VERSION 5.4 ;
NAMESCASESENSITIVE ON ;
BUSBITCHARS "[]" ;
DIVIDERCHAR "/" ;
UNITS
  DATABASE MICRONS 2000 ;
END UNITS
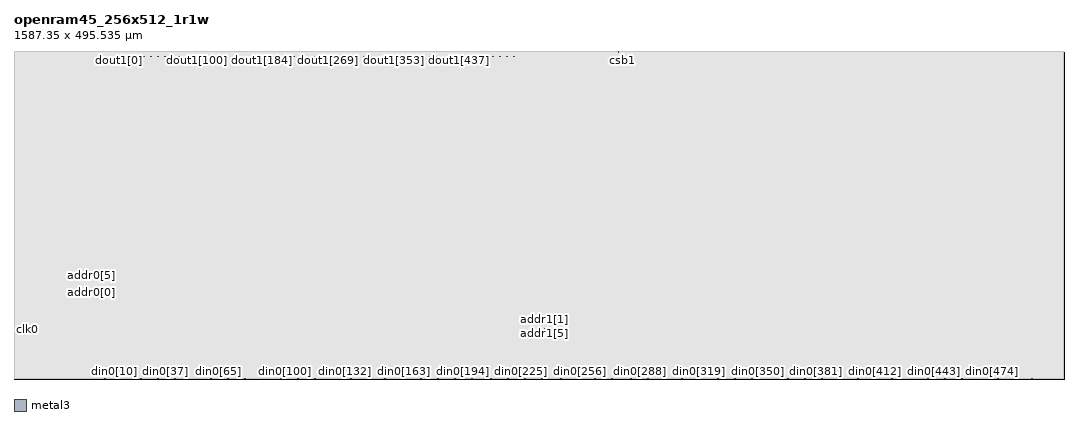
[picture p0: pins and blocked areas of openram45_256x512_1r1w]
MACRO openram45_256x512_1r1w
   CLASS BLOCK ;
   SIZE 1587.345 BY 495.535 ;
   SYMMETRY X Y R90 ;
   PIN din0[0]
      DIRECTION INPUT ;
      PORT
         LAYER metal3 ;
         RECT  123.24 1.0375 123.375 1.1725 ;
      END
   END din0[0]
   PIN din0[1]
      DIRECTION INPUT ;
      PORT
         LAYER metal3 ;
         RECT  126.1 1.0375 126.235 1.1725 ;
      END
   END din0[1]
   PIN din0[2]
      DIRECTION INPUT ;
      PORT
         LAYER metal3 ;
         RECT  128.96 1.0375 129.095 1.1725 ;
      END
   END din0[2]
   PIN din0[3]
      DIRECTION INPUT ;
      PORT
         LAYER metal3 ;
         RECT  131.82 1.0375 131.955 1.1725 ;
      END
   END din0[3]
   PIN din0[4]
      DIRECTION INPUT ;
      PORT
         LAYER metal3 ;
         RECT  134.68 1.0375 134.815 1.1725 ;
      END
   END din0[4]
   PIN din0[5]
      DIRECTION INPUT ;
      PORT
         LAYER metal3 ;
         RECT  137.54 1.0375 137.675 1.1725 ;
      END
   END din0[5]
   PIN din0[6]
      DIRECTION INPUT ;
      PORT
         LAYER metal3 ;
         RECT  140.4 1.0375 140.535 1.1725 ;
      END
   END din0[6]
   PIN din0[7]
      DIRECTION INPUT ;
      PORT
         LAYER metal3 ;
         RECT  143.26 1.0375 143.395 1.1725 ;
      END
   END din0[7]
   PIN din0[8]
      DIRECTION INPUT ;
      PORT
         LAYER metal3 ;
         RECT  146.12 1.0375 146.255 1.1725 ;
      END
   END din0[8]
   PIN din0[9]
      DIRECTION INPUT ;
      PORT
         LAYER metal3 ;
         RECT  148.98 1.0375 149.115 1.1725 ;
      END
   END din0[9]
   PIN din0[10]
      DIRECTION INPUT ;
      PORT
         LAYER metal3 ;
         RECT  151.84 1.0375 151.975 1.1725 ;
      END
   END din0[10]
   PIN din0[11]
      DIRECTION INPUT ;
      PORT
         LAYER metal3 ;
         RECT  154.7 1.0375 154.835 1.1725 ;
      END
   END din0[11]
   PIN din0[12]
      DIRECTION INPUT ;
      PORT
         LAYER metal3 ;
         RECT  157.56 1.0375 157.695 1.1725 ;
      END
   END din0[12]
   PIN din0[13]
      DIRECTION INPUT ;
      PORT
         LAYER metal3 ;
         RECT  160.42 1.0375 160.555 1.1725 ;
      END
   END din0[13]
   PIN din0[14]
      DIRECTION INPUT ;
      PORT
         LAYER metal3 ;
         RECT  163.28 1.0375 163.415 1.1725 ;
      END
   END din0[14]
   PIN din0[15]
      DIRECTION INPUT ;
      PORT
         LAYER metal3 ;
         RECT  166.14 1.0375 166.275 1.1725 ;
      END
   END din0[15]
   PIN din0[16]
      DIRECTION INPUT ;
      PORT
         LAYER metal3 ;
         RECT  169.0 1.0375 169.135 1.1725 ;
      END
   END din0[16]
   PIN din0[17]
      DIRECTION INPUT ;
      PORT
         LAYER metal3 ;
         RECT  171.86 1.0375 171.995 1.1725 ;
      END
   END din0[17]
   PIN din0[18]
      DIRECTION INPUT ;
      PORT
         LAYER metal3 ;
         RECT  174.72 1.0375 174.855 1.1725 ;
      END
   END din0[18]
   PIN din0[19]
      DIRECTION INPUT ;
      PORT
         LAYER metal3 ;
         RECT  177.58 1.0375 177.715 1.1725 ;
      END
   END din0[19]
   PIN din0[20]
      DIRECTION INPUT ;
      PORT
         LAYER metal3 ;
         RECT  180.44 1.0375 180.575 1.1725 ;
      END
   END din0[20]
   PIN din0[21]
      DIRECTION INPUT ;
      PORT
         LAYER metal3 ;
         RECT  183.3 1.0375 183.435 1.1725 ;
      END
   END din0[21]
   PIN din0[22]
      DIRECTION INPUT ;
      PORT
         LAYER metal3 ;
         RECT  186.16 1.0375 186.295 1.1725 ;
      END
   END din0[22]
   PIN din0[23]
      DIRECTION INPUT ;
      PORT
         LAYER metal3 ;
         RECT  189.02 1.0375 189.155 1.1725 ;
      END
   END din0[23]
   PIN din0[24]
      DIRECTION INPUT ;
      PORT
         LAYER metal3 ;
         RECT  191.88 1.0375 192.015 1.1725 ;
      END
   END din0[24]
   PIN din0[25]
      DIRECTION INPUT ;
      PORT
         LAYER metal3 ;
         RECT  194.74 1.0375 194.875 1.1725 ;
      END
   END din0[25]
   PIN din0[26]
      DIRECTION INPUT ;
      PORT
         LAYER metal3 ;
         RECT  197.6 1.0375 197.735 1.1725 ;
      END
   END din0[26]
   PIN din0[27]
      DIRECTION INPUT ;
      PORT
         LAYER metal3 ;
         RECT  200.46 1.0375 200.595 1.1725 ;
      END
   END din0[27]
   PIN din0[28]
      DIRECTION INPUT ;
      PORT
         LAYER metal3 ;
         RECT  203.32 1.0375 203.455 1.1725 ;
      END
   END din0[28]
   PIN din0[29]
      DIRECTION INPUT ;
      PORT
         LAYER metal3 ;
         RECT  206.18 1.0375 206.315 1.1725 ;
      END
   END din0[29]
   PIN din0[30]
      DIRECTION INPUT ;
      PORT
         LAYER metal3 ;
         RECT  209.04 1.0375 209.175 1.1725 ;
      END
   END din0[30]
   PIN din0[31]
      DIRECTION INPUT ;
      PORT
         LAYER metal3 ;
         RECT  211.9 1.0375 212.035 1.1725 ;
      END
   END din0[31]
   PIN din0[32]
      DIRECTION INPUT ;
      PORT
         LAYER metal3 ;
         RECT  214.76 1.0375 214.895 1.1725 ;
      END
   END din0[32]
   PIN din0[33]
      DIRECTION INPUT ;
      PORT
         LAYER metal3 ;
         RECT  217.62 1.0375 217.755 1.1725 ;
      END
   END din0[33]
   PIN din0[34]
      DIRECTION INPUT ;
      PORT
         LAYER metal3 ;
         RECT  220.48 1.0375 220.615 1.1725 ;
      END
   END din0[34]
   PIN din0[35]
      DIRECTION INPUT ;
      PORT
         LAYER metal3 ;
         RECT  223.34 1.0375 223.475 1.1725 ;
      END
   END din0[35]
   PIN din0[36]
      DIRECTION INPUT ;
      PORT
         LAYER metal3 ;
         RECT  226.2 1.0375 226.335 1.1725 ;
      END
   END din0[36]
   PIN din0[37]
      DIRECTION INPUT ;
      PORT
         LAYER metal3 ;
         RECT  229.06 1.0375 229.195 1.1725 ;
      END
   END din0[37]
   PIN din0[38]
      DIRECTION INPUT ;
      PORT
         LAYER metal3 ;
         RECT  231.92 1.0375 232.055 1.1725 ;
      END
   END din0[38]
   PIN din0[39]
      DIRECTION INPUT ;
      PORT
         LAYER metal3 ;
         RECT  234.78 1.0375 234.915 1.1725 ;
      END
   END din0[39]
   PIN din0[40]
      DIRECTION INPUT ;
      PORT
         LAYER metal3 ;
         RECT  237.64 1.0375 237.775 1.1725 ;
      END
   END din0[40]
   PIN din0[41]
      DIRECTION INPUT ;
      PORT
         LAYER metal3 ;
         RECT  240.5 1.0375 240.635 1.1725 ;
      END
   END din0[41]
   PIN din0[42]
      DIRECTION INPUT ;
      PORT
         LAYER metal3 ;
         RECT  243.36 1.0375 243.495 1.1725 ;
      END
   END din0[42]
   PIN din0[43]
      DIRECTION INPUT ;
      PORT
         LAYER metal3 ;
         RECT  246.22 1.0375 246.355 1.1725 ;
      END
   END din0[43]
   PIN din0[44]
      DIRECTION INPUT ;
      PORT
         LAYER metal3 ;
         RECT  249.08 1.0375 249.215 1.1725 ;
      END
   END din0[44]
   PIN din0[45]
      DIRECTION INPUT ;
      PORT
         LAYER metal3 ;
         RECT  251.94 1.0375 252.075 1.1725 ;
      END
   END din0[45]
   PIN din0[46]
      DIRECTION INPUT ;
      PORT
         LAYER metal3 ;
         RECT  254.8 1.0375 254.935 1.1725 ;
      END
   END din0[46]
   PIN din0[47]
      DIRECTION INPUT ;
      PORT
         LAYER metal3 ;
         RECT  257.66 1.0375 257.795 1.1725 ;
      END
   END din0[47]
   PIN din0[48]
      DIRECTION INPUT ;
      PORT
         LAYER metal3 ;
         RECT  260.52 1.0375 260.655 1.1725 ;
      END
   END din0[48]
   PIN din0[49]
      DIRECTION INPUT ;
      PORT
         LAYER metal3 ;
         RECT  263.38 1.0375 263.515 1.1725 ;
      END
   END din0[49]
   PIN din0[50]
      DIRECTION INPUT ;
      PORT
         LAYER metal3 ;
         RECT  266.24 1.0375 266.375 1.1725 ;
      END
   END din0[50]
   PIN din0[51]
      DIRECTION INPUT ;
      PORT
         LAYER metal3 ;
         RECT  269.1 1.0375 269.235 1.1725 ;
      END
   END din0[51]
   PIN din0[52]
      DIRECTION INPUT ;
      PORT
         LAYER metal3 ;
         RECT  271.96 1.0375 272.095 1.1725 ;
      END
   END din0[52]
   PIN din0[53]
      DIRECTION INPUT ;
      PORT
         LAYER metal3 ;
         RECT  274.82 1.0375 274.955 1.1725 ;
      END
   END din0[53]
   PIN din0[54]
      DIRECTION INPUT ;
      PORT
         LAYER metal3 ;
         RECT  277.68 1.0375 277.815 1.1725 ;
      END
   END din0[54]
   PIN din0[55]
      DIRECTION INPUT ;
      PORT
         LAYER metal3 ;
         RECT  280.54 1.0375 280.675 1.1725 ;
      END
   END din0[55]
   PIN din0[56]
      DIRECTION INPUT ;
      PORT
         LAYER metal3 ;
         RECT  283.4 1.0375 283.535 1.1725 ;
      END
   END din0[56]
   PIN din0[57]
      DIRECTION INPUT ;
      PORT
         LAYER metal3 ;
         RECT  286.26 1.0375 286.395 1.1725 ;
      END
   END din0[57]
   PIN din0[58]
      DIRECTION INPUT ;
      PORT
         LAYER metal3 ;
         RECT  289.12 1.0375 289.255 1.1725 ;
      END
   END din0[58]
   PIN din0[59]
      DIRECTION INPUT ;
      PORT
         LAYER metal3 ;
         RECT  291.98 1.0375 292.115 1.1725 ;
      END
   END din0[59]
   PIN din0[60]
      DIRECTION INPUT ;
      PORT
         LAYER metal3 ;
         RECT  294.84 1.0375 294.975 1.1725 ;
      END
   END din0[60]
   PIN din0[61]
      DIRECTION INPUT ;
      PORT
         LAYER metal3 ;
         RECT  297.7 1.0375 297.835 1.1725 ;
      END
   END din0[61]
   PIN din0[62]
      DIRECTION INPUT ;
      PORT
         LAYER metal3 ;
         RECT  300.56 1.0375 300.695 1.1725 ;
      END
   END din0[62]
   PIN din0[63]
      DIRECTION INPUT ;
      PORT
         LAYER metal3 ;
         RECT  303.42 1.0375 303.555 1.1725 ;
      END
   END din0[63]
   PIN din0[64]
      DIRECTION INPUT ;
      PORT
         LAYER metal3 ;
         RECT  306.28 1.0375 306.415 1.1725 ;
      END
   END din0[64]
   PIN din0[65]
      DIRECTION INPUT ;
      PORT
         LAYER metal3 ;
         RECT  309.14 1.0375 309.275 1.1725 ;
      END
   END din0[65]
   PIN din0[66]
      DIRECTION INPUT ;
      PORT
         LAYER metal3 ;
         RECT  312.0 1.0375 312.135 1.1725 ;
      END
   END din0[66]
   PIN din0[67]
      DIRECTION INPUT ;
      PORT
         LAYER metal3 ;
         RECT  314.86 1.0375 314.995 1.1725 ;
      END
   END din0[67]
   PIN din0[68]
      DIRECTION INPUT ;
      PORT
         LAYER metal3 ;
         RECT  317.72 1.0375 317.855 1.1725 ;
      END
   END din0[68]
   PIN din0[69]
      DIRECTION INPUT ;
      PORT
         LAYER metal3 ;
         RECT  320.58 1.0375 320.715 1.1725 ;
      END
   END din0[69]
   PIN din0[70]
      DIRECTION INPUT ;
      PORT
         LAYER metal3 ;
         RECT  323.44 1.0375 323.575 1.1725 ;
      END
   END din0[70]
   PIN din0[71]
      DIRECTION INPUT ;
      PORT
         LAYER metal3 ;
         RECT  326.3 1.0375 326.435 1.1725 ;
      END
   END din0[71]
   PIN din0[72]
      DIRECTION INPUT ;
      PORT
         LAYER metal3 ;
         RECT  329.16 1.0375 329.295 1.1725 ;
      END
   END din0[72]
   PIN din0[73]
      DIRECTION INPUT ;
      PORT
         LAYER metal3 ;
         RECT  332.02 1.0375 332.155 1.1725 ;
      END
   END din0[73]
   PIN din0[74]
      DIRECTION INPUT ;
      PORT
         LAYER metal3 ;
         RECT  334.88 1.0375 335.015 1.1725 ;
      END
   END din0[74]
   PIN din0[75]
      DIRECTION INPUT ;
      PORT
         LAYER metal3 ;
         RECT  337.74 1.0375 337.875 1.1725 ;
      END
   END din0[75]
   PIN din0[76]
      DIRECTION INPUT ;
      PORT
         LAYER metal3 ;
         RECT  340.6 1.0375 340.735 1.1725 ;
      END
   END din0[76]
   PIN din0[77]
      DIRECTION INPUT ;
      PORT
         LAYER metal3 ;
         RECT  343.46 1.0375 343.595 1.1725 ;
      END
   END din0[77]
   PIN din0[78]
      DIRECTION INPUT ;
      PORT
         LAYER metal3 ;
         RECT  346.32 1.0375 346.455 1.1725 ;
      END
   END din0[78]
   PIN din0[79]
      DIRECTION INPUT ;
      PORT
         LAYER metal3 ;
         RECT  349.18 1.0375 349.315 1.1725 ;
      END
   END din0[79]
   PIN din0[80]
      DIRECTION INPUT ;
      PORT
         LAYER metal3 ;
         RECT  352.04 1.0375 352.175 1.1725 ;
      END
   END din0[80]
   PIN din0[81]
      DIRECTION INPUT ;
      PORT
         LAYER metal3 ;
         RECT  354.9 1.0375 355.035 1.1725 ;
      END
   END din0[81]
   PIN din0[82]
      DIRECTION INPUT ;
      PORT
         LAYER metal3 ;
         RECT  357.76 1.0375 357.895 1.1725 ;
      END
   END din0[82]
   PIN din0[83]
      DIRECTION INPUT ;
      PORT
         LAYER metal3 ;
         RECT  360.62 1.0375 360.755 1.1725 ;
      END
   END din0[83]
   PIN din0[84]
      DIRECTION INPUT ;
      PORT
         LAYER metal3 ;
         RECT  363.48 1.0375 363.615 1.1725 ;
      END
   END din0[84]
   PIN din0[85]
      DIRECTION INPUT ;
      PORT
         LAYER metal3 ;
         RECT  366.34 1.0375 366.475 1.1725 ;
      END
   END din0[85]
   PIN din0[86]
      DIRECTION INPUT ;
      PORT
         LAYER metal3 ;
         RECT  369.2 1.0375 369.335 1.1725 ;
      END
   END din0[86]
   PIN din0[87]
      DIRECTION INPUT ;
      PORT
         LAYER metal3 ;
         RECT  372.06 1.0375 372.195 1.1725 ;
      END
   END din0[87]
   PIN din0[88]
      DIRECTION INPUT ;
      PORT
         LAYER metal3 ;
         RECT  374.92 1.0375 375.055 1.1725 ;
      END
   END din0[88]
   PIN din0[89]
      DIRECTION INPUT ;
      PORT
         LAYER metal3 ;
         RECT  377.78 1.0375 377.915 1.1725 ;
      END
   END din0[89]
   PIN din0[90]
      DIRECTION INPUT ;
      PORT
         LAYER metal3 ;
         RECT  380.64 1.0375 380.775 1.1725 ;
      END
   END din0[90]
   PIN din0[91]
      DIRECTION INPUT ;
      PORT
         LAYER metal3 ;
         RECT  383.5 1.0375 383.635 1.1725 ;
      END
   END din0[91]
   PIN din0[92]
      DIRECTION INPUT ;
      PORT
         LAYER metal3 ;
         RECT  386.36 1.0375 386.495 1.1725 ;
      END
   END din0[92]
   PIN din0[93]
      DIRECTION INPUT ;
      PORT
         LAYER metal3 ;
         RECT  389.22 1.0375 389.355 1.1725 ;
      END
   END din0[93]
   PIN din0[94]
      DIRECTION INPUT ;
      PORT
         LAYER metal3 ;
         RECT  392.08 1.0375 392.215 1.1725 ;
      END
   END din0[94]
   PIN din0[95]
      DIRECTION INPUT ;
      PORT
         LAYER metal3 ;
         RECT  394.94 1.0375 395.075 1.1725 ;
      END
   END din0[95]
   PIN din0[96]
      DIRECTION INPUT ;
      PORT
         LAYER metal3 ;
         RECT  397.8 1.0375 397.935 1.1725 ;
      END
   END din0[96]
   PIN din0[97]
      DIRECTION INPUT ;
      PORT
         LAYER metal3 ;
         RECT  400.66 1.0375 400.795 1.1725 ;
      END
   END din0[97]
   PIN din0[98]
      DIRECTION INPUT ;
      PORT
         LAYER metal3 ;
         RECT  403.52 1.0375 403.655 1.1725 ;
      END
   END din0[98]
   PIN din0[99]
      DIRECTION INPUT ;
      PORT
         LAYER metal3 ;
         RECT  406.38 1.0375 406.515 1.1725 ;
      END
   END din0[99]
   PIN din0[100]
      DIRECTION INPUT ;
      PORT
         LAYER metal3 ;
         RECT  409.24 1.0375 409.375 1.1725 ;
      END
   END din0[100]
   PIN din0[101]
      DIRECTION INPUT ;
      PORT
         LAYER metal3 ;
         RECT  412.1 1.0375 412.235 1.1725 ;
      END
   END din0[101]
   PIN din0[102]
      DIRECTION INPUT ;
      PORT
         LAYER metal3 ;
         RECT  414.96 1.0375 415.095 1.1725 ;
      END
   END din0[102]
   PIN din0[103]
      DIRECTION INPUT ;
      PORT
         LAYER metal3 ;
         RECT  417.82 1.0375 417.955 1.1725 ;
      END
   END din0[103]
   PIN din0[104]
      DIRECTION INPUT ;
      PORT
         LAYER metal3 ;
         RECT  420.68 1.0375 420.815 1.1725 ;
      END
   END din0[104]
   PIN din0[105]
      DIRECTION INPUT ;
      PORT
         LAYER metal3 ;
         RECT  423.54 1.0375 423.675 1.1725 ;
      END
   END din0[105]
   PIN din0[106]
      DIRECTION INPUT ;
      PORT
         LAYER metal3 ;
         RECT  426.4 1.0375 426.535 1.1725 ;
      END
   END din0[106]
   PIN din0[107]
      DIRECTION INPUT ;
      PORT
         LAYER metal3 ;
         RECT  429.26 1.0375 429.395 1.1725 ;
      END
   END din0[107]
   PIN din0[108]
      DIRECTION INPUT ;
      PORT
         LAYER metal3 ;
         RECT  432.12 1.0375 432.255 1.1725 ;
      END
   END din0[108]
   PIN din0[109]
      DIRECTION INPUT ;
      PORT
         LAYER metal3 ;
         RECT  434.98 1.0375 435.115 1.1725 ;
      END
   END din0[109]
   PIN din0[110]
      DIRECTION INPUT ;
      PORT
         LAYER metal3 ;
         RECT  437.84 1.0375 437.975 1.1725 ;
      END
   END din0[110]
   PIN din0[111]
      DIRECTION INPUT ;
      PORT
         LAYER metal3 ;
         RECT  440.7 1.0375 440.835 1.1725 ;
      END
   END din0[111]
   PIN din0[112]
      DIRECTION INPUT ;
      PORT
         LAYER metal3 ;
         RECT  443.56 1.0375 443.695 1.1725 ;
      END
   END din0[112]
   PIN din0[113]
      DIRECTION INPUT ;
      PORT
         LAYER metal3 ;
         RECT  446.42 1.0375 446.555 1.1725 ;
      END
   END din0[113]
   PIN din0[114]
      DIRECTION INPUT ;
      PORT
         LAYER metal3 ;
         RECT  449.28 1.0375 449.415 1.1725 ;
      END
   END din0[114]
   PIN din0[115]
      DIRECTION INPUT ;
      PORT
         LAYER metal3 ;
         RECT  452.14 1.0375 452.275 1.1725 ;
      END
   END din0[115]
   PIN din0[116]
      DIRECTION INPUT ;
      PORT
         LAYER metal3 ;
         RECT  455.0 1.0375 455.135 1.1725 ;
      END
   END din0[116]
   PIN din0[117]
      DIRECTION INPUT ;
      PORT
         LAYER metal3 ;
         RECT  457.86 1.0375 457.995 1.1725 ;
      END
   END din0[117]
   PIN din0[118]
      DIRECTION INPUT ;
      PORT
         LAYER metal3 ;
         RECT  460.72 1.0375 460.855 1.1725 ;
      END
   END din0[118]
   PIN din0[119]
      DIRECTION INPUT ;
      PORT
         LAYER metal3 ;
         RECT  463.58 1.0375 463.715 1.1725 ;
      END
   END din0[119]
   PIN din0[120]
      DIRECTION INPUT ;
      PORT
         LAYER metal3 ;
         RECT  466.44 1.0375 466.575 1.1725 ;
      END
   END din0[120]
   PIN din0[121]
      DIRECTION INPUT ;
      PORT
         LAYER metal3 ;
         RECT  469.3 1.0375 469.435 1.1725 ;
      END
   END din0[121]
   PIN din0[122]
      DIRECTION INPUT ;
      PORT
         LAYER metal3 ;
         RECT  472.16 1.0375 472.295 1.1725 ;
      END
   END din0[122]
   PIN din0[123]
      DIRECTION INPUT ;
      PORT
         LAYER metal3 ;
         RECT  475.02 1.0375 475.155 1.1725 ;
      END
   END din0[123]
   PIN din0[124]
      DIRECTION INPUT ;
      PORT
         LAYER metal3 ;
         RECT  477.88 1.0375 478.015 1.1725 ;
      END
   END din0[124]
   PIN din0[125]
      DIRECTION INPUT ;
      PORT
         LAYER metal3 ;
         RECT  480.74 1.0375 480.875 1.1725 ;
      END
   END din0[125]
   PIN din0[126]
      DIRECTION INPUT ;
      PORT
         LAYER metal3 ;
         RECT  483.6 1.0375 483.735 1.1725 ;
      END
   END din0[126]
   PIN din0[127]
      DIRECTION INPUT ;
      PORT
         LAYER metal3 ;
         RECT  486.46 1.0375 486.595 1.1725 ;
      END
   END din0[127]
   PIN din0[128]
      DIRECTION INPUT ;
      PORT
         LAYER metal3 ;
         RECT  489.32 1.0375 489.455 1.1725 ;
      END
   END din0[128]
   PIN din0[129]
      DIRECTION INPUT ;
      PORT
         LAYER metal3 ;
         RECT  492.18 1.0375 492.315 1.1725 ;
      END
   END din0[129]
   PIN din0[130]
      DIRECTION INPUT ;
      PORT
         LAYER metal3 ;
         RECT  495.04 1.0375 495.175 1.1725 ;
      END
   END din0[130]
   PIN din0[131]
      DIRECTION INPUT ;
      PORT
         LAYER metal3 ;
         RECT  497.9 1.0375 498.035 1.1725 ;
      END
   END din0[131]
   PIN din0[132]
      DIRECTION INPUT ;
      PORT
         LAYER metal3 ;
         RECT  500.76 1.0375 500.895 1.1725 ;
      END
   END din0[132]
   PIN din0[133]
      DIRECTION INPUT ;
      PORT
         LAYER metal3 ;
         RECT  503.62 1.0375 503.755 1.1725 ;
      END
   END din0[133]
   PIN din0[134]
      DIRECTION INPUT ;
      PORT
         LAYER metal3 ;
         RECT  506.48 1.0375 506.615 1.1725 ;
      END
   END din0[134]
   PIN din0[135]
      DIRECTION INPUT ;
      PORT
         LAYER metal3 ;
         RECT  509.34 1.0375 509.475 1.1725 ;
      END
   END din0[135]
   PIN din0[136]
      DIRECTION INPUT ;
      PORT
         LAYER metal3 ;
         RECT  512.2 1.0375 512.335 1.1725 ;
      END
   END din0[136]
   PIN din0[137]
      DIRECTION INPUT ;
      PORT
         LAYER metal3 ;
         RECT  515.06 1.0375 515.195 1.1725 ;
      END
   END din0[137]
   PIN din0[138]
      DIRECTION INPUT ;
      PORT
         LAYER metal3 ;
         RECT  517.92 1.0375 518.055 1.1725 ;
      END
   END din0[138]
   PIN din0[139]
      DIRECTION INPUT ;
      PORT
         LAYER metal3 ;
         RECT  520.78 1.0375 520.915 1.1725 ;
      END
   END din0[139]
   PIN din0[140]
      DIRECTION INPUT ;
      PORT
         LAYER metal3 ;
         RECT  523.64 1.0375 523.775 1.1725 ;
      END
   END din0[140]
   PIN din0[141]
      DIRECTION INPUT ;
      PORT
         LAYER metal3 ;
         RECT  526.5 1.0375 526.635 1.1725 ;
      END
   END din0[141]
   PIN din0[142]
      DIRECTION INPUT ;
      PORT
         LAYER metal3 ;
         RECT  529.36 1.0375 529.495 1.1725 ;
      END
   END din0[142]
   PIN din0[143]
      DIRECTION INPUT ;
      PORT
         LAYER metal3 ;
         RECT  532.22 1.0375 532.355 1.1725 ;
      END
   END din0[143]
   PIN din0[144]
      DIRECTION INPUT ;
      PORT
         LAYER metal3 ;
         RECT  535.08 1.0375 535.215 1.1725 ;
      END
   END din0[144]
   PIN din0[145]
      DIRECTION INPUT ;
      PORT
         LAYER metal3 ;
         RECT  537.94 1.0375 538.075 1.1725 ;
      END
   END din0[145]
   PIN din0[146]
      DIRECTION INPUT ;
      PORT
         LAYER metal3 ;
         RECT  540.8 1.0375 540.935 1.1725 ;
      END
   END din0[146]
   PIN din0[147]
      DIRECTION INPUT ;
      PORT
         LAYER metal3 ;
         RECT  543.66 1.0375 543.795 1.1725 ;
      END
   END din0[147]
   PIN din0[148]
      DIRECTION INPUT ;
      PORT
         LAYER metal3 ;
         RECT  546.52 1.0375 546.655 1.1725 ;
      END
   END din0[148]
   PIN din0[149]
      DIRECTION INPUT ;
      PORT
         LAYER metal3 ;
         RECT  549.38 1.0375 549.515 1.1725 ;
      END
   END din0[149]
   PIN din0[150]
      DIRECTION INPUT ;
      PORT
         LAYER metal3 ;
         RECT  552.24 1.0375 552.375 1.1725 ;
      END
   END din0[150]
   PIN din0[151]
      DIRECTION INPUT ;
      PORT
         LAYER metal3 ;
         RECT  555.1 1.0375 555.235 1.1725 ;
      END
   END din0[151]
   PIN din0[152]
      DIRECTION INPUT ;
      PORT
         LAYER metal3 ;
         RECT  557.96 1.0375 558.095 1.1725 ;
      END
   END din0[152]
   PIN din0[153]
      DIRECTION INPUT ;
      PORT
         LAYER metal3 ;
         RECT  560.82 1.0375 560.955 1.1725 ;
      END
   END din0[153]
   PIN din0[154]
      DIRECTION INPUT ;
      PORT
         LAYER metal3 ;
         RECT  563.68 1.0375 563.815 1.1725 ;
      END
   END din0[154]
   PIN din0[155]
      DIRECTION INPUT ;
      PORT
         LAYER metal3 ;
         RECT  566.54 1.0375 566.675 1.1725 ;
      END
   END din0[155]
   PIN din0[156]
      DIRECTION INPUT ;
      PORT
         LAYER metal3 ;
         RECT  569.4 1.0375 569.535 1.1725 ;
      END
   END din0[156]
   PIN din0[157]
      DIRECTION INPUT ;
      PORT
         LAYER metal3 ;
         RECT  572.26 1.0375 572.395 1.1725 ;
      END
   END din0[157]
   PIN din0[158]
      DIRECTION INPUT ;
      PORT
         LAYER metal3 ;
         RECT  575.12 1.0375 575.255 1.1725 ;
      END
   END din0[158]
   PIN din0[159]
      DIRECTION INPUT ;
      PORT
         LAYER metal3 ;
         RECT  577.98 1.0375 578.115 1.1725 ;
      END
   END din0[159]
   PIN din0[160]
      DIRECTION INPUT ;
      PORT
         LAYER metal3 ;
         RECT  580.84 1.0375 580.975 1.1725 ;
      END
   END din0[160]
   PIN din0[161]
      DIRECTION INPUT ;
      PORT
         LAYER metal3 ;
         RECT  583.7 1.0375 583.835 1.1725 ;
      END
   END din0[161]
   PIN din0[162]
      DIRECTION INPUT ;
      PORT
         LAYER metal3 ;
         RECT  586.56 1.0375 586.695 1.1725 ;
      END
   END din0[162]
   PIN din0[163]
      DIRECTION INPUT ;
      PORT
         LAYER metal3 ;
         RECT  589.42 1.0375 589.555 1.1725 ;
      END
   END din0[163]
   PIN din0[164]
      DIRECTION INPUT ;
      PORT
         LAYER metal3 ;
         RECT  592.28 1.0375 592.415 1.1725 ;
      END
   END din0[164]
   PIN din0[165]
      DIRECTION INPUT ;
      PORT
         LAYER metal3 ;
         RECT  595.14 1.0375 595.275 1.1725 ;
      END
   END din0[165]
   PIN din0[166]
      DIRECTION INPUT ;
      PORT
         LAYER metal3 ;
         RECT  598.0 1.0375 598.135 1.1725 ;
      END
   END din0[166]
   PIN din0[167]
      DIRECTION INPUT ;
      PORT
         LAYER metal3 ;
         RECT  600.86 1.0375 600.995 1.1725 ;
      END
   END din0[167]
   PIN din0[168]
      DIRECTION INPUT ;
      PORT
         LAYER metal3 ;
         RECT  603.72 1.0375 603.855 1.1725 ;
      END
   END din0[168]
   PIN din0[169]
      DIRECTION INPUT ;
      PORT
         LAYER metal3 ;
         RECT  606.58 1.0375 606.715 1.1725 ;
      END
   END din0[169]
   PIN din0[170]
      DIRECTION INPUT ;
      PORT
         LAYER metal3 ;
         RECT  609.44 1.0375 609.575 1.1725 ;
      END
   END din0[170]
   PIN din0[171]
      DIRECTION INPUT ;
      PORT
         LAYER metal3 ;
         RECT  612.3 1.0375 612.435 1.1725 ;
      END
   END din0[171]
   PIN din0[172]
      DIRECTION INPUT ;
      PORT
         LAYER metal3 ;
         RECT  615.16 1.0375 615.295 1.1725 ;
      END
   END din0[172]
   PIN din0[173]
      DIRECTION INPUT ;
      PORT
         LAYER metal3 ;
         RECT  618.02 1.0375 618.155 1.1725 ;
      END
   END din0[173]
   PIN din0[174]
      DIRECTION INPUT ;
      PORT
         LAYER metal3 ;
         RECT  620.88 1.0375 621.015 1.1725 ;
      END
   END din0[174]
   PIN din0[175]
      DIRECTION INPUT ;
      PORT
         LAYER metal3 ;
         RECT  623.74 1.0375 623.875 1.1725 ;
      END
   END din0[175]
   PIN din0[176]
      DIRECTION INPUT ;
      PORT
         LAYER metal3 ;
         RECT  626.6 1.0375 626.735 1.1725 ;
      END
   END din0[176]
   PIN din0[177]
      DIRECTION INPUT ;
      PORT
         LAYER metal3 ;
         RECT  629.46 1.0375 629.595 1.1725 ;
      END
   END din0[177]
   PIN din0[178]
      DIRECTION INPUT ;
      PORT
         LAYER metal3 ;
         RECT  632.32 1.0375 632.455 1.1725 ;
      END
   END din0[178]
   PIN din0[179]
      DIRECTION INPUT ;
      PORT
         LAYER metal3 ;
         RECT  635.18 1.0375 635.315 1.1725 ;
      END
   END din0[179]
   PIN din0[180]
      DIRECTION INPUT ;
      PORT
         LAYER metal3 ;
         RECT  638.04 1.0375 638.175 1.1725 ;
      END
   END din0[180]
   PIN din0[181]
      DIRECTION INPUT ;
      PORT
         LAYER metal3 ;
         RECT  640.9 1.0375 641.035 1.1725 ;
      END
   END din0[181]
   PIN din0[182]
      DIRECTION INPUT ;
      PORT
         LAYER metal3 ;
         RECT  643.76 1.0375 643.895 1.1725 ;
      END
   END din0[182]
   PIN din0[183]
      DIRECTION INPUT ;
      PORT
         LAYER metal3 ;
         RECT  646.62 1.0375 646.755 1.1725 ;
      END
   END din0[183]
   PIN din0[184]
      DIRECTION INPUT ;
      PORT
         LAYER metal3 ;
         RECT  649.48 1.0375 649.615 1.1725 ;
      END
   END din0[184]
   PIN din0[185]
      DIRECTION INPUT ;
      PORT
         LAYER metal3 ;
         RECT  652.34 1.0375 652.475 1.1725 ;
      END
   END din0[185]
   PIN din0[186]
      DIRECTION INPUT ;
      PORT
         LAYER metal3 ;
         RECT  655.2 1.0375 655.335 1.1725 ;
      END
   END din0[186]
   PIN din0[187]
      DIRECTION INPUT ;
      PORT
         LAYER metal3 ;
         RECT  658.06 1.0375 658.195 1.1725 ;
      END
   END din0[187]
   PIN din0[188]
      DIRECTION INPUT ;
      PORT
         LAYER metal3 ;
         RECT  660.92 1.0375 661.055 1.1725 ;
      END
   END din0[188]
   PIN din0[189]
      DIRECTION INPUT ;
      PORT
         LAYER metal3 ;
         RECT  663.78 1.0375 663.915 1.1725 ;
      END
   END din0[189]
   PIN din0[190]
      DIRECTION INPUT ;
      PORT
         LAYER metal3 ;
         RECT  666.64 1.0375 666.775 1.1725 ;
      END
   END din0[190]
   PIN din0[191]
      DIRECTION INPUT ;
      PORT
         LAYER metal3 ;
         RECT  669.5 1.0375 669.635 1.1725 ;
      END
   END din0[191]
   PIN din0[192]
      DIRECTION INPUT ;
      PORT
         LAYER metal3 ;
         RECT  672.36 1.0375 672.495 1.1725 ;
      END
   END din0[192]
   PIN din0[193]
      DIRECTION INPUT ;
      PORT
         LAYER metal3 ;
         RECT  675.22 1.0375 675.355 1.1725 ;
      END
   END din0[193]
   PIN din0[194]
      DIRECTION INPUT ;
      PORT
         LAYER metal3 ;
         RECT  678.08 1.0375 678.215 1.1725 ;
      END
   END din0[194]
   PIN din0[195]
      DIRECTION INPUT ;
      PORT
         LAYER metal3 ;
         RECT  680.94 1.0375 681.075 1.1725 ;
      END
   END din0[195]
   PIN din0[196]
      DIRECTION INPUT ;
      PORT
         LAYER metal3 ;
         RECT  683.8 1.0375 683.935 1.1725 ;
      END
   END din0[196]
   PIN din0[197]
      DIRECTION INPUT ;
      PORT
         LAYER metal3 ;
         RECT  686.66 1.0375 686.795 1.1725 ;
      END
   END din0[197]
   PIN din0[198]
      DIRECTION INPUT ;
      PORT
         LAYER metal3 ;
         RECT  689.52 1.0375 689.655 1.1725 ;
      END
   END din0[198]
   PIN din0[199]
      DIRECTION INPUT ;
      PORT
         LAYER metal3 ;
         RECT  692.38 1.0375 692.515 1.1725 ;
      END
   END din0[199]
   PIN din0[200]
      DIRECTION INPUT ;
      PORT
         LAYER metal3 ;
         RECT  695.24 1.0375 695.375 1.1725 ;
      END
   END din0[200]
   PIN din0[201]
      DIRECTION INPUT ;
      PORT
         LAYER metal3 ;
         RECT  698.1 1.0375 698.235 1.1725 ;
      END
   END din0[201]
   PIN din0[202]
      DIRECTION INPUT ;
      PORT
         LAYER metal3 ;
         RECT  700.96 1.0375 701.095 1.1725 ;
      END
   END din0[202]
   PIN din0[203]
      DIRECTION INPUT ;
      PORT
         LAYER metal3 ;
         RECT  703.82 1.0375 703.955 1.1725 ;
      END
   END din0[203]
   PIN din0[204]
      DIRECTION INPUT ;
      PORT
         LAYER metal3 ;
         RECT  706.68 1.0375 706.815 1.1725 ;
      END
   END din0[204]
   PIN din0[205]
      DIRECTION INPUT ;
      PORT
         LAYER metal3 ;
         RECT  709.54 1.0375 709.675 1.1725 ;
      END
   END din0[205]
   PIN din0[206]
      DIRECTION INPUT ;
      PORT
         LAYER metal3 ;
         RECT  712.4 1.0375 712.535 1.1725 ;
      END
   END din0[206]
   PIN din0[207]
      DIRECTION INPUT ;
      PORT
         LAYER metal3 ;
         RECT  715.26 1.0375 715.395 1.1725 ;
      END
   END din0[207]
   PIN din0[208]
      DIRECTION INPUT ;
      PORT
         LAYER metal3 ;
         RECT  718.12 1.0375 718.255 1.1725 ;
      END
   END din0[208]
   PIN din0[209]
      DIRECTION INPUT ;
      PORT
         LAYER metal3 ;
         RECT  720.98 1.0375 721.115 1.1725 ;
      END
   END din0[209]
   PIN din0[210]
      DIRECTION INPUT ;
      PORT
         LAYER metal3 ;
         RECT  723.84 1.0375 723.975 1.1725 ;
      END
   END din0[210]
   PIN din0[211]
      DIRECTION INPUT ;
      PORT
         LAYER metal3 ;
         RECT  726.7 1.0375 726.835 1.1725 ;
      END
   END din0[211]
   PIN din0[212]
      DIRECTION INPUT ;
      PORT
         LAYER metal3 ;
         RECT  729.56 1.0375 729.695 1.1725 ;
      END
   END din0[212]
   PIN din0[213]
      DIRECTION INPUT ;
      PORT
         LAYER metal3 ;
         RECT  732.42 1.0375 732.555 1.1725 ;
      END
   END din0[213]
   PIN din0[214]
      DIRECTION INPUT ;
      PORT
         LAYER metal3 ;
         RECT  735.28 1.0375 735.415 1.1725 ;
      END
   END din0[214]
   PIN din0[215]
      DIRECTION INPUT ;
      PORT
         LAYER metal3 ;
         RECT  738.14 1.0375 738.275 1.1725 ;
      END
   END din0[215]
   PIN din0[216]
      DIRECTION INPUT ;
      PORT
         LAYER metal3 ;
         RECT  741.0 1.0375 741.135 1.1725 ;
      END
   END din0[216]
   PIN din0[217]
      DIRECTION INPUT ;
      PORT
         LAYER metal3 ;
         RECT  743.86 1.0375 743.995 1.1725 ;
      END
   END din0[217]
   PIN din0[218]
      DIRECTION INPUT ;
      PORT
         LAYER metal3 ;
         RECT  746.72 1.0375 746.855 1.1725 ;
      END
   END din0[218]
   PIN din0[219]
      DIRECTION INPUT ;
      PORT
         LAYER metal3 ;
         RECT  749.58 1.0375 749.715 1.1725 ;
      END
   END din0[219]
   PIN din0[220]
      DIRECTION INPUT ;
      PORT
         LAYER metal3 ;
         RECT  752.44 1.0375 752.575 1.1725 ;
      END
   END din0[220]
   PIN din0[221]
      DIRECTION INPUT ;
      PORT
         LAYER metal3 ;
         RECT  755.3 1.0375 755.435 1.1725 ;
      END
   END din0[221]
   PIN din0[222]
      DIRECTION INPUT ;
      PORT
         LAYER metal3 ;
         RECT  758.16 1.0375 758.295 1.1725 ;
      END
   END din0[222]
   PIN din0[223]
      DIRECTION INPUT ;
      PORT
         LAYER metal3 ;
         RECT  761.02 1.0375 761.155 1.1725 ;
      END
   END din0[223]
   PIN din0[224]
      DIRECTION INPUT ;
      PORT
         LAYER metal3 ;
         RECT  763.88 1.0375 764.015 1.1725 ;
      END
   END din0[224]
   PIN din0[225]
      DIRECTION INPUT ;
      PORT
         LAYER metal3 ;
         RECT  766.74 1.0375 766.875 1.1725 ;
      END
   END din0[225]
   PIN din0[226]
      DIRECTION INPUT ;
      PORT
         LAYER metal3 ;
         RECT  769.6 1.0375 769.735 1.1725 ;
      END
   END din0[226]
   PIN din0[227]
      DIRECTION INPUT ;
      PORT
         LAYER metal3 ;
         RECT  772.46 1.0375 772.595 1.1725 ;
      END
   END din0[227]
   PIN din0[228]
      DIRECTION INPUT ;
      PORT
         LAYER metal3 ;
         RECT  775.32 1.0375 775.455 1.1725 ;
      END
   END din0[228]
   PIN din0[229]
      DIRECTION INPUT ;
      PORT
         LAYER metal3 ;
         RECT  778.18 1.0375 778.315 1.1725 ;
      END
   END din0[229]
   PIN din0[230]
      DIRECTION INPUT ;
      PORT
         LAYER metal3 ;
         RECT  781.04 1.0375 781.175 1.1725 ;
      END
   END din0[230]
   PIN din0[231]
      DIRECTION INPUT ;
      PORT
         LAYER metal3 ;
         RECT  783.9 1.0375 784.035 1.1725 ;
      END
   END din0[231]
   PIN din0[232]
      DIRECTION INPUT ;
      PORT
         LAYER metal3 ;
         RECT  786.76 1.0375 786.895 1.1725 ;
      END
   END din0[232]
   PIN din0[233]
      DIRECTION INPUT ;
      PORT
         LAYER metal3 ;
         RECT  789.62 1.0375 789.755 1.1725 ;
      END
   END din0[233]
   PIN din0[234]
      DIRECTION INPUT ;
      PORT
         LAYER metal3 ;
         RECT  792.48 1.0375 792.615 1.1725 ;
      END
   END din0[234]
   PIN din0[235]
      DIRECTION INPUT ;
      PORT
         LAYER metal3 ;
         RECT  795.34 1.0375 795.475 1.1725 ;
      END
   END din0[235]
   PIN din0[236]
      DIRECTION INPUT ;
      PORT
         LAYER metal3 ;
         RECT  798.2 1.0375 798.335 1.1725 ;
      END
   END din0[236]
   PIN din0[237]
      DIRECTION INPUT ;
      PORT
         LAYER metal3 ;
         RECT  801.06 1.0375 801.195 1.1725 ;
      END
   END din0[237]
   PIN din0[238]
      DIRECTION INPUT ;
      PORT
         LAYER metal3 ;
         RECT  803.92 1.0375 804.055 1.1725 ;
      END
   END din0[238]
   PIN din0[239]
      DIRECTION INPUT ;
      PORT
         LAYER metal3 ;
         RECT  806.78 1.0375 806.915 1.1725 ;
      END
   END din0[239]
   PIN din0[240]
      DIRECTION INPUT ;
      PORT
         LAYER metal3 ;
         RECT  809.64 1.0375 809.775 1.1725 ;
      END
   END din0[240]
   PIN din0[241]
      DIRECTION INPUT ;
      PORT
         LAYER metal3 ;
         RECT  812.5 1.0375 812.635 1.1725 ;
      END
   END din0[241]
   PIN din0[242]
      DIRECTION INPUT ;
      PORT
         LAYER metal3 ;
         RECT  815.36 1.0375 815.495 1.1725 ;
      END
   END din0[242]
   PIN din0[243]
      DIRECTION INPUT ;
      PORT
         LAYER metal3 ;
         RECT  818.22 1.0375 818.355 1.1725 ;
      END
   END din0[243]
   PIN din0[244]
      DIRECTION INPUT ;
      PORT
         LAYER metal3 ;
         RECT  821.08 1.0375 821.215 1.1725 ;
      END
   END din0[244]
   PIN din0[245]
      DIRECTION INPUT ;
      PORT
         LAYER metal3 ;
         RECT  823.94 1.0375 824.075 1.1725 ;
      END
   END din0[245]
   PIN din0[246]
      DIRECTION INPUT ;
      PORT
         LAYER metal3 ;
         RECT  826.8 1.0375 826.935 1.1725 ;
      END
   END din0[246]
   PIN din0[247]
      DIRECTION INPUT ;
      PORT
         LAYER metal3 ;
         RECT  829.66 1.0375 829.795 1.1725 ;
      END
   END din0[247]
   PIN din0[248]
      DIRECTION INPUT ;
      PORT
         LAYER metal3 ;
         RECT  832.52 1.0375 832.655 1.1725 ;
      END
   END din0[248]
   PIN din0[249]
      DIRECTION INPUT ;
      PORT
         LAYER metal3 ;
         RECT  835.38 1.0375 835.515 1.1725 ;
      END
   END din0[249]
   PIN din0[250]
      DIRECTION INPUT ;
      PORT
         LAYER metal3 ;
         RECT  838.24 1.0375 838.375 1.1725 ;
      END
   END din0[250]
   PIN din0[251]
      DIRECTION INPUT ;
      PORT
         LAYER metal3 ;
         RECT  841.1 1.0375 841.235 1.1725 ;
      END
   END din0[251]
   PIN din0[252]
      DIRECTION INPUT ;
      PORT
         LAYER metal3 ;
         RECT  843.96 1.0375 844.095 1.1725 ;
      END
   END din0[252]
   PIN din0[253]
      DIRECTION INPUT ;
      PORT
         LAYER metal3 ;
         RECT  846.82 1.0375 846.955 1.1725 ;
      END
   END din0[253]
   PIN din0[254]
      DIRECTION INPUT ;
      PORT
         LAYER metal3 ;
         RECT  849.68 1.0375 849.815 1.1725 ;
      END
   END din0[254]
   PIN din0[255]
      DIRECTION INPUT ;
      PORT
         LAYER metal3 ;
         RECT  852.54 1.0375 852.675 1.1725 ;
      END
   END din0[255]
   PIN din0[256]
      DIRECTION INPUT ;
      PORT
         LAYER metal3 ;
         RECT  855.4 1.0375 855.535 1.1725 ;
      END
   END din0[256]
   PIN din0[257]
      DIRECTION INPUT ;
      PORT
         LAYER metal3 ;
         RECT  858.26 1.0375 858.395 1.1725 ;
      END
   END din0[257]
   PIN din0[258]
      DIRECTION INPUT ;
      PORT
         LAYER metal3 ;
         RECT  861.12 1.0375 861.255 1.1725 ;
      END
   END din0[258]
   PIN din0[259]
      DIRECTION INPUT ;
      PORT
         LAYER metal3 ;
         RECT  863.98 1.0375 864.115 1.1725 ;
      END
   END din0[259]
   PIN din0[260]
      DIRECTION INPUT ;
      PORT
         LAYER metal3 ;
         RECT  866.84 1.0375 866.975 1.1725 ;
      END
   END din0[260]
   PIN din0[261]
      DIRECTION INPUT ;
      PORT
         LAYER metal3 ;
         RECT  869.7 1.0375 869.835 1.1725 ;
      END
   END din0[261]
   PIN din0[262]
      DIRECTION INPUT ;
      PORT
         LAYER metal3 ;
         RECT  872.56 1.0375 872.695 1.1725 ;
      END
   END din0[262]
   PIN din0[263]
      DIRECTION INPUT ;
      PORT
         LAYER metal3 ;
         RECT  875.42 1.0375 875.555 1.1725 ;
      END
   END din0[263]
   PIN din0[264]
      DIRECTION INPUT ;
      PORT
         LAYER metal3 ;
         RECT  878.28 1.0375 878.415 1.1725 ;
      END
   END din0[264]
   PIN din0[265]
      DIRECTION INPUT ;
      PORT
         LAYER metal3 ;
         RECT  881.14 1.0375 881.275 1.1725 ;
      END
   END din0[265]
   PIN din0[266]
      DIRECTION INPUT ;
      PORT
         LAYER metal3 ;
         RECT  884.0 1.0375 884.135 1.1725 ;
      END
   END din0[266]
   PIN din0[267]
      DIRECTION INPUT ;
      PORT
         LAYER metal3 ;
         RECT  886.86 1.0375 886.995 1.1725 ;
      END
   END din0[267]
   PIN din0[268]
      DIRECTION INPUT ;
      PORT
         LAYER metal3 ;
         RECT  889.72 1.0375 889.855 1.1725 ;
      END
   END din0[268]
   PIN din0[269]
      DIRECTION INPUT ;
      PORT
         LAYER metal3 ;
         RECT  892.58 1.0375 892.715 1.1725 ;
      END
   END din0[269]
   PIN din0[270]
      DIRECTION INPUT ;
      PORT
         LAYER metal3 ;
         RECT  895.44 1.0375 895.575 1.1725 ;
      END
   END din0[270]
   PIN din0[271]
      DIRECTION INPUT ;
      PORT
         LAYER metal3 ;
         RECT  898.3 1.0375 898.435 1.1725 ;
      END
   END din0[271]
   PIN din0[272]
      DIRECTION INPUT ;
      PORT
         LAYER metal3 ;
         RECT  901.16 1.0375 901.295 1.1725 ;
      END
   END din0[272]
   PIN din0[273]
      DIRECTION INPUT ;
      PORT
         LAYER metal3 ;
         RECT  904.02 1.0375 904.155 1.1725 ;
      END
   END din0[273]
   PIN din0[274]
      DIRECTION INPUT ;
      PORT
         LAYER metal3 ;
         RECT  906.88 1.0375 907.015 1.1725 ;
      END
   END din0[274]
   PIN din0[275]
      DIRECTION INPUT ;
      PORT
         LAYER metal3 ;
         RECT  909.74 1.0375 909.875 1.1725 ;
      END
   END din0[275]
   PIN din0[276]
      DIRECTION INPUT ;
      PORT
         LAYER metal3 ;
         RECT  912.6 1.0375 912.735 1.1725 ;
      END
   END din0[276]
   PIN din0[277]
      DIRECTION INPUT ;
      PORT
         LAYER metal3 ;
         RECT  915.46 1.0375 915.595 1.1725 ;
      END
   END din0[277]
   PIN din0[278]
      DIRECTION INPUT ;
      PORT
         LAYER metal3 ;
         RECT  918.32 1.0375 918.455 1.1725 ;
      END
   END din0[278]
   PIN din0[279]
      DIRECTION INPUT ;
      PORT
         LAYER metal3 ;
         RECT  921.18 1.0375 921.315 1.1725 ;
      END
   END din0[279]
   PIN din0[280]
      DIRECTION INPUT ;
      PORT
         LAYER metal3 ;
         RECT  924.04 1.0375 924.175 1.1725 ;
      END
   END din0[280]
   PIN din0[281]
      DIRECTION INPUT ;
      PORT
         LAYER metal3 ;
         RECT  926.9 1.0375 927.035 1.1725 ;
      END
   END din0[281]
   PIN din0[282]
      DIRECTION INPUT ;
      PORT
         LAYER metal3 ;
         RECT  929.76 1.0375 929.895 1.1725 ;
      END
   END din0[282]
   PIN din0[283]
      DIRECTION INPUT ;
      PORT
         LAYER metal3 ;
         RECT  932.62 1.0375 932.755 1.1725 ;
      END
   END din0[283]
   PIN din0[284]
      DIRECTION INPUT ;
      PORT
         LAYER metal3 ;
         RECT  935.48 1.0375 935.615 1.1725 ;
      END
   END din0[284]
   PIN din0[285]
      DIRECTION INPUT ;
      PORT
         LAYER metal3 ;
         RECT  938.34 1.0375 938.475 1.1725 ;
      END
   END din0[285]
   PIN din0[286]
      DIRECTION INPUT ;
      PORT
         LAYER metal3 ;
         RECT  941.2 1.0375 941.335 1.1725 ;
      END
   END din0[286]
   PIN din0[287]
      DIRECTION INPUT ;
      PORT
         LAYER metal3 ;
         RECT  944.06 1.0375 944.195 1.1725 ;
      END
   END din0[287]
   PIN din0[288]
      DIRECTION INPUT ;
      PORT
         LAYER metal3 ;
         RECT  946.92 1.0375 947.055 1.1725 ;
      END
   END din0[288]
   PIN din0[289]
      DIRECTION INPUT ;
      PORT
         LAYER metal3 ;
         RECT  949.78 1.0375 949.915 1.1725 ;
      END
   END din0[289]
   PIN din0[290]
      DIRECTION INPUT ;
      PORT
         LAYER metal3 ;
         RECT  952.64 1.0375 952.775 1.1725 ;
      END
   END din0[290]
   PIN din0[291]
      DIRECTION INPUT ;
      PORT
         LAYER metal3 ;
         RECT  955.5 1.0375 955.635 1.1725 ;
      END
   END din0[291]
   PIN din0[292]
      DIRECTION INPUT ;
      PORT
         LAYER metal3 ;
         RECT  958.36 1.0375 958.495 1.1725 ;
      END
   END din0[292]
   PIN din0[293]
      DIRECTION INPUT ;
      PORT
         LAYER metal3 ;
         RECT  961.22 1.0375 961.355 1.1725 ;
      END
   END din0[293]
   PIN din0[294]
      DIRECTION INPUT ;
      PORT
         LAYER metal3 ;
         RECT  964.08 1.0375 964.215 1.1725 ;
      END
   END din0[294]
   PIN din0[295]
      DIRECTION INPUT ;
      PORT
         LAYER metal3 ;
         RECT  966.94 1.0375 967.075 1.1725 ;
      END
   END din0[295]
   PIN din0[296]
      DIRECTION INPUT ;
      PORT
         LAYER metal3 ;
         RECT  969.8 1.0375 969.935 1.1725 ;
      END
   END din0[296]
   PIN din0[297]
      DIRECTION INPUT ;
      PORT
         LAYER metal3 ;
         RECT  972.66 1.0375 972.795 1.1725 ;
      END
   END din0[297]
   PIN din0[298]
      DIRECTION INPUT ;
      PORT
         LAYER metal3 ;
         RECT  975.52 1.0375 975.655 1.1725 ;
      END
   END din0[298]
   PIN din0[299]
      DIRECTION INPUT ;
      PORT
         LAYER metal3 ;
         RECT  978.38 1.0375 978.515 1.1725 ;
      END
   END din0[299]
   PIN din0[300]
      DIRECTION INPUT ;
      PORT
         LAYER metal3 ;
         RECT  981.24 1.0375 981.375 1.1725 ;
      END
   END din0[300]
   PIN din0[301]
      DIRECTION INPUT ;
      PORT
         LAYER metal3 ;
         RECT  984.1 1.0375 984.235 1.1725 ;
      END
   END din0[301]
   PIN din0[302]
      DIRECTION INPUT ;
      PORT
         LAYER metal3 ;
         RECT  986.96 1.0375 987.095 1.1725 ;
      END
   END din0[302]
   PIN din0[303]
      DIRECTION INPUT ;
      PORT
         LAYER metal3 ;
         RECT  989.82 1.0375 989.955 1.1725 ;
      END
   END din0[303]
   PIN din0[304]
      DIRECTION INPUT ;
      PORT
         LAYER metal3 ;
         RECT  992.68 1.0375 992.815 1.1725 ;
      END
   END din0[304]
   PIN din0[305]
      DIRECTION INPUT ;
      PORT
         LAYER metal3 ;
         RECT  995.54 1.0375 995.675 1.1725 ;
      END
   END din0[305]
   PIN din0[306]
      DIRECTION INPUT ;
      PORT
         LAYER metal3 ;
         RECT  998.4 1.0375 998.535 1.1725 ;
      END
   END din0[306]
   PIN din0[307]
      DIRECTION INPUT ;
      PORT
         LAYER metal3 ;
         RECT  1001.26 1.0375 1001.395 1.1725 ;
      END
   END din0[307]
   PIN din0[308]
      DIRECTION INPUT ;
      PORT
         LAYER metal3 ;
         RECT  1004.12 1.0375 1004.255 1.1725 ;
      END
   END din0[308]
   PIN din0[309]
      DIRECTION INPUT ;
      PORT
         LAYER metal3 ;
         RECT  1006.98 1.0375 1007.115 1.1725 ;
      END
   END din0[309]
   PIN din0[310]
      DIRECTION INPUT ;
      PORT
         LAYER metal3 ;
         RECT  1009.84 1.0375 1009.975 1.1725 ;
      END
   END din0[310]
   PIN din0[311]
      DIRECTION INPUT ;
      PORT
         LAYER metal3 ;
         RECT  1012.7 1.0375 1012.835 1.1725 ;
      END
   END din0[311]
   PIN din0[312]
      DIRECTION INPUT ;
      PORT
         LAYER metal3 ;
         RECT  1015.56 1.0375 1015.695 1.1725 ;
      END
   END din0[312]
   PIN din0[313]
      DIRECTION INPUT ;
      PORT
         LAYER metal3 ;
         RECT  1018.42 1.0375 1018.555 1.1725 ;
      END
   END din0[313]
   PIN din0[314]
      DIRECTION INPUT ;
      PORT
         LAYER metal3 ;
         RECT  1021.28 1.0375 1021.415 1.1725 ;
      END
   END din0[314]
   PIN din0[315]
      DIRECTION INPUT ;
      PORT
         LAYER metal3 ;
         RECT  1024.14 1.0375 1024.275 1.1725 ;
      END
   END din0[315]
   PIN din0[316]
      DIRECTION INPUT ;
      PORT
         LAYER metal3 ;
         RECT  1027.0 1.0375 1027.135 1.1725 ;
      END
   END din0[316]
   PIN din0[317]
      DIRECTION INPUT ;
      PORT
         LAYER metal3 ;
         RECT  1029.86 1.0375 1029.995 1.1725 ;
      END
   END din0[317]
   PIN din0[318]
      DIRECTION INPUT ;
      PORT
         LAYER metal3 ;
         RECT  1032.72 1.0375 1032.855 1.1725 ;
      END
   END din0[318]
   PIN din0[319]
      DIRECTION INPUT ;
      PORT
         LAYER metal3 ;
         RECT  1035.58 1.0375 1035.715 1.1725 ;
      END
   END din0[319]
   PIN din0[320]
      DIRECTION INPUT ;
      PORT
         LAYER metal3 ;
         RECT  1038.44 1.0375 1038.575 1.1725 ;
      END
   END din0[320]
   PIN din0[321]
      DIRECTION INPUT ;
      PORT
         LAYER metal3 ;
         RECT  1041.3 1.0375 1041.435 1.1725 ;
      END
   END din0[321]
   PIN din0[322]
      DIRECTION INPUT ;
      PORT
         LAYER metal3 ;
         RECT  1044.16 1.0375 1044.295 1.1725 ;
      END
   END din0[322]
   PIN din0[323]
      DIRECTION INPUT ;
      PORT
         LAYER metal3 ;
         RECT  1047.02 1.0375 1047.155 1.1725 ;
      END
   END din0[323]
   PIN din0[324]
      DIRECTION INPUT ;
      PORT
         LAYER metal3 ;
         RECT  1049.88 1.0375 1050.015 1.1725 ;
      END
   END din0[324]
   PIN din0[325]
      DIRECTION INPUT ;
      PORT
         LAYER metal3 ;
         RECT  1052.74 1.0375 1052.875 1.1725 ;
      END
   END din0[325]
   PIN din0[326]
      DIRECTION INPUT ;
      PORT
         LAYER metal3 ;
         RECT  1055.6 1.0375 1055.735 1.1725 ;
      END
   END din0[326]
   PIN din0[327]
      DIRECTION INPUT ;
      PORT
         LAYER metal3 ;
         RECT  1058.46 1.0375 1058.595 1.1725 ;
      END
   END din0[327]
   PIN din0[328]
      DIRECTION INPUT ;
      PORT
         LAYER metal3 ;
         RECT  1061.32 1.0375 1061.455 1.1725 ;
      END
   END din0[328]
   PIN din0[329]
      DIRECTION INPUT ;
      PORT
         LAYER metal3 ;
         RECT  1064.18 1.0375 1064.315 1.1725 ;
      END
   END din0[329]
   PIN din0[330]
      DIRECTION INPUT ;
      PORT
         LAYER metal3 ;
         RECT  1067.04 1.0375 1067.175 1.1725 ;
      END
   END din0[330]
   PIN din0[331]
      DIRECTION INPUT ;
      PORT
         LAYER metal3 ;
         RECT  1069.9 1.0375 1070.035 1.1725 ;
      END
   END din0[331]
   PIN din0[332]
      DIRECTION INPUT ;
      PORT
         LAYER metal3 ;
         RECT  1072.76 1.0375 1072.895 1.1725 ;
      END
   END din0[332]
   PIN din0[333]
      DIRECTION INPUT ;
      PORT
         LAYER metal3 ;
         RECT  1075.62 1.0375 1075.755 1.1725 ;
      END
   END din0[333]
   PIN din0[334]
      DIRECTION INPUT ;
      PORT
         LAYER metal3 ;
         RECT  1078.48 1.0375 1078.615 1.1725 ;
      END
   END din0[334]
   PIN din0[335]
      DIRECTION INPUT ;
      PORT
         LAYER metal3 ;
         RECT  1081.34 1.0375 1081.475 1.1725 ;
      END
   END din0[335]
   PIN din0[336]
      DIRECTION INPUT ;
      PORT
         LAYER metal3 ;
         RECT  1084.2 1.0375 1084.335 1.1725 ;
      END
   END din0[336]
   PIN din0[337]
      DIRECTION INPUT ;
      PORT
         LAYER metal3 ;
         RECT  1087.06 1.0375 1087.195 1.1725 ;
      END
   END din0[337]
   PIN din0[338]
      DIRECTION INPUT ;
      PORT
         LAYER metal3 ;
         RECT  1089.92 1.0375 1090.055 1.1725 ;
      END
   END din0[338]
   PIN din0[339]
      DIRECTION INPUT ;
      PORT
         LAYER metal3 ;
         RECT  1092.78 1.0375 1092.915 1.1725 ;
      END
   END din0[339]
   PIN din0[340]
      DIRECTION INPUT ;
      PORT
         LAYER metal3 ;
         RECT  1095.64 1.0375 1095.775 1.1725 ;
      END
   END din0[340]
   PIN din0[341]
      DIRECTION INPUT ;
      PORT
         LAYER metal3 ;
         RECT  1098.5 1.0375 1098.635 1.1725 ;
      END
   END din0[341]
   PIN din0[342]
      DIRECTION INPUT ;
      PORT
         LAYER metal3 ;
         RECT  1101.36 1.0375 1101.495 1.1725 ;
      END
   END din0[342]
   PIN din0[343]
      DIRECTION INPUT ;
      PORT
         LAYER metal3 ;
         RECT  1104.22 1.0375 1104.355 1.1725 ;
      END
   END din0[343]
   PIN din0[344]
      DIRECTION INPUT ;
      PORT
         LAYER metal3 ;
         RECT  1107.08 1.0375 1107.215 1.1725 ;
      END
   END din0[344]
   PIN din0[345]
      DIRECTION INPUT ;
      PORT
         LAYER metal3 ;
         RECT  1109.94 1.0375 1110.075 1.1725 ;
      END
   END din0[345]
   PIN din0[346]
      DIRECTION INPUT ;
      PORT
         LAYER metal3 ;
         RECT  1112.8 1.0375 1112.935 1.1725 ;
      END
   END din0[346]
   PIN din0[347]
      DIRECTION INPUT ;
      PORT
         LAYER metal3 ;
         RECT  1115.66 1.0375 1115.795 1.1725 ;
      END
   END din0[347]
   PIN din0[348]
      DIRECTION INPUT ;
      PORT
         LAYER metal3 ;
         RECT  1118.52 1.0375 1118.655 1.1725 ;
      END
   END din0[348]
   PIN din0[349]
      DIRECTION INPUT ;
      PORT
         LAYER metal3 ;
         RECT  1121.38 1.0375 1121.515 1.1725 ;
      END
   END din0[349]
   PIN din0[350]
      DIRECTION INPUT ;
      PORT
         LAYER metal3 ;
         RECT  1124.24 1.0375 1124.375 1.1725 ;
      END
   END din0[350]
   PIN din0[351]
      DIRECTION INPUT ;
      PORT
         LAYER metal3 ;
         RECT  1127.1 1.0375 1127.235 1.1725 ;
      END
   END din0[351]
   PIN din0[352]
      DIRECTION INPUT ;
      PORT
         LAYER metal3 ;
         RECT  1129.96 1.0375 1130.095 1.1725 ;
      END
   END din0[352]
   PIN din0[353]
      DIRECTION INPUT ;
      PORT
         LAYER metal3 ;
         RECT  1132.82 1.0375 1132.955 1.1725 ;
      END
   END din0[353]
   PIN din0[354]
      DIRECTION INPUT ;
      PORT
         LAYER metal3 ;
         RECT  1135.68 1.0375 1135.815 1.1725 ;
      END
   END din0[354]
   PIN din0[355]
      DIRECTION INPUT ;
      PORT
         LAYER metal3 ;
         RECT  1138.54 1.0375 1138.675 1.1725 ;
      END
   END din0[355]
   PIN din0[356]
      DIRECTION INPUT ;
      PORT
         LAYER metal3 ;
         RECT  1141.4 1.0375 1141.535 1.1725 ;
      END
   END din0[356]
   PIN din0[357]
      DIRECTION INPUT ;
      PORT
         LAYER metal3 ;
         RECT  1144.26 1.0375 1144.395 1.1725 ;
      END
   END din0[357]
   PIN din0[358]
      DIRECTION INPUT ;
      PORT
         LAYER metal3 ;
         RECT  1147.12 1.0375 1147.255 1.1725 ;
      END
   END din0[358]
   PIN din0[359]
      DIRECTION INPUT ;
      PORT
         LAYER metal3 ;
         RECT  1149.98 1.0375 1150.115 1.1725 ;
      END
   END din0[359]
   PIN din0[360]
      DIRECTION INPUT ;
      PORT
         LAYER metal3 ;
         RECT  1152.84 1.0375 1152.975 1.1725 ;
      END
   END din0[360]
   PIN din0[361]
      DIRECTION INPUT ;
      PORT
         LAYER metal3 ;
         RECT  1155.7 1.0375 1155.835 1.1725 ;
      END
   END din0[361]
   PIN din0[362]
      DIRECTION INPUT ;
      PORT
         LAYER metal3 ;
         RECT  1158.56 1.0375 1158.695 1.1725 ;
      END
   END din0[362]
   PIN din0[363]
      DIRECTION INPUT ;
      PORT
         LAYER metal3 ;
         RECT  1161.42 1.0375 1161.555 1.1725 ;
      END
   END din0[363]
   PIN din0[364]
      DIRECTION INPUT ;
      PORT
         LAYER metal3 ;
         RECT  1164.28 1.0375 1164.415 1.1725 ;
      END
   END din0[364]
   PIN din0[365]
      DIRECTION INPUT ;
      PORT
         LAYER metal3 ;
         RECT  1167.14 1.0375 1167.275 1.1725 ;
      END
   END din0[365]
   PIN din0[366]
      DIRECTION INPUT ;
      PORT
         LAYER metal3 ;
         RECT  1170.0 1.0375 1170.135 1.1725 ;
      END
   END din0[366]
   PIN din0[367]
      DIRECTION INPUT ;
      PORT
         LAYER metal3 ;
         RECT  1172.86 1.0375 1172.995 1.1725 ;
      END
   END din0[367]
   PIN din0[368]
      DIRECTION INPUT ;
      PORT
         LAYER metal3 ;
         RECT  1175.72 1.0375 1175.855 1.1725 ;
      END
   END din0[368]
   PIN din0[369]
      DIRECTION INPUT ;
      PORT
         LAYER metal3 ;
         RECT  1178.58 1.0375 1178.715 1.1725 ;
      END
   END din0[369]
   PIN din0[370]
      DIRECTION INPUT ;
      PORT
         LAYER metal3 ;
         RECT  1181.44 1.0375 1181.575 1.1725 ;
      END
   END din0[370]
   PIN din0[371]
      DIRECTION INPUT ;
      PORT
         LAYER metal3 ;
         RECT  1184.3 1.0375 1184.435 1.1725 ;
      END
   END din0[371]
   PIN din0[372]
      DIRECTION INPUT ;
      PORT
         LAYER metal3 ;
         RECT  1187.16 1.0375 1187.295 1.1725 ;
      END
   END din0[372]
   PIN din0[373]
      DIRECTION INPUT ;
      PORT
         LAYER metal3 ;
         RECT  1190.02 1.0375 1190.155 1.1725 ;
      END
   END din0[373]
   PIN din0[374]
      DIRECTION INPUT ;
      PORT
         LAYER metal3 ;
         RECT  1192.88 1.0375 1193.015 1.1725 ;
      END
   END din0[374]
   PIN din0[375]
      DIRECTION INPUT ;
      PORT
         LAYER metal3 ;
         RECT  1195.74 1.0375 1195.875 1.1725 ;
      END
   END din0[375]
   PIN din0[376]
      DIRECTION INPUT ;
      PORT
         LAYER metal3 ;
         RECT  1198.6 1.0375 1198.735 1.1725 ;
      END
   END din0[376]
   PIN din0[377]
      DIRECTION INPUT ;
      PORT
         LAYER metal3 ;
         RECT  1201.46 1.0375 1201.595 1.1725 ;
      END
   END din0[377]
   PIN din0[378]
      DIRECTION INPUT ;
      PORT
         LAYER metal3 ;
         RECT  1204.32 1.0375 1204.455 1.1725 ;
      END
   END din0[378]
   PIN din0[379]
      DIRECTION INPUT ;
      PORT
         LAYER metal3 ;
         RECT  1207.18 1.0375 1207.315 1.1725 ;
      END
   END din0[379]
   PIN din0[380]
      DIRECTION INPUT ;
      PORT
         LAYER metal3 ;
         RECT  1210.04 1.0375 1210.175 1.1725 ;
      END
   END din0[380]
   PIN din0[381]
      DIRECTION INPUT ;
      PORT
         LAYER metal3 ;
         RECT  1212.9 1.0375 1213.035 1.1725 ;
      END
   END din0[381]
   PIN din0[382]
      DIRECTION INPUT ;
      PORT
         LAYER metal3 ;
         RECT  1215.76 1.0375 1215.895 1.1725 ;
      END
   END din0[382]
   PIN din0[383]
      DIRECTION INPUT ;
      PORT
         LAYER metal3 ;
         RECT  1218.62 1.0375 1218.755 1.1725 ;
      END
   END din0[383]
   PIN din0[384]
      DIRECTION INPUT ;
      PORT
         LAYER metal3 ;
         RECT  1221.48 1.0375 1221.615 1.1725 ;
      END
   END din0[384]
   PIN din0[385]
      DIRECTION INPUT ;
      PORT
         LAYER metal3 ;
         RECT  1224.34 1.0375 1224.475 1.1725 ;
      END
   END din0[385]
   PIN din0[386]
      DIRECTION INPUT ;
      PORT
         LAYER metal3 ;
         RECT  1227.2 1.0375 1227.335 1.1725 ;
      END
   END din0[386]
   PIN din0[387]
      DIRECTION INPUT ;
      PORT
         LAYER metal3 ;
         RECT  1230.06 1.0375 1230.195 1.1725 ;
      END
   END din0[387]
   PIN din0[388]
      DIRECTION INPUT ;
      PORT
         LAYER metal3 ;
         RECT  1232.92 1.0375 1233.055 1.1725 ;
      END
   END din0[388]
   PIN din0[389]
      DIRECTION INPUT ;
      PORT
         LAYER metal3 ;
         RECT  1235.78 1.0375 1235.915 1.1725 ;
      END
   END din0[389]
   PIN din0[390]
      DIRECTION INPUT ;
      PORT
         LAYER metal3 ;
         RECT  1238.64 1.0375 1238.775 1.1725 ;
      END
   END din0[390]
   PIN din0[391]
      DIRECTION INPUT ;
      PORT
         LAYER metal3 ;
         RECT  1241.5 1.0375 1241.635 1.1725 ;
      END
   END din0[391]
   PIN din0[392]
      DIRECTION INPUT ;
      PORT
         LAYER metal3 ;
         RECT  1244.36 1.0375 1244.495 1.1725 ;
      END
   END din0[392]
   PIN din0[393]
      DIRECTION INPUT ;
      PORT
         LAYER metal3 ;
         RECT  1247.22 1.0375 1247.355 1.1725 ;
      END
   END din0[393]
   PIN din0[394]
      DIRECTION INPUT ;
      PORT
         LAYER metal3 ;
         RECT  1250.08 1.0375 1250.215 1.1725 ;
      END
   END din0[394]
   PIN din0[395]
      DIRECTION INPUT ;
      PORT
         LAYER metal3 ;
         RECT  1252.94 1.0375 1253.075 1.1725 ;
      END
   END din0[395]
   PIN din0[396]
      DIRECTION INPUT ;
      PORT
         LAYER metal3 ;
         RECT  1255.8 1.0375 1255.935 1.1725 ;
      END
   END din0[396]
   PIN din0[397]
      DIRECTION INPUT ;
      PORT
         LAYER metal3 ;
         RECT  1258.66 1.0375 1258.795 1.1725 ;
      END
   END din0[397]
   PIN din0[398]
      DIRECTION INPUT ;
      PORT
         LAYER metal3 ;
         RECT  1261.52 1.0375 1261.655 1.1725 ;
      END
   END din0[398]
   PIN din0[399]
      DIRECTION INPUT ;
      PORT
         LAYER metal3 ;
         RECT  1264.38 1.0375 1264.515 1.1725 ;
      END
   END din0[399]
   PIN din0[400]
      DIRECTION INPUT ;
      PORT
         LAYER metal3 ;
         RECT  1267.24 1.0375 1267.375 1.1725 ;
      END
   END din0[400]
   PIN din0[401]
      DIRECTION INPUT ;
      PORT
         LAYER metal3 ;
         RECT  1270.1 1.0375 1270.235 1.1725 ;
      END
   END din0[401]
   PIN din0[402]
      DIRECTION INPUT ;
      PORT
         LAYER metal3 ;
         RECT  1272.96 1.0375 1273.095 1.1725 ;
      END
   END din0[402]
   PIN din0[403]
      DIRECTION INPUT ;
      PORT
         LAYER metal3 ;
         RECT  1275.82 1.0375 1275.955 1.1725 ;
      END
   END din0[403]
   PIN din0[404]
      DIRECTION INPUT ;
      PORT
         LAYER metal3 ;
         RECT  1278.68 1.0375 1278.815 1.1725 ;
      END
   END din0[404]
   PIN din0[405]
      DIRECTION INPUT ;
      PORT
         LAYER metal3 ;
         RECT  1281.54 1.0375 1281.675 1.1725 ;
      END
   END din0[405]
   PIN din0[406]
      DIRECTION INPUT ;
      PORT
         LAYER metal3 ;
         RECT  1284.4 1.0375 1284.535 1.1725 ;
      END
   END din0[406]
   PIN din0[407]
      DIRECTION INPUT ;
      PORT
         LAYER metal3 ;
         RECT  1287.26 1.0375 1287.395 1.1725 ;
      END
   END din0[407]
   PIN din0[408]
      DIRECTION INPUT ;
      PORT
         LAYER metal3 ;
         RECT  1290.12 1.0375 1290.255 1.1725 ;
      END
   END din0[408]
   PIN din0[409]
      DIRECTION INPUT ;
      PORT
         LAYER metal3 ;
         RECT  1292.98 1.0375 1293.115 1.1725 ;
      END
   END din0[409]
   PIN din0[410]
      DIRECTION INPUT ;
      PORT
         LAYER metal3 ;
         RECT  1295.84 1.0375 1295.975 1.1725 ;
      END
   END din0[410]
   PIN din0[411]
      DIRECTION INPUT ;
      PORT
         LAYER metal3 ;
         RECT  1298.7 1.0375 1298.835 1.1725 ;
      END
   END din0[411]
   PIN din0[412]
      DIRECTION INPUT ;
      PORT
         LAYER metal3 ;
         RECT  1301.56 1.0375 1301.695 1.1725 ;
      END
   END din0[412]
   PIN din0[413]
      DIRECTION INPUT ;
      PORT
         LAYER metal3 ;
         RECT  1304.42 1.0375 1304.555 1.1725 ;
      END
   END din0[413]
   PIN din0[414]
      DIRECTION INPUT ;
      PORT
         LAYER metal3 ;
         RECT  1307.28 1.0375 1307.415 1.1725 ;
      END
   END din0[414]
   PIN din0[415]
      DIRECTION INPUT ;
      PORT
         LAYER metal3 ;
         RECT  1310.14 1.0375 1310.275 1.1725 ;
      END
   END din0[415]
   PIN din0[416]
      DIRECTION INPUT ;
      PORT
         LAYER metal3 ;
         RECT  1313.0 1.0375 1313.135 1.1725 ;
      END
   END din0[416]
   PIN din0[417]
      DIRECTION INPUT ;
      PORT
         LAYER metal3 ;
         RECT  1315.86 1.0375 1315.995 1.1725 ;
      END
   END din0[417]
   PIN din0[418]
      DIRECTION INPUT ;
      PORT
         LAYER metal3 ;
         RECT  1318.72 1.0375 1318.855 1.1725 ;
      END
   END din0[418]
   PIN din0[419]
      DIRECTION INPUT ;
      PORT
         LAYER metal3 ;
         RECT  1321.58 1.0375 1321.715 1.1725 ;
      END
   END din0[419]
   PIN din0[420]
      DIRECTION INPUT ;
      PORT
         LAYER metal3 ;
         RECT  1324.44 1.0375 1324.575 1.1725 ;
      END
   END din0[420]
   PIN din0[421]
      DIRECTION INPUT ;
      PORT
         LAYER metal3 ;
         RECT  1327.3 1.0375 1327.435 1.1725 ;
      END
   END din0[421]
   PIN din0[422]
      DIRECTION INPUT ;
      PORT
         LAYER metal3 ;
         RECT  1330.16 1.0375 1330.295 1.1725 ;
      END
   END din0[422]
   PIN din0[423]
      DIRECTION INPUT ;
      PORT
         LAYER metal3 ;
         RECT  1333.02 1.0375 1333.155 1.1725 ;
      END
   END din0[423]
   PIN din0[424]
      DIRECTION INPUT ;
      PORT
         LAYER metal3 ;
         RECT  1335.88 1.0375 1336.015 1.1725 ;
      END
   END din0[424]
   PIN din0[425]
      DIRECTION INPUT ;
      PORT
         LAYER metal3 ;
         RECT  1338.74 1.0375 1338.875 1.1725 ;
      END
   END din0[425]
   PIN din0[426]
      DIRECTION INPUT ;
      PORT
         LAYER metal3 ;
         RECT  1341.6 1.0375 1341.735 1.1725 ;
      END
   END din0[426]
   PIN din0[427]
      DIRECTION INPUT ;
      PORT
         LAYER metal3 ;
         RECT  1344.46 1.0375 1344.595 1.1725 ;
      END
   END din0[427]
   PIN din0[428]
      DIRECTION INPUT ;
      PORT
         LAYER metal3 ;
         RECT  1347.32 1.0375 1347.455 1.1725 ;
      END
   END din0[428]
   PIN din0[429]
      DIRECTION INPUT ;
      PORT
         LAYER metal3 ;
         RECT  1350.18 1.0375 1350.315 1.1725 ;
      END
   END din0[429]
   PIN din0[430]
      DIRECTION INPUT ;
      PORT
         LAYER metal3 ;
         RECT  1353.04 1.0375 1353.175 1.1725 ;
      END
   END din0[430]
   PIN din0[431]
      DIRECTION INPUT ;
      PORT
         LAYER metal3 ;
         RECT  1355.9 1.0375 1356.035 1.1725 ;
      END
   END din0[431]
   PIN din0[432]
      DIRECTION INPUT ;
      PORT
         LAYER metal3 ;
         RECT  1358.76 1.0375 1358.895 1.1725 ;
      END
   END din0[432]
   PIN din0[433]
      DIRECTION INPUT ;
      PORT
         LAYER metal3 ;
         RECT  1361.62 1.0375 1361.755 1.1725 ;
      END
   END din0[433]
   PIN din0[434]
      DIRECTION INPUT ;
      PORT
         LAYER metal3 ;
         RECT  1364.48 1.0375 1364.615 1.1725 ;
      END
   END din0[434]
   PIN din0[435]
      DIRECTION INPUT ;
      PORT
         LAYER metal3 ;
         RECT  1367.34 1.0375 1367.475 1.1725 ;
      END
   END din0[435]
   PIN din0[436]
      DIRECTION INPUT ;
      PORT
         LAYER metal3 ;
         RECT  1370.2 1.0375 1370.335 1.1725 ;
      END
   END din0[436]
   PIN din0[437]
      DIRECTION INPUT ;
      PORT
         LAYER metal3 ;
         RECT  1373.06 1.0375 1373.195 1.1725 ;
      END
   END din0[437]
   PIN din0[438]
      DIRECTION INPUT ;
      PORT
         LAYER metal3 ;
         RECT  1375.92 1.0375 1376.055 1.1725 ;
      END
   END din0[438]
   PIN din0[439]
      DIRECTION INPUT ;
      PORT
         LAYER metal3 ;
         RECT  1378.78 1.0375 1378.915 1.1725 ;
      END
   END din0[439]
   PIN din0[440]
      DIRECTION INPUT ;
      PORT
         LAYER metal3 ;
         RECT  1381.64 1.0375 1381.775 1.1725 ;
      END
   END din0[440]
   PIN din0[441]
      DIRECTION INPUT ;
      PORT
         LAYER metal3 ;
         RECT  1384.5 1.0375 1384.635 1.1725 ;
      END
   END din0[441]
   PIN din0[442]
      DIRECTION INPUT ;
      PORT
         LAYER metal3 ;
         RECT  1387.36 1.0375 1387.495 1.1725 ;
      END
   END din0[442]
   PIN din0[443]
      DIRECTION INPUT ;
      PORT
         LAYER metal3 ;
         RECT  1390.22 1.0375 1390.355 1.1725 ;
      END
   END din0[443]
   PIN din0[444]
      DIRECTION INPUT ;
      PORT
         LAYER metal3 ;
         RECT  1393.08 1.0375 1393.215 1.1725 ;
      END
   END din0[444]
   PIN din0[445]
      DIRECTION INPUT ;
      PORT
         LAYER metal3 ;
         RECT  1395.94 1.0375 1396.075 1.1725 ;
      END
   END din0[445]
   PIN din0[446]
      DIRECTION INPUT ;
      PORT
         LAYER metal3 ;
         RECT  1398.8 1.0375 1398.935 1.1725 ;
      END
   END din0[446]
   PIN din0[447]
      DIRECTION INPUT ;
      PORT
         LAYER metal3 ;
         RECT  1401.66 1.0375 1401.795 1.1725 ;
      END
   END din0[447]
   PIN din0[448]
      DIRECTION INPUT ;
      PORT
         LAYER metal3 ;
         RECT  1404.52 1.0375 1404.655 1.1725 ;
      END
   END din0[448]
   PIN din0[449]
      DIRECTION INPUT ;
      PORT
         LAYER metal3 ;
         RECT  1407.38 1.0375 1407.515 1.1725 ;
      END
   END din0[449]
   PIN din0[450]
      DIRECTION INPUT ;
      PORT
         LAYER metal3 ;
         RECT  1410.24 1.0375 1410.375 1.1725 ;
      END
   END din0[450]
   PIN din0[451]
      DIRECTION INPUT ;
      PORT
         LAYER metal3 ;
         RECT  1413.1 1.0375 1413.235 1.1725 ;
      END
   END din0[451]
   PIN din0[452]
      DIRECTION INPUT ;
      PORT
         LAYER metal3 ;
         RECT  1415.96 1.0375 1416.095 1.1725 ;
      END
   END din0[452]
   PIN din0[453]
      DIRECTION INPUT ;
      PORT
         LAYER metal3 ;
         RECT  1418.82 1.0375 1418.955 1.1725 ;
      END
   END din0[453]
   PIN din0[454]
      DIRECTION INPUT ;
      PORT
         LAYER metal3 ;
         RECT  1421.68 1.0375 1421.815 1.1725 ;
      END
   END din0[454]
   PIN din0[455]
      DIRECTION INPUT ;
      PORT
         LAYER metal3 ;
         RECT  1424.54 1.0375 1424.675 1.1725 ;
      END
   END din0[455]
   PIN din0[456]
      DIRECTION INPUT ;
      PORT
         LAYER metal3 ;
         RECT  1427.4 1.0375 1427.535 1.1725 ;
      END
   END din0[456]
   PIN din0[457]
      DIRECTION INPUT ;
      PORT
         LAYER metal3 ;
         RECT  1430.26 1.0375 1430.395 1.1725 ;
      END
   END din0[457]
   PIN din0[458]
      DIRECTION INPUT ;
      PORT
         LAYER metal3 ;
         RECT  1433.12 1.0375 1433.255 1.1725 ;
      END
   END din0[458]
   PIN din0[459]
      DIRECTION INPUT ;
      PORT
         LAYER metal3 ;
         RECT  1435.98 1.0375 1436.115 1.1725 ;
      END
   END din0[459]
   PIN din0[460]
      DIRECTION INPUT ;
      PORT
         LAYER metal3 ;
         RECT  1438.84 1.0375 1438.975 1.1725 ;
      END
   END din0[460]
   PIN din0[461]
      DIRECTION INPUT ;
      PORT
         LAYER metal3 ;
         RECT  1441.7 1.0375 1441.835 1.1725 ;
      END
   END din0[461]
   PIN din0[462]
      DIRECTION INPUT ;
      PORT
         LAYER metal3 ;
         RECT  1444.56 1.0375 1444.695 1.1725 ;
      END
   END din0[462]
   PIN din0[463]
      DIRECTION INPUT ;
      PORT
         LAYER metal3 ;
         RECT  1447.42 1.0375 1447.555 1.1725 ;
      END
   END din0[463]
   PIN din0[464]
      DIRECTION INPUT ;
      PORT
         LAYER metal3 ;
         RECT  1450.28 1.0375 1450.415 1.1725 ;
      END
   END din0[464]
   PIN din0[465]
      DIRECTION INPUT ;
      PORT
         LAYER metal3 ;
         RECT  1453.14 1.0375 1453.275 1.1725 ;
      END
   END din0[465]
   PIN din0[466]
      DIRECTION INPUT ;
      PORT
         LAYER metal3 ;
         RECT  1456.0 1.0375 1456.135 1.1725 ;
      END
   END din0[466]
   PIN din0[467]
      DIRECTION INPUT ;
      PORT
         LAYER metal3 ;
         RECT  1458.86 1.0375 1458.995 1.1725 ;
      END
   END din0[467]
   PIN din0[468]
      DIRECTION INPUT ;
      PORT
         LAYER metal3 ;
         RECT  1461.72 1.0375 1461.855 1.1725 ;
      END
   END din0[468]
   PIN din0[469]
      DIRECTION INPUT ;
      PORT
         LAYER metal3 ;
         RECT  1464.58 1.0375 1464.715 1.1725 ;
      END
   END din0[469]
   PIN din0[470]
      DIRECTION INPUT ;
      PORT
         LAYER metal3 ;
         RECT  1467.44 1.0375 1467.575 1.1725 ;
      END
   END din0[470]
   PIN din0[471]
      DIRECTION INPUT ;
      PORT
         LAYER metal3 ;
         RECT  1470.3 1.0375 1470.435 1.1725 ;
      END
   END din0[471]
   PIN din0[472]
      DIRECTION INPUT ;
      PORT
         LAYER metal3 ;
         RECT  1473.16 1.0375 1473.295 1.1725 ;
      END
   END din0[472]
   PIN din0[473]
      DIRECTION INPUT ;
      PORT
         LAYER metal3 ;
         RECT  1476.02 1.0375 1476.155 1.1725 ;
      END
   END din0[473]
   PIN din0[474]
      DIRECTION INPUT ;
      PORT
         LAYER metal3 ;
         RECT  1478.88 1.0375 1479.015 1.1725 ;
      END
   END din0[474]
   PIN din0[475]
      DIRECTION INPUT ;
      PORT
         LAYER metal3 ;
         RECT  1481.74 1.0375 1481.875 1.1725 ;
      END
   END din0[475]
   PIN din0[476]
      DIRECTION INPUT ;
      PORT
         LAYER metal3 ;
         RECT  1484.6 1.0375 1484.735 1.1725 ;
      END
   END din0[476]
   PIN din0[477]
      DIRECTION INPUT ;
      PORT
         LAYER metal3 ;
         RECT  1487.46 1.0375 1487.595 1.1725 ;
      END
   END din0[477]
   PIN din0[478]
      DIRECTION INPUT ;
      PORT
         LAYER metal3 ;
         RECT  1490.32 1.0375 1490.455 1.1725 ;
      END
   END din0[478]
   PIN din0[479]
      DIRECTION INPUT ;
      PORT
         LAYER metal3 ;
         RECT  1493.18 1.0375 1493.315 1.1725 ;
      END
   END din0[479]
   PIN din0[480]
      DIRECTION INPUT ;
      PORT
         LAYER metal3 ;
         RECT  1496.04 1.0375 1496.175 1.1725 ;
      END
   END din0[480]
   PIN din0[481]
      DIRECTION INPUT ;
      PORT
         LAYER metal3 ;
         RECT  1498.9 1.0375 1499.035 1.1725 ;
      END
   END din0[481]
   PIN din0[482]
      DIRECTION INPUT ;
      PORT
         LAYER metal3 ;
         RECT  1501.76 1.0375 1501.895 1.1725 ;
      END
   END din0[482]
   PIN din0[483]
      DIRECTION INPUT ;
      PORT
         LAYER metal3 ;
         RECT  1504.62 1.0375 1504.755 1.1725 ;
      END
   END din0[483]
   PIN din0[484]
      DIRECTION INPUT ;
      PORT
         LAYER metal3 ;
         RECT  1507.48 1.0375 1507.615 1.1725 ;
      END
   END din0[484]
   PIN din0[485]
      DIRECTION INPUT ;
      PORT
         LAYER metal3 ;
         RECT  1510.34 1.0375 1510.475 1.1725 ;
      END
   END din0[485]
   PIN din0[486]
      DIRECTION INPUT ;
      PORT
         LAYER metal3 ;
         RECT  1513.2 1.0375 1513.335 1.1725 ;
      END
   END din0[486]
   PIN din0[487]
      DIRECTION INPUT ;
      PORT
         LAYER metal3 ;
         RECT  1516.06 1.0375 1516.195 1.1725 ;
      END
   END din0[487]
   PIN din0[488]
      DIRECTION INPUT ;
      PORT
         LAYER metal3 ;
         RECT  1518.92 1.0375 1519.055 1.1725 ;
      END
   END din0[488]
   PIN din0[489]
      DIRECTION INPUT ;
      PORT
         LAYER metal3 ;
         RECT  1521.78 1.0375 1521.915 1.1725 ;
      END
   END din0[489]
   PIN din0[490]
      DIRECTION INPUT ;
      PORT
         LAYER metal3 ;
         RECT  1524.64 1.0375 1524.775 1.1725 ;
      END
   END din0[490]
   PIN din0[491]
      DIRECTION INPUT ;
      PORT
         LAYER metal3 ;
         RECT  1527.5 1.0375 1527.635 1.1725 ;
      END
   END din0[491]
   PIN din0[492]
      DIRECTION INPUT ;
      PORT
         LAYER metal3 ;
         RECT  1530.36 1.0375 1530.495 1.1725 ;
      END
   END din0[492]
   PIN din0[493]
      DIRECTION INPUT ;
      PORT
         LAYER metal3 ;
         RECT  1533.22 1.0375 1533.355 1.1725 ;
      END
   END din0[493]
   PIN din0[494]
      DIRECTION INPUT ;
      PORT
         LAYER metal3 ;
         RECT  1536.08 1.0375 1536.215 1.1725 ;
      END
   END din0[494]
   PIN din0[495]
      DIRECTION INPUT ;
      PORT
         LAYER metal3 ;
         RECT  1538.94 1.0375 1539.075 1.1725 ;
      END
   END din0[495]
   PIN din0[496]
      DIRECTION INPUT ;
      PORT
         LAYER metal3 ;
         RECT  1541.8 1.0375 1541.935 1.1725 ;
      END
   END din0[496]
   PIN din0[497]
      DIRECTION INPUT ;
      PORT
         LAYER metal3 ;
         RECT  1544.66 1.0375 1544.795 1.1725 ;
      END
   END din0[497]
   PIN din0[498]
      DIRECTION INPUT ;
      PORT
         LAYER metal3 ;
         RECT  1547.52 1.0375 1547.655 1.1725 ;
      END
   END din0[498]
   PIN din0[499]
      DIRECTION INPUT ;
      PORT
         LAYER metal3 ;
         RECT  1550.38 1.0375 1550.515 1.1725 ;
      END
   END din0[499]
   PIN din0[500]
      DIRECTION INPUT ;
      PORT
         LAYER metal3 ;
         RECT  1553.24 1.0375 1553.375 1.1725 ;
      END
   END din0[500]
   PIN din0[501]
      DIRECTION INPUT ;
      PORT
         LAYER metal3 ;
         RECT  1556.1 1.0375 1556.235 1.1725 ;
      END
   END din0[501]
   PIN din0[502]
      DIRECTION INPUT ;
      PORT
         LAYER metal3 ;
         RECT  1558.96 1.0375 1559.095 1.1725 ;
      END
   END din0[502]
   PIN din0[503]
      DIRECTION INPUT ;
      PORT
         LAYER metal3 ;
         RECT  1561.82 1.0375 1561.955 1.1725 ;
      END
   END din0[503]
   PIN din0[504]
      DIRECTION INPUT ;
      PORT
         LAYER metal3 ;
         RECT  1564.68 1.0375 1564.815 1.1725 ;
      END
   END din0[504]
   PIN din0[505]
      DIRECTION INPUT ;
      PORT
         LAYER metal3 ;
         RECT  1567.54 1.0375 1567.675 1.1725 ;
      END
   END din0[505]
   PIN din0[506]
      DIRECTION INPUT ;
      PORT
         LAYER metal3 ;
         RECT  1570.4 1.0375 1570.535 1.1725 ;
      END
   END din0[506]
   PIN din0[507]
      DIRECTION INPUT ;
      PORT
         LAYER metal3 ;
         RECT  1573.26 1.0375 1573.395 1.1725 ;
      END
   END din0[507]
   PIN din0[508]
      DIRECTION INPUT ;
      PORT
         LAYER metal3 ;
         RECT  1576.12 1.0375 1576.255 1.1725 ;
      END
   END din0[508]
   PIN din0[509]
      DIRECTION INPUT ;
      PORT
         LAYER metal3 ;
         RECT  1578.98 1.0375 1579.115 1.1725 ;
      END
   END din0[509]
   PIN din0[510]
      DIRECTION INPUT ;
      PORT
         LAYER metal3 ;
         RECT  1581.84 1.0375 1581.975 1.1725 ;
      END
   END din0[510]
   PIN din0[511]
      DIRECTION INPUT ;
      PORT
         LAYER metal3 ;
         RECT  1584.7 1.0375 1584.835 1.1725 ;
      END
   END din0[511]
   PIN addr0[0]
      DIRECTION INPUT ;
      PORT
         LAYER metal3 ;
         RECT  117.52 131.2225 117.655 131.3575 ;
      END
   END addr0[0]
   PIN addr0[1]
      DIRECTION INPUT ;
      PORT
         LAYER metal3 ;
         RECT  117.52 133.9525 117.655 134.0875 ;
      END
   END addr0[1]
   PIN addr0[2]
      DIRECTION INPUT ;
      PORT
         LAYER metal3 ;
         RECT  117.52 136.1625 117.655 136.2975 ;
      END
   END addr0[2]
   PIN addr0[3]
      DIRECTION INPUT ;
      PORT
         LAYER metal3 ;
         RECT  117.52 138.8925 117.655 139.0275 ;
      END
   END addr0[3]
   PIN addr0[4]
      DIRECTION INPUT ;
      PORT
         LAYER metal3 ;
         RECT  117.52 141.1025 117.655 141.2375 ;
      END
   END addr0[4]
   PIN addr0[5]
      DIRECTION INPUT ;
      PORT
         LAYER metal3 ;
         RECT  117.52 143.8325 117.655 143.9675 ;
      END
   END addr0[5]
   PIN addr0[6]
      DIRECTION INPUT ;
      PORT
         LAYER metal3 ;
         RECT  117.52 146.0425 117.655 146.1775 ;
      END
   END addr0[6]
   PIN addr0[7]
      DIRECTION INPUT ;
      PORT
         LAYER metal3 ;
         RECT  117.52 148.7725 117.655 148.9075 ;
      END
   END addr0[7]
   PIN addr1[0]
      DIRECTION INPUT ;
      PORT
         LAYER metal3 ;
         RECT  801.98 93.1325 802.115 93.2675 ;
      END
   END addr1[0]
   PIN addr1[1]
      DIRECTION INPUT ;
      PORT
         LAYER metal3 ;
         RECT  801.98 90.4025 802.115 90.5375 ;
      END
   END addr1[1]
   PIN addr1[2]
      DIRECTION INPUT ;
      PORT
         LAYER metal3 ;
         RECT  801.98 88.1925 802.115 88.3275 ;
      END
   END addr1[2]
   PIN addr1[3]
      DIRECTION INPUT ;
      PORT
         LAYER metal3 ;
         RECT  801.98 85.4625 802.115 85.5975 ;
      END
   END addr1[3]
   PIN addr1[4]
      DIRECTION INPUT ;
      PORT
         LAYER metal3 ;
         RECT  801.98 83.2525 802.115 83.3875 ;
      END
   END addr1[4]
   PIN addr1[5]
      DIRECTION INPUT ;
      PORT
         LAYER metal3 ;
         RECT  801.98 80.5225 802.115 80.6575 ;
      END
   END addr1[5]
   PIN addr1[6]
      DIRECTION INPUT ;
      PORT
         LAYER metal3 ;
         RECT  801.98 78.3125 802.115 78.4475 ;
      END
   END addr1[6]
   PIN addr1[7]
      DIRECTION INPUT ;
      PORT
         LAYER metal3 ;
         RECT  801.98 75.5825 802.115 75.7175 ;
      END
   END addr1[7]
   PIN csb0
      DIRECTION INPUT ;
      PORT
         LAYER metal3 ;
         RECT  0.285 74.3625 0.42 74.4975 ;
      END
   END csb0
   PIN csb1
      DIRECTION INPUT ;
      PORT
         LAYER metal3 ;
         RECT  919.215 494.3625 919.35 494.4975 ;
      END
   END csb1
   PIN clk0
      DIRECTION INPUT ;
      PORT
         LAYER metal3 ;
         RECT  6.2475 74.4475 6.3825 74.5825 ;
      END
   END clk0
   PIN clk1
      DIRECTION INPUT ;
      PORT
         LAYER metal3 ;
         RECT  913.2525 494.2775 913.3875 494.4125 ;
      END
   END clk1
   PIN dout1[0]
      DIRECTION OUTPUT ;
      PORT
         LAYER metal3 ;
         RECT  158.88 488.16 159.015 488.295 ;
      END
   END dout1[0]
   PIN dout1[1]
      DIRECTION OUTPUT ;
      PORT
         LAYER metal3 ;
         RECT  160.055 488.16 160.19 488.295 ;
      END
   END dout1[1]
   PIN dout1[2]
      DIRECTION OUTPUT ;
      PORT
         LAYER metal3 ;
         RECT  161.23 488.16 161.365 488.295 ;
      END
   END dout1[2]
   PIN dout1[3]
      DIRECTION OUTPUT ;
      PORT
         LAYER metal3 ;
         RECT  162.405 488.16 162.54 488.295 ;
      END
   END dout1[3]
   PIN dout1[4]
      DIRECTION OUTPUT ;
      PORT
         LAYER metal3 ;
         RECT  163.58 488.16 163.715 488.295 ;
      END
   END dout1[4]
   PIN dout1[5]
      DIRECTION OUTPUT ;
      PORT
         LAYER metal3 ;
         RECT  164.755 488.16 164.89 488.295 ;
      END
   END dout1[5]
   PIN dout1[6]
      DIRECTION OUTPUT ;
      PORT
         LAYER metal3 ;
         RECT  165.93 488.16 166.065 488.295 ;
      END
   END dout1[6]
   PIN dout1[7]
      DIRECTION OUTPUT ;
      PORT
         LAYER metal3 ;
         RECT  167.105 488.16 167.24 488.295 ;
      END
   END dout1[7]
   PIN dout1[8]
      DIRECTION OUTPUT ;
      PORT
         LAYER metal3 ;
         RECT  168.28 488.16 168.415 488.295 ;
      END
   END dout1[8]
   PIN dout1[9]
      DIRECTION OUTPUT ;
      PORT
         LAYER metal3 ;
         RECT  169.455 488.16 169.59 488.295 ;
      END
   END dout1[9]
   PIN dout1[10]
      DIRECTION OUTPUT ;
      PORT
         LAYER metal3 ;
         RECT  170.63 488.16 170.765 488.295 ;
      END
   END dout1[10]
   PIN dout1[11]
      DIRECTION OUTPUT ;
      PORT
         LAYER metal3 ;
         RECT  171.805 488.16 171.94 488.295 ;
      END
   END dout1[11]
   PIN dout1[12]
      DIRECTION OUTPUT ;
      PORT
         LAYER metal3 ;
         RECT  172.98 488.16 173.115 488.295 ;
      END
   END dout1[12]
   PIN dout1[13]
      DIRECTION OUTPUT ;
      PORT
         LAYER metal3 ;
         RECT  174.155 488.16 174.29 488.295 ;
      END
   END dout1[13]
   PIN dout1[14]
      DIRECTION OUTPUT ;
      PORT
         LAYER metal3 ;
         RECT  175.33 488.16 175.465 488.295 ;
      END
   END dout1[14]
   PIN dout1[15]
      DIRECTION OUTPUT ;
      PORT
         LAYER metal3 ;
         RECT  176.505 488.16 176.64 488.295 ;
      END
   END dout1[15]
   PIN dout1[16]
      DIRECTION OUTPUT ;
      PORT
         LAYER metal3 ;
         RECT  177.68 488.16 177.815 488.295 ;
      END
   END dout1[16]
   PIN dout1[17]
      DIRECTION OUTPUT ;
      PORT
         LAYER metal3 ;
         RECT  178.855 488.16 178.99 488.295 ;
      END
   END dout1[17]
   PIN dout1[18]
      DIRECTION OUTPUT ;
      PORT
         LAYER metal3 ;
         RECT  180.03 488.16 180.165 488.295 ;
      END
   END dout1[18]
   PIN dout1[19]
      DIRECTION OUTPUT ;
      PORT
         LAYER metal3 ;
         RECT  181.205 488.16 181.34 488.295 ;
      END
   END dout1[19]
   PIN dout1[20]
      DIRECTION OUTPUT ;
      PORT
         LAYER metal3 ;
         RECT  182.38 488.16 182.515 488.295 ;
      END
   END dout1[20]
   PIN dout1[21]
      DIRECTION OUTPUT ;
      PORT
         LAYER metal3 ;
         RECT  183.555 488.16 183.69 488.295 ;
      END
   END dout1[21]
   PIN dout1[22]
      DIRECTION OUTPUT ;
      PORT
         LAYER metal3 ;
         RECT  184.73 488.16 184.865 488.295 ;
      END
   END dout1[22]
   PIN dout1[23]
      DIRECTION OUTPUT ;
      PORT
         LAYER metal3 ;
         RECT  185.905 488.16 186.04 488.295 ;
      END
   END dout1[23]
   PIN dout1[24]
      DIRECTION OUTPUT ;
      PORT
         LAYER metal3 ;
         RECT  187.08 488.16 187.215 488.295 ;
      END
   END dout1[24]
   PIN dout1[25]
      DIRECTION OUTPUT ;
      PORT
         LAYER metal3 ;
         RECT  188.255 488.16 188.39 488.295 ;
      END
   END dout1[25]
   PIN dout1[26]
      DIRECTION OUTPUT ;
      PORT
         LAYER metal3 ;
         RECT  189.43 488.16 189.565 488.295 ;
      END
   END dout1[26]
   PIN dout1[27]
      DIRECTION OUTPUT ;
      PORT
         LAYER metal3 ;
         RECT  190.605 488.16 190.74 488.295 ;
      END
   END dout1[27]
   PIN dout1[28]
      DIRECTION OUTPUT ;
      PORT
         LAYER metal3 ;
         RECT  191.78 488.16 191.915 488.295 ;
      END
   END dout1[28]
   PIN dout1[29]
      DIRECTION OUTPUT ;
      PORT
         LAYER metal3 ;
         RECT  192.955 488.16 193.09 488.295 ;
      END
   END dout1[29]
   PIN dout1[30]
      DIRECTION OUTPUT ;
      PORT
         LAYER metal3 ;
         RECT  194.13 488.16 194.265 488.295 ;
      END
   END dout1[30]
   PIN dout1[31]
      DIRECTION OUTPUT ;
      PORT
         LAYER metal3 ;
         RECT  195.305 488.16 195.44 488.295 ;
      END
   END dout1[31]
   PIN dout1[32]
      DIRECTION OUTPUT ;
      PORT
         LAYER metal3 ;
         RECT  196.48 488.16 196.615 488.295 ;
      END
   END dout1[32]
   PIN dout1[33]
      DIRECTION OUTPUT ;
      PORT
         LAYER metal3 ;
         RECT  197.655 488.16 197.79 488.295 ;
      END
   END dout1[33]
   PIN dout1[34]
      DIRECTION OUTPUT ;
      PORT
         LAYER metal3 ;
         RECT  198.83 488.16 198.965 488.295 ;
      END
   END dout1[34]
   PIN dout1[35]
      DIRECTION OUTPUT ;
      PORT
         LAYER metal3 ;
         RECT  200.005 488.16 200.14 488.295 ;
      END
   END dout1[35]
   PIN dout1[36]
      DIRECTION OUTPUT ;
      PORT
         LAYER metal3 ;
         RECT  201.18 488.16 201.315 488.295 ;
      END
   END dout1[36]
   PIN dout1[37]
      DIRECTION OUTPUT ;
      PORT
         LAYER metal3 ;
         RECT  202.355 488.16 202.49 488.295 ;
      END
   END dout1[37]
   PIN dout1[38]
      DIRECTION OUTPUT ;
      PORT
         LAYER metal3 ;
         RECT  203.53 488.16 203.665 488.295 ;
      END
   END dout1[38]
   PIN dout1[39]
      DIRECTION OUTPUT ;
      PORT
         LAYER metal3 ;
         RECT  204.705 488.16 204.84 488.295 ;
      END
   END dout1[39]
   PIN dout1[40]
      DIRECTION OUTPUT ;
      PORT
         LAYER metal3 ;
         RECT  205.88 488.16 206.015 488.295 ;
      END
   END dout1[40]
   PIN dout1[41]
      DIRECTION OUTPUT ;
      PORT
         LAYER metal3 ;
         RECT  207.055 488.16 207.19 488.295 ;
      END
   END dout1[41]
   PIN dout1[42]
      DIRECTION OUTPUT ;
      PORT
         LAYER metal3 ;
         RECT  208.23 488.16 208.365 488.295 ;
      END
   END dout1[42]
   PIN dout1[43]
      DIRECTION OUTPUT ;
      PORT
         LAYER metal3 ;
         RECT  209.405 488.16 209.54 488.295 ;
      END
   END dout1[43]
   PIN dout1[44]
      DIRECTION OUTPUT ;
      PORT
         LAYER metal3 ;
         RECT  210.58 488.16 210.715 488.295 ;
      END
   END dout1[44]
   PIN dout1[45]
      DIRECTION OUTPUT ;
      PORT
         LAYER metal3 ;
         RECT  211.755 488.16 211.89 488.295 ;
      END
   END dout1[45]
   PIN dout1[46]
      DIRECTION OUTPUT ;
      PORT
         LAYER metal3 ;
         RECT  212.93 488.16 213.065 488.295 ;
      END
   END dout1[46]
   PIN dout1[47]
      DIRECTION OUTPUT ;
      PORT
         LAYER metal3 ;
         RECT  214.105 488.16 214.24 488.295 ;
      END
   END dout1[47]
   PIN dout1[48]
      DIRECTION OUTPUT ;
      PORT
         LAYER metal3 ;
         RECT  215.28 488.16 215.415 488.295 ;
      END
   END dout1[48]
   PIN dout1[49]
      DIRECTION OUTPUT ;
      PORT
         LAYER metal3 ;
         RECT  216.455 488.16 216.59 488.295 ;
      END
   END dout1[49]
   PIN dout1[50]
      DIRECTION OUTPUT ;
      PORT
         LAYER metal3 ;
         RECT  217.63 488.16 217.765 488.295 ;
      END
   END dout1[50]
   PIN dout1[51]
      DIRECTION OUTPUT ;
      PORT
         LAYER metal3 ;
         RECT  218.805 488.16 218.94 488.295 ;
      END
   END dout1[51]
   PIN dout1[52]
      DIRECTION OUTPUT ;
      PORT
         LAYER metal3 ;
         RECT  219.98 488.16 220.115 488.295 ;
      END
   END dout1[52]
   PIN dout1[53]
      DIRECTION OUTPUT ;
      PORT
         LAYER metal3 ;
         RECT  221.155 488.16 221.29 488.295 ;
      END
   END dout1[53]
   PIN dout1[54]
      DIRECTION OUTPUT ;
      PORT
         LAYER metal3 ;
         RECT  222.33 488.16 222.465 488.295 ;
      END
   END dout1[54]
   PIN dout1[55]
      DIRECTION OUTPUT ;
      PORT
         LAYER metal3 ;
         RECT  223.505 488.16 223.64 488.295 ;
      END
   END dout1[55]
   PIN dout1[56]
      DIRECTION OUTPUT ;
      PORT
         LAYER metal3 ;
         RECT  224.68 488.16 224.815 488.295 ;
      END
   END dout1[56]
   PIN dout1[57]
      DIRECTION OUTPUT ;
      PORT
         LAYER metal3 ;
         RECT  225.855 488.16 225.99 488.295 ;
      END
   END dout1[57]
   PIN dout1[58]
      DIRECTION OUTPUT ;
      PORT
         LAYER metal3 ;
         RECT  227.03 488.16 227.165 488.295 ;
      END
   END dout1[58]
   PIN dout1[59]
      DIRECTION OUTPUT ;
      PORT
         LAYER metal3 ;
         RECT  228.205 488.16 228.34 488.295 ;
      END
   END dout1[59]
   PIN dout1[60]
      DIRECTION OUTPUT ;
      PORT
         LAYER metal3 ;
         RECT  229.38 488.16 229.515 488.295 ;
      END
   END dout1[60]
   PIN dout1[61]
      DIRECTION OUTPUT ;
      PORT
         LAYER metal3 ;
         RECT  230.555 488.16 230.69 488.295 ;
      END
   END dout1[61]
   PIN dout1[62]
      DIRECTION OUTPUT ;
      PORT
         LAYER metal3 ;
         RECT  231.73 488.16 231.865 488.295 ;
      END
   END dout1[62]
   PIN dout1[63]
      DIRECTION OUTPUT ;
      PORT
         LAYER metal3 ;
         RECT  232.905 488.16 233.04 488.295 ;
      END
   END dout1[63]
   PIN dout1[64]
      DIRECTION OUTPUT ;
      PORT
         LAYER metal3 ;
         RECT  234.08 488.16 234.215 488.295 ;
      END
   END dout1[64]
   PIN dout1[65]
      DIRECTION OUTPUT ;
      PORT
         LAYER metal3 ;
         RECT  235.255 488.16 235.39 488.295 ;
      END
   END dout1[65]
   PIN dout1[66]
      DIRECTION OUTPUT ;
      PORT
         LAYER metal3 ;
         RECT  236.43 488.16 236.565 488.295 ;
      END
   END dout1[66]
   PIN dout1[67]
      DIRECTION OUTPUT ;
      PORT
         LAYER metal3 ;
         RECT  237.605 488.16 237.74 488.295 ;
      END
   END dout1[67]
   PIN dout1[68]
      DIRECTION OUTPUT ;
      PORT
         LAYER metal3 ;
         RECT  238.78 488.16 238.915 488.295 ;
      END
   END dout1[68]
   PIN dout1[69]
      DIRECTION OUTPUT ;
      PORT
         LAYER metal3 ;
         RECT  239.955 488.16 240.09 488.295 ;
      END
   END dout1[69]
   PIN dout1[70]
      DIRECTION OUTPUT ;
      PORT
         LAYER metal3 ;
         RECT  241.13 488.16 241.265 488.295 ;
      END
   END dout1[70]
   PIN dout1[71]
      DIRECTION OUTPUT ;
      PORT
         LAYER metal3 ;
         RECT  242.305 488.16 242.44 488.295 ;
      END
   END dout1[71]
   PIN dout1[72]
      DIRECTION OUTPUT ;
      PORT
         LAYER metal3 ;
         RECT  243.48 488.16 243.615 488.295 ;
      END
   END dout1[72]
   PIN dout1[73]
      DIRECTION OUTPUT ;
      PORT
         LAYER metal3 ;
         RECT  244.655 488.16 244.79 488.295 ;
      END
   END dout1[73]
   PIN dout1[74]
      DIRECTION OUTPUT ;
      PORT
         LAYER metal3 ;
         RECT  245.83 488.16 245.965 488.295 ;
      END
   END dout1[74]
   PIN dout1[75]
      DIRECTION OUTPUT ;
      PORT
         LAYER metal3 ;
         RECT  247.005 488.16 247.14 488.295 ;
      END
   END dout1[75]
   PIN dout1[76]
      DIRECTION OUTPUT ;
      PORT
         LAYER metal3 ;
         RECT  248.18 488.16 248.315 488.295 ;
      END
   END dout1[76]
   PIN dout1[77]
      DIRECTION OUTPUT ;
      PORT
         LAYER metal3 ;
         RECT  249.355 488.16 249.49 488.295 ;
      END
   END dout1[77]
   PIN dout1[78]
      DIRECTION OUTPUT ;
      PORT
         LAYER metal3 ;
         RECT  250.53 488.16 250.665 488.295 ;
      END
   END dout1[78]
   PIN dout1[79]
      DIRECTION OUTPUT ;
      PORT
         LAYER metal3 ;
         RECT  251.705 488.16 251.84 488.295 ;
      END
   END dout1[79]
   PIN dout1[80]
      DIRECTION OUTPUT ;
      PORT
         LAYER metal3 ;
         RECT  252.88 488.16 253.015 488.295 ;
      END
   END dout1[80]
   PIN dout1[81]
      DIRECTION OUTPUT ;
      PORT
         LAYER metal3 ;
         RECT  254.055 488.16 254.19 488.295 ;
      END
   END dout1[81]
   PIN dout1[82]
      DIRECTION OUTPUT ;
      PORT
         LAYER metal3 ;
         RECT  255.23 488.16 255.365 488.295 ;
      END
   END dout1[82]
   PIN dout1[83]
      DIRECTION OUTPUT ;
      PORT
         LAYER metal3 ;
         RECT  256.405 488.16 256.54 488.295 ;
      END
   END dout1[83]
   PIN dout1[84]
      DIRECTION OUTPUT ;
      PORT
         LAYER metal3 ;
         RECT  257.58 488.16 257.715 488.295 ;
      END
   END dout1[84]
   PIN dout1[85]
      DIRECTION OUTPUT ;
      PORT
         LAYER metal3 ;
         RECT  258.755 488.16 258.89 488.295 ;
      END
   END dout1[85]
   PIN dout1[86]
      DIRECTION OUTPUT ;
      PORT
         LAYER metal3 ;
         RECT  259.93 488.16 260.065 488.295 ;
      END
   END dout1[86]
   PIN dout1[87]
      DIRECTION OUTPUT ;
      PORT
         LAYER metal3 ;
         RECT  261.105 488.16 261.24 488.295 ;
      END
   END dout1[87]
   PIN dout1[88]
      DIRECTION OUTPUT ;
      PORT
         LAYER metal3 ;
         RECT  262.28 488.16 262.415 488.295 ;
      END
   END dout1[88]
   PIN dout1[89]
      DIRECTION OUTPUT ;
      PORT
         LAYER metal3 ;
         RECT  263.455 488.16 263.59 488.295 ;
      END
   END dout1[89]
   PIN dout1[90]
      DIRECTION OUTPUT ;
      PORT
         LAYER metal3 ;
         RECT  264.63 488.16 264.765 488.295 ;
      END
   END dout1[90]
   PIN dout1[91]
      DIRECTION OUTPUT ;
      PORT
         LAYER metal3 ;
         RECT  265.805 488.16 265.94 488.295 ;
      END
   END dout1[91]
   PIN dout1[92]
      DIRECTION OUTPUT ;
      PORT
         LAYER metal3 ;
         RECT  266.98 488.16 267.115 488.295 ;
      END
   END dout1[92]
   PIN dout1[93]
      DIRECTION OUTPUT ;
      PORT
         LAYER metal3 ;
         RECT  268.155 488.16 268.29 488.295 ;
      END
   END dout1[93]
   PIN dout1[94]
      DIRECTION OUTPUT ;
      PORT
         LAYER metal3 ;
         RECT  269.33 488.16 269.465 488.295 ;
      END
   END dout1[94]
   PIN dout1[95]
      DIRECTION OUTPUT ;
      PORT
         LAYER metal3 ;
         RECT  270.505 488.16 270.64 488.295 ;
      END
   END dout1[95]
   PIN dout1[96]
      DIRECTION OUTPUT ;
      PORT
         LAYER metal3 ;
         RECT  271.68 488.16 271.815 488.295 ;
      END
   END dout1[96]
   PIN dout1[97]
      DIRECTION OUTPUT ;
      PORT
         LAYER metal3 ;
         RECT  272.855 488.16 272.99 488.295 ;
      END
   END dout1[97]
   PIN dout1[98]
      DIRECTION OUTPUT ;
      PORT
         LAYER metal3 ;
         RECT  274.03 488.16 274.165 488.295 ;
      END
   END dout1[98]
   PIN dout1[99]
      DIRECTION OUTPUT ;
      PORT
         LAYER metal3 ;
         RECT  275.205 488.16 275.34 488.295 ;
      END
   END dout1[99]
   PIN dout1[100]
      DIRECTION OUTPUT ;
      PORT
         LAYER metal3 ;
         RECT  276.38 488.16 276.515 488.295 ;
      END
   END dout1[100]
   PIN dout1[101]
      DIRECTION OUTPUT ;
      PORT
         LAYER metal3 ;
         RECT  277.555 488.16 277.69 488.295 ;
      END
   END dout1[101]
   PIN dout1[102]
      DIRECTION OUTPUT ;
      PORT
         LAYER metal3 ;
         RECT  278.73 488.16 278.865 488.295 ;
      END
   END dout1[102]
   PIN dout1[103]
      DIRECTION OUTPUT ;
      PORT
         LAYER metal3 ;
         RECT  279.905 488.16 280.04 488.295 ;
      END
   END dout1[103]
   PIN dout1[104]
      DIRECTION OUTPUT ;
      PORT
         LAYER metal3 ;
         RECT  281.08 488.16 281.215 488.295 ;
      END
   END dout1[104]
   PIN dout1[105]
      DIRECTION OUTPUT ;
      PORT
         LAYER metal3 ;
         RECT  282.255 488.16 282.39 488.295 ;
      END
   END dout1[105]
   PIN dout1[106]
      DIRECTION OUTPUT ;
      PORT
         LAYER metal3 ;
         RECT  283.43 488.16 283.565 488.295 ;
      END
   END dout1[106]
   PIN dout1[107]
      DIRECTION OUTPUT ;
      PORT
         LAYER metal3 ;
         RECT  284.605 488.16 284.74 488.295 ;
      END
   END dout1[107]
   PIN dout1[108]
      DIRECTION OUTPUT ;
      PORT
         LAYER metal3 ;
         RECT  285.78 488.16 285.915 488.295 ;
      END
   END dout1[108]
   PIN dout1[109]
      DIRECTION OUTPUT ;
      PORT
         LAYER metal3 ;
         RECT  286.955 488.16 287.09 488.295 ;
      END
   END dout1[109]
   PIN dout1[110]
      DIRECTION OUTPUT ;
      PORT
         LAYER metal3 ;
         RECT  288.13 488.16 288.265 488.295 ;
      END
   END dout1[110]
   PIN dout1[111]
      DIRECTION OUTPUT ;
      PORT
         LAYER metal3 ;
         RECT  289.305 488.16 289.44 488.295 ;
      END
   END dout1[111]
   PIN dout1[112]
      DIRECTION OUTPUT ;
      PORT
         LAYER metal3 ;
         RECT  290.48 488.16 290.615 488.295 ;
      END
   END dout1[112]
   PIN dout1[113]
      DIRECTION OUTPUT ;
      PORT
         LAYER metal3 ;
         RECT  291.655 488.16 291.79 488.295 ;
      END
   END dout1[113]
   PIN dout1[114]
      DIRECTION OUTPUT ;
      PORT
         LAYER metal3 ;
         RECT  292.83 488.16 292.965 488.295 ;
      END
   END dout1[114]
   PIN dout1[115]
      DIRECTION OUTPUT ;
      PORT
         LAYER metal3 ;
         RECT  294.005 488.16 294.14 488.295 ;
      END
   END dout1[115]
   PIN dout1[116]
      DIRECTION OUTPUT ;
      PORT
         LAYER metal3 ;
         RECT  295.18 488.16 295.315 488.295 ;
      END
   END dout1[116]
   PIN dout1[117]
      DIRECTION OUTPUT ;
      PORT
         LAYER metal3 ;
         RECT  296.355 488.16 296.49 488.295 ;
      END
   END dout1[117]
   PIN dout1[118]
      DIRECTION OUTPUT ;
      PORT
         LAYER metal3 ;
         RECT  297.53 488.16 297.665 488.295 ;
      END
   END dout1[118]
   PIN dout1[119]
      DIRECTION OUTPUT ;
      PORT
         LAYER metal3 ;
         RECT  298.705 488.16 298.84 488.295 ;
      END
   END dout1[119]
   PIN dout1[120]
      DIRECTION OUTPUT ;
      PORT
         LAYER metal3 ;
         RECT  299.88 488.16 300.015 488.295 ;
      END
   END dout1[120]
   PIN dout1[121]
      DIRECTION OUTPUT ;
      PORT
         LAYER metal3 ;
         RECT  301.055 488.16 301.19 488.295 ;
      END
   END dout1[121]
   PIN dout1[122]
      DIRECTION OUTPUT ;
      PORT
         LAYER metal3 ;
         RECT  302.23 488.16 302.365 488.295 ;
      END
   END dout1[122]
   PIN dout1[123]
      DIRECTION OUTPUT ;
      PORT
         LAYER metal3 ;
         RECT  303.405 488.16 303.54 488.295 ;
      END
   END dout1[123]
   PIN dout1[124]
      DIRECTION OUTPUT ;
      PORT
         LAYER metal3 ;
         RECT  304.58 488.16 304.715 488.295 ;
      END
   END dout1[124]
   PIN dout1[125]
      DIRECTION OUTPUT ;
      PORT
         LAYER metal3 ;
         RECT  305.755 488.16 305.89 488.295 ;
      END
   END dout1[125]
   PIN dout1[126]
      DIRECTION OUTPUT ;
      PORT
         LAYER metal3 ;
         RECT  306.93 488.16 307.065 488.295 ;
      END
   END dout1[126]
   PIN dout1[127]
      DIRECTION OUTPUT ;
      PORT
         LAYER metal3 ;
         RECT  308.105 488.16 308.24 488.295 ;
      END
   END dout1[127]
   PIN dout1[128]
      DIRECTION OUTPUT ;
      PORT
         LAYER metal3 ;
         RECT  309.28 488.16 309.415 488.295 ;
      END
   END dout1[128]
   PIN dout1[129]
      DIRECTION OUTPUT ;
      PORT
         LAYER metal3 ;
         RECT  310.455 488.16 310.59 488.295 ;
      END
   END dout1[129]
   PIN dout1[130]
      DIRECTION OUTPUT ;
      PORT
         LAYER metal3 ;
         RECT  311.63 488.16 311.765 488.295 ;
      END
   END dout1[130]
   PIN dout1[131]
      DIRECTION OUTPUT ;
      PORT
         LAYER metal3 ;
         RECT  312.805 488.16 312.94 488.295 ;
      END
   END dout1[131]
   PIN dout1[132]
      DIRECTION OUTPUT ;
      PORT
         LAYER metal3 ;
         RECT  313.98 488.16 314.115 488.295 ;
      END
   END dout1[132]
   PIN dout1[133]
      DIRECTION OUTPUT ;
      PORT
         LAYER metal3 ;
         RECT  315.155 488.16 315.29 488.295 ;
      END
   END dout1[133]
   PIN dout1[134]
      DIRECTION OUTPUT ;
      PORT
         LAYER metal3 ;
         RECT  316.33 488.16 316.465 488.295 ;
      END
   END dout1[134]
   PIN dout1[135]
      DIRECTION OUTPUT ;
      PORT
         LAYER metal3 ;
         RECT  317.505 488.16 317.64 488.295 ;
      END
   END dout1[135]
   PIN dout1[136]
      DIRECTION OUTPUT ;
      PORT
         LAYER metal3 ;
         RECT  318.68 488.16 318.815 488.295 ;
      END
   END dout1[136]
   PIN dout1[137]
      DIRECTION OUTPUT ;
      PORT
         LAYER metal3 ;
         RECT  319.855 488.16 319.99 488.295 ;
      END
   END dout1[137]
   PIN dout1[138]
      DIRECTION OUTPUT ;
      PORT
         LAYER metal3 ;
         RECT  321.03 488.16 321.165 488.295 ;
      END
   END dout1[138]
   PIN dout1[139]
      DIRECTION OUTPUT ;
      PORT
         LAYER metal3 ;
         RECT  322.205 488.16 322.34 488.295 ;
      END
   END dout1[139]
   PIN dout1[140]
      DIRECTION OUTPUT ;
      PORT
         LAYER metal3 ;
         RECT  323.38 488.16 323.515 488.295 ;
      END
   END dout1[140]
   PIN dout1[141]
      DIRECTION OUTPUT ;
      PORT
         LAYER metal3 ;
         RECT  324.555 488.16 324.69 488.295 ;
      END
   END dout1[141]
   PIN dout1[142]
      DIRECTION OUTPUT ;
      PORT
         LAYER metal3 ;
         RECT  325.73 488.16 325.865 488.295 ;
      END
   END dout1[142]
   PIN dout1[143]
      DIRECTION OUTPUT ;
      PORT
         LAYER metal3 ;
         RECT  326.905 488.16 327.04 488.295 ;
      END
   END dout1[143]
   PIN dout1[144]
      DIRECTION OUTPUT ;
      PORT
         LAYER metal3 ;
         RECT  328.08 488.16 328.215 488.295 ;
      END
   END dout1[144]
   PIN dout1[145]
      DIRECTION OUTPUT ;
      PORT
         LAYER metal3 ;
         RECT  329.255 488.16 329.39 488.295 ;
      END
   END dout1[145]
   PIN dout1[146]
      DIRECTION OUTPUT ;
      PORT
         LAYER metal3 ;
         RECT  330.43 488.16 330.565 488.295 ;
      END
   END dout1[146]
   PIN dout1[147]
      DIRECTION OUTPUT ;
      PORT
         LAYER metal3 ;
         RECT  331.605 488.16 331.74 488.295 ;
      END
   END dout1[147]
   PIN dout1[148]
      DIRECTION OUTPUT ;
      PORT
         LAYER metal3 ;
         RECT  332.78 488.16 332.915 488.295 ;
      END
   END dout1[148]
   PIN dout1[149]
      DIRECTION OUTPUT ;
      PORT
         LAYER metal3 ;
         RECT  333.955 488.16 334.09 488.295 ;
      END
   END dout1[149]
   PIN dout1[150]
      DIRECTION OUTPUT ;
      PORT
         LAYER metal3 ;
         RECT  335.13 488.16 335.265 488.295 ;
      END
   END dout1[150]
   PIN dout1[151]
      DIRECTION OUTPUT ;
      PORT
         LAYER metal3 ;
         RECT  336.305 488.16 336.44 488.295 ;
      END
   END dout1[151]
   PIN dout1[152]
      DIRECTION OUTPUT ;
      PORT
         LAYER metal3 ;
         RECT  337.48 488.16 337.615 488.295 ;
      END
   END dout1[152]
   PIN dout1[153]
      DIRECTION OUTPUT ;
      PORT
         LAYER metal3 ;
         RECT  338.655 488.16 338.79 488.295 ;
      END
   END dout1[153]
   PIN dout1[154]
      DIRECTION OUTPUT ;
      PORT
         LAYER metal3 ;
         RECT  339.83 488.16 339.965 488.295 ;
      END
   END dout1[154]
   PIN dout1[155]
      DIRECTION OUTPUT ;
      PORT
         LAYER metal3 ;
         RECT  341.005 488.16 341.14 488.295 ;
      END
   END dout1[155]
   PIN dout1[156]
      DIRECTION OUTPUT ;
      PORT
         LAYER metal3 ;
         RECT  342.18 488.16 342.315 488.295 ;
      END
   END dout1[156]
   PIN dout1[157]
      DIRECTION OUTPUT ;
      PORT
         LAYER metal3 ;
         RECT  343.355 488.16 343.49 488.295 ;
      END
   END dout1[157]
   PIN dout1[158]
      DIRECTION OUTPUT ;
      PORT
         LAYER metal3 ;
         RECT  344.53 488.16 344.665 488.295 ;
      END
   END dout1[158]
   PIN dout1[159]
      DIRECTION OUTPUT ;
      PORT
         LAYER metal3 ;
         RECT  345.705 488.16 345.84 488.295 ;
      END
   END dout1[159]
   PIN dout1[160]
      DIRECTION OUTPUT ;
      PORT
         LAYER metal3 ;
         RECT  346.88 488.16 347.015 488.295 ;
      END
   END dout1[160]
   PIN dout1[161]
      DIRECTION OUTPUT ;
      PORT
         LAYER metal3 ;
         RECT  348.055 488.16 348.19 488.295 ;
      END
   END dout1[161]
   PIN dout1[162]
      DIRECTION OUTPUT ;
      PORT
         LAYER metal3 ;
         RECT  349.23 488.16 349.365 488.295 ;
      END
   END dout1[162]
   PIN dout1[163]
      DIRECTION OUTPUT ;
      PORT
         LAYER metal3 ;
         RECT  350.405 488.16 350.54 488.295 ;
      END
   END dout1[163]
   PIN dout1[164]
      DIRECTION OUTPUT ;
      PORT
         LAYER metal3 ;
         RECT  351.58 488.16 351.715 488.295 ;
      END
   END dout1[164]
   PIN dout1[165]
      DIRECTION OUTPUT ;
      PORT
         LAYER metal3 ;
         RECT  352.755 488.16 352.89 488.295 ;
      END
   END dout1[165]
   PIN dout1[166]
      DIRECTION OUTPUT ;
      PORT
         LAYER metal3 ;
         RECT  353.93 488.16 354.065 488.295 ;
      END
   END dout1[166]
   PIN dout1[167]
      DIRECTION OUTPUT ;
      PORT
         LAYER metal3 ;
         RECT  355.105 488.16 355.24 488.295 ;
      END
   END dout1[167]
   PIN dout1[168]
      DIRECTION OUTPUT ;
      PORT
         LAYER metal3 ;
         RECT  356.28 488.16 356.415 488.295 ;
      END
   END dout1[168]
   PIN dout1[169]
      DIRECTION OUTPUT ;
      PORT
         LAYER metal3 ;
         RECT  357.455 488.16 357.59 488.295 ;
      END
   END dout1[169]
   PIN dout1[170]
      DIRECTION OUTPUT ;
      PORT
         LAYER metal3 ;
         RECT  358.63 488.16 358.765 488.295 ;
      END
   END dout1[170]
   PIN dout1[171]
      DIRECTION OUTPUT ;
      PORT
         LAYER metal3 ;
         RECT  359.805 488.16 359.94 488.295 ;
      END
   END dout1[171]
   PIN dout1[172]
      DIRECTION OUTPUT ;
      PORT
         LAYER metal3 ;
         RECT  360.98 488.16 361.115 488.295 ;
      END
   END dout1[172]
   PIN dout1[173]
      DIRECTION OUTPUT ;
      PORT
         LAYER metal3 ;
         RECT  362.155 488.16 362.29 488.295 ;
      END
   END dout1[173]
   PIN dout1[174]
      DIRECTION OUTPUT ;
      PORT
         LAYER metal3 ;
         RECT  363.33 488.16 363.465 488.295 ;
      END
   END dout1[174]
   PIN dout1[175]
      DIRECTION OUTPUT ;
      PORT
         LAYER metal3 ;
         RECT  364.505 488.16 364.64 488.295 ;
      END
   END dout1[175]
   PIN dout1[176]
      DIRECTION OUTPUT ;
      PORT
         LAYER metal3 ;
         RECT  365.68 488.16 365.815 488.295 ;
      END
   END dout1[176]
   PIN dout1[177]
      DIRECTION OUTPUT ;
      PORT
         LAYER metal3 ;
         RECT  366.855 488.16 366.99 488.295 ;
      END
   END dout1[177]
   PIN dout1[178]
      DIRECTION OUTPUT ;
      PORT
         LAYER metal3 ;
         RECT  368.03 488.16 368.165 488.295 ;
      END
   END dout1[178]
   PIN dout1[179]
      DIRECTION OUTPUT ;
      PORT
         LAYER metal3 ;
         RECT  369.205 488.16 369.34 488.295 ;
      END
   END dout1[179]
   PIN dout1[180]
      DIRECTION OUTPUT ;
      PORT
         LAYER metal3 ;
         RECT  370.38 488.16 370.515 488.295 ;
      END
   END dout1[180]
   PIN dout1[181]
      DIRECTION OUTPUT ;
      PORT
         LAYER metal3 ;
         RECT  371.555 488.16 371.69 488.295 ;
      END
   END dout1[181]
   PIN dout1[182]
      DIRECTION OUTPUT ;
      PORT
         LAYER metal3 ;
         RECT  372.73 488.16 372.865 488.295 ;
      END
   END dout1[182]
   PIN dout1[183]
      DIRECTION OUTPUT ;
      PORT
         LAYER metal3 ;
         RECT  373.905 488.16 374.04 488.295 ;
      END
   END dout1[183]
   PIN dout1[184]
      DIRECTION OUTPUT ;
      PORT
         LAYER metal3 ;
         RECT  375.08 488.16 375.215 488.295 ;
      END
   END dout1[184]
   PIN dout1[185]
      DIRECTION OUTPUT ;
      PORT
         LAYER metal3 ;
         RECT  376.255 488.16 376.39 488.295 ;
      END
   END dout1[185]
   PIN dout1[186]
      DIRECTION OUTPUT ;
      PORT
         LAYER metal3 ;
         RECT  377.43 488.16 377.565 488.295 ;
      END
   END dout1[186]
   PIN dout1[187]
      DIRECTION OUTPUT ;
      PORT
         LAYER metal3 ;
         RECT  378.605 488.16 378.74 488.295 ;
      END
   END dout1[187]
   PIN dout1[188]
      DIRECTION OUTPUT ;
      PORT
         LAYER metal3 ;
         RECT  379.78 488.16 379.915 488.295 ;
      END
   END dout1[188]
   PIN dout1[189]
      DIRECTION OUTPUT ;
      PORT
         LAYER metal3 ;
         RECT  380.955 488.16 381.09 488.295 ;
      END
   END dout1[189]
   PIN dout1[190]
      DIRECTION OUTPUT ;
      PORT
         LAYER metal3 ;
         RECT  382.13 488.16 382.265 488.295 ;
      END
   END dout1[190]
   PIN dout1[191]
      DIRECTION OUTPUT ;
      PORT
         LAYER metal3 ;
         RECT  383.305 488.16 383.44 488.295 ;
      END
   END dout1[191]
   PIN dout1[192]
      DIRECTION OUTPUT ;
      PORT
         LAYER metal3 ;
         RECT  384.48 488.16 384.615 488.295 ;
      END
   END dout1[192]
   PIN dout1[193]
      DIRECTION OUTPUT ;
      PORT
         LAYER metal3 ;
         RECT  385.655 488.16 385.79 488.295 ;
      END
   END dout1[193]
   PIN dout1[194]
      DIRECTION OUTPUT ;
      PORT
         LAYER metal3 ;
         RECT  386.83 488.16 386.965 488.295 ;
      END
   END dout1[194]
   PIN dout1[195]
      DIRECTION OUTPUT ;
      PORT
         LAYER metal3 ;
         RECT  388.005 488.16 388.14 488.295 ;
      END
   END dout1[195]
   PIN dout1[196]
      DIRECTION OUTPUT ;
      PORT
         LAYER metal3 ;
         RECT  389.18 488.16 389.315 488.295 ;
      END
   END dout1[196]
   PIN dout1[197]
      DIRECTION OUTPUT ;
      PORT
         LAYER metal3 ;
         RECT  390.355 488.16 390.49 488.295 ;
      END
   END dout1[197]
   PIN dout1[198]
      DIRECTION OUTPUT ;
      PORT
         LAYER metal3 ;
         RECT  391.53 488.16 391.665 488.295 ;
      END
   END dout1[198]
   PIN dout1[199]
      DIRECTION OUTPUT ;
      PORT
         LAYER metal3 ;
         RECT  392.705 488.16 392.84 488.295 ;
      END
   END dout1[199]
   PIN dout1[200]
      DIRECTION OUTPUT ;
      PORT
         LAYER metal3 ;
         RECT  393.88 488.16 394.015 488.295 ;
      END
   END dout1[200]
   PIN dout1[201]
      DIRECTION OUTPUT ;
      PORT
         LAYER metal3 ;
         RECT  395.055 488.16 395.19 488.295 ;
      END
   END dout1[201]
   PIN dout1[202]
      DIRECTION OUTPUT ;
      PORT
         LAYER metal3 ;
         RECT  396.23 488.16 396.365 488.295 ;
      END
   END dout1[202]
   PIN dout1[203]
      DIRECTION OUTPUT ;
      PORT
         LAYER metal3 ;
         RECT  397.405 488.16 397.54 488.295 ;
      END
   END dout1[203]
   PIN dout1[204]
      DIRECTION OUTPUT ;
      PORT
         LAYER metal3 ;
         RECT  398.58 488.16 398.715 488.295 ;
      END
   END dout1[204]
   PIN dout1[205]
      DIRECTION OUTPUT ;
      PORT
         LAYER metal3 ;
         RECT  399.755 488.16 399.89 488.295 ;
      END
   END dout1[205]
   PIN dout1[206]
      DIRECTION OUTPUT ;
      PORT
         LAYER metal3 ;
         RECT  400.93 488.16 401.065 488.295 ;
      END
   END dout1[206]
   PIN dout1[207]
      DIRECTION OUTPUT ;
      PORT
         LAYER metal3 ;
         RECT  402.105 488.16 402.24 488.295 ;
      END
   END dout1[207]
   PIN dout1[208]
      DIRECTION OUTPUT ;
      PORT
         LAYER metal3 ;
         RECT  403.28 488.16 403.415 488.295 ;
      END
   END dout1[208]
   PIN dout1[209]
      DIRECTION OUTPUT ;
      PORT
         LAYER metal3 ;
         RECT  404.455 488.16 404.59 488.295 ;
      END
   END dout1[209]
   PIN dout1[210]
      DIRECTION OUTPUT ;
      PORT
         LAYER metal3 ;
         RECT  405.63 488.16 405.765 488.295 ;
      END
   END dout1[210]
   PIN dout1[211]
      DIRECTION OUTPUT ;
      PORT
         LAYER metal3 ;
         RECT  406.805 488.16 406.94 488.295 ;
      END
   END dout1[211]
   PIN dout1[212]
      DIRECTION OUTPUT ;
      PORT
         LAYER metal3 ;
         RECT  407.98 488.16 408.115 488.295 ;
      END
   END dout1[212]
   PIN dout1[213]
      DIRECTION OUTPUT ;
      PORT
         LAYER metal3 ;
         RECT  409.155 488.16 409.29 488.295 ;
      END
   END dout1[213]
   PIN dout1[214]
      DIRECTION OUTPUT ;
      PORT
         LAYER metal3 ;
         RECT  410.33 488.16 410.465 488.295 ;
      END
   END dout1[214]
   PIN dout1[215]
      DIRECTION OUTPUT ;
      PORT
         LAYER metal3 ;
         RECT  411.505 488.16 411.64 488.295 ;
      END
   END dout1[215]
   PIN dout1[216]
      DIRECTION OUTPUT ;
      PORT
         LAYER metal3 ;
         RECT  412.68 488.16 412.815 488.295 ;
      END
   END dout1[216]
   PIN dout1[217]
      DIRECTION OUTPUT ;
      PORT
         LAYER metal3 ;
         RECT  413.855 488.16 413.99 488.295 ;
      END
   END dout1[217]
   PIN dout1[218]
      DIRECTION OUTPUT ;
      PORT
         LAYER metal3 ;
         RECT  415.03 488.16 415.165 488.295 ;
      END
   END dout1[218]
   PIN dout1[219]
      DIRECTION OUTPUT ;
      PORT
         LAYER metal3 ;
         RECT  416.205 488.16 416.34 488.295 ;
      END
   END dout1[219]
   PIN dout1[220]
      DIRECTION OUTPUT ;
      PORT
         LAYER metal3 ;
         RECT  417.38 488.16 417.515 488.295 ;
      END
   END dout1[220]
   PIN dout1[221]
      DIRECTION OUTPUT ;
      PORT
         LAYER metal3 ;
         RECT  418.555 488.16 418.69 488.295 ;
      END
   END dout1[221]
   PIN dout1[222]
      DIRECTION OUTPUT ;
      PORT
         LAYER metal3 ;
         RECT  419.73 488.16 419.865 488.295 ;
      END
   END dout1[222]
   PIN dout1[223]
      DIRECTION OUTPUT ;
      PORT
         LAYER metal3 ;
         RECT  420.905 488.16 421.04 488.295 ;
      END
   END dout1[223]
   PIN dout1[224]
      DIRECTION OUTPUT ;
      PORT
         LAYER metal3 ;
         RECT  422.08 488.16 422.215 488.295 ;
      END
   END dout1[224]
   PIN dout1[225]
      DIRECTION OUTPUT ;
      PORT
         LAYER metal3 ;
         RECT  423.255 488.16 423.39 488.295 ;
      END
   END dout1[225]
   PIN dout1[226]
      DIRECTION OUTPUT ;
      PORT
         LAYER metal3 ;
         RECT  424.43 488.16 424.565 488.295 ;
      END
   END dout1[226]
   PIN dout1[227]
      DIRECTION OUTPUT ;
      PORT
         LAYER metal3 ;
         RECT  425.605 488.16 425.74 488.295 ;
      END
   END dout1[227]
   PIN dout1[228]
      DIRECTION OUTPUT ;
      PORT
         LAYER metal3 ;
         RECT  426.78 488.16 426.915 488.295 ;
      END
   END dout1[228]
   PIN dout1[229]
      DIRECTION OUTPUT ;
      PORT
         LAYER metal3 ;
         RECT  427.955 488.16 428.09 488.295 ;
      END
   END dout1[229]
   PIN dout1[230]
      DIRECTION OUTPUT ;
      PORT
         LAYER metal3 ;
         RECT  429.13 488.16 429.265 488.295 ;
      END
   END dout1[230]
   PIN dout1[231]
      DIRECTION OUTPUT ;
      PORT
         LAYER metal3 ;
         RECT  430.305 488.16 430.44 488.295 ;
      END
   END dout1[231]
   PIN dout1[232]
      DIRECTION OUTPUT ;
      PORT
         LAYER metal3 ;
         RECT  431.48 488.16 431.615 488.295 ;
      END
   END dout1[232]
   PIN dout1[233]
      DIRECTION OUTPUT ;
      PORT
         LAYER metal3 ;
         RECT  432.655 488.16 432.79 488.295 ;
      END
   END dout1[233]
   PIN dout1[234]
      DIRECTION OUTPUT ;
      PORT
         LAYER metal3 ;
         RECT  433.83 488.16 433.965 488.295 ;
      END
   END dout1[234]
   PIN dout1[235]
      DIRECTION OUTPUT ;
      PORT
         LAYER metal3 ;
         RECT  435.005 488.16 435.14 488.295 ;
      END
   END dout1[235]
   PIN dout1[236]
      DIRECTION OUTPUT ;
      PORT
         LAYER metal3 ;
         RECT  436.18 488.16 436.315 488.295 ;
      END
   END dout1[236]
   PIN dout1[237]
      DIRECTION OUTPUT ;
      PORT
         LAYER metal3 ;
         RECT  437.355 488.16 437.49 488.295 ;
      END
   END dout1[237]
   PIN dout1[238]
      DIRECTION OUTPUT ;
      PORT
         LAYER metal3 ;
         RECT  438.53 488.16 438.665 488.295 ;
      END
   END dout1[238]
   PIN dout1[239]
      DIRECTION OUTPUT ;
      PORT
         LAYER metal3 ;
         RECT  439.705 488.16 439.84 488.295 ;
      END
   END dout1[239]
   PIN dout1[240]
      DIRECTION OUTPUT ;
      PORT
         LAYER metal3 ;
         RECT  440.88 488.16 441.015 488.295 ;
      END
   END dout1[240]
   PIN dout1[241]
      DIRECTION OUTPUT ;
      PORT
         LAYER metal3 ;
         RECT  442.055 488.16 442.19 488.295 ;
      END
   END dout1[241]
   PIN dout1[242]
      DIRECTION OUTPUT ;
      PORT
         LAYER metal3 ;
         RECT  443.23 488.16 443.365 488.295 ;
      END
   END dout1[242]
   PIN dout1[243]
      DIRECTION OUTPUT ;
      PORT
         LAYER metal3 ;
         RECT  444.405 488.16 444.54 488.295 ;
      END
   END dout1[243]
   PIN dout1[244]
      DIRECTION OUTPUT ;
      PORT
         LAYER metal3 ;
         RECT  445.58 488.16 445.715 488.295 ;
      END
   END dout1[244]
   PIN dout1[245]
      DIRECTION OUTPUT ;
      PORT
         LAYER metal3 ;
         RECT  446.755 488.16 446.89 488.295 ;
      END
   END dout1[245]
   PIN dout1[246]
      DIRECTION OUTPUT ;
      PORT
         LAYER metal3 ;
         RECT  447.93 488.16 448.065 488.295 ;
      END
   END dout1[246]
   PIN dout1[247]
      DIRECTION OUTPUT ;
      PORT
         LAYER metal3 ;
         RECT  449.105 488.16 449.24 488.295 ;
      END
   END dout1[247]
   PIN dout1[248]
      DIRECTION OUTPUT ;
      PORT
         LAYER metal3 ;
         RECT  450.28 488.16 450.415 488.295 ;
      END
   END dout1[248]
   PIN dout1[249]
      DIRECTION OUTPUT ;
      PORT
         LAYER metal3 ;
         RECT  451.455 488.16 451.59 488.295 ;
      END
   END dout1[249]
   PIN dout1[250]
      DIRECTION OUTPUT ;
      PORT
         LAYER metal3 ;
         RECT  452.63 488.16 452.765 488.295 ;
      END
   END dout1[250]
   PIN dout1[251]
      DIRECTION OUTPUT ;
      PORT
         LAYER metal3 ;
         RECT  453.805 488.16 453.94 488.295 ;
      END
   END dout1[251]
   PIN dout1[252]
      DIRECTION OUTPUT ;
      PORT
         LAYER metal3 ;
         RECT  454.98 488.16 455.115 488.295 ;
      END
   END dout1[252]
   PIN dout1[253]
      DIRECTION OUTPUT ;
      PORT
         LAYER metal3 ;
         RECT  456.155 488.16 456.29 488.295 ;
      END
   END dout1[253]
   PIN dout1[254]
      DIRECTION OUTPUT ;
      PORT
         LAYER metal3 ;
         RECT  457.33 488.16 457.465 488.295 ;
      END
   END dout1[254]
   PIN dout1[255]
      DIRECTION OUTPUT ;
      PORT
         LAYER metal3 ;
         RECT  458.505 488.16 458.64 488.295 ;
      END
   END dout1[255]
   PIN dout1[256]
      DIRECTION OUTPUT ;
      PORT
         LAYER metal3 ;
         RECT  459.68 488.16 459.815 488.295 ;
      END
   END dout1[256]
   PIN dout1[257]
      DIRECTION OUTPUT ;
      PORT
         LAYER metal3 ;
         RECT  460.855 488.16 460.99 488.295 ;
      END
   END dout1[257]
   PIN dout1[258]
      DIRECTION OUTPUT ;
      PORT
         LAYER metal3 ;
         RECT  462.03 488.16 462.165 488.295 ;
      END
   END dout1[258]
   PIN dout1[259]
      DIRECTION OUTPUT ;
      PORT
         LAYER metal3 ;
         RECT  463.205 488.16 463.34 488.295 ;
      END
   END dout1[259]
   PIN dout1[260]
      DIRECTION OUTPUT ;
      PORT
         LAYER metal3 ;
         RECT  464.38 488.16 464.515 488.295 ;
      END
   END dout1[260]
   PIN dout1[261]
      DIRECTION OUTPUT ;
      PORT
         LAYER metal3 ;
         RECT  465.555 488.16 465.69 488.295 ;
      END
   END dout1[261]
   PIN dout1[262]
      DIRECTION OUTPUT ;
      PORT
         LAYER metal3 ;
         RECT  466.73 488.16 466.865 488.295 ;
      END
   END dout1[262]
   PIN dout1[263]
      DIRECTION OUTPUT ;
      PORT
         LAYER metal3 ;
         RECT  467.905 488.16 468.04 488.295 ;
      END
   END dout1[263]
   PIN dout1[264]
      DIRECTION OUTPUT ;
      PORT
         LAYER metal3 ;
         RECT  469.08 488.16 469.215 488.295 ;
      END
   END dout1[264]
   PIN dout1[265]
      DIRECTION OUTPUT ;
      PORT
         LAYER metal3 ;
         RECT  470.255 488.16 470.39 488.295 ;
      END
   END dout1[265]
   PIN dout1[266]
      DIRECTION OUTPUT ;
      PORT
         LAYER metal3 ;
         RECT  471.43 488.16 471.565 488.295 ;
      END
   END dout1[266]
   PIN dout1[267]
      DIRECTION OUTPUT ;
      PORT
         LAYER metal3 ;
         RECT  472.605 488.16 472.74 488.295 ;
      END
   END dout1[267]
   PIN dout1[268]
      DIRECTION OUTPUT ;
      PORT
         LAYER metal3 ;
         RECT  473.78 488.16 473.915 488.295 ;
      END
   END dout1[268]
   PIN dout1[269]
      DIRECTION OUTPUT ;
      PORT
         LAYER metal3 ;
         RECT  474.955 488.16 475.09 488.295 ;
      END
   END dout1[269]
   PIN dout1[270]
      DIRECTION OUTPUT ;
      PORT
         LAYER metal3 ;
         RECT  476.13 488.16 476.265 488.295 ;
      END
   END dout1[270]
   PIN dout1[271]
      DIRECTION OUTPUT ;
      PORT
         LAYER metal3 ;
         RECT  477.305 488.16 477.44 488.295 ;
      END
   END dout1[271]
   PIN dout1[272]
      DIRECTION OUTPUT ;
      PORT
         LAYER metal3 ;
         RECT  478.48 488.16 478.615 488.295 ;
      END
   END dout1[272]
   PIN dout1[273]
      DIRECTION OUTPUT ;
      PORT
         LAYER metal3 ;
         RECT  479.655 488.16 479.79 488.295 ;
      END
   END dout1[273]
   PIN dout1[274]
      DIRECTION OUTPUT ;
      PORT
         LAYER metal3 ;
         RECT  480.83 488.16 480.965 488.295 ;
      END
   END dout1[274]
   PIN dout1[275]
      DIRECTION OUTPUT ;
      PORT
         LAYER metal3 ;
         RECT  482.005 488.16 482.14 488.295 ;
      END
   END dout1[275]
   PIN dout1[276]
      DIRECTION OUTPUT ;
      PORT
         LAYER metal3 ;
         RECT  483.18 488.16 483.315 488.295 ;
      END
   END dout1[276]
   PIN dout1[277]
      DIRECTION OUTPUT ;
      PORT
         LAYER metal3 ;
         RECT  484.355 488.16 484.49 488.295 ;
      END
   END dout1[277]
   PIN dout1[278]
      DIRECTION OUTPUT ;
      PORT
         LAYER metal3 ;
         RECT  485.53 488.16 485.665 488.295 ;
      END
   END dout1[278]
   PIN dout1[279]
      DIRECTION OUTPUT ;
      PORT
         LAYER metal3 ;
         RECT  486.705 488.16 486.84 488.295 ;
      END
   END dout1[279]
   PIN dout1[280]
      DIRECTION OUTPUT ;
      PORT
         LAYER metal3 ;
         RECT  487.88 488.16 488.015 488.295 ;
      END
   END dout1[280]
   PIN dout1[281]
      DIRECTION OUTPUT ;
      PORT
         LAYER metal3 ;
         RECT  489.055 488.16 489.19 488.295 ;
      END
   END dout1[281]
   PIN dout1[282]
      DIRECTION OUTPUT ;
      PORT
         LAYER metal3 ;
         RECT  490.23 488.16 490.365 488.295 ;
      END
   END dout1[282]
   PIN dout1[283]
      DIRECTION OUTPUT ;
      PORT
         LAYER metal3 ;
         RECT  491.405 488.16 491.54 488.295 ;
      END
   END dout1[283]
   PIN dout1[284]
      DIRECTION OUTPUT ;
      PORT
         LAYER metal3 ;
         RECT  492.58 488.16 492.715 488.295 ;
      END
   END dout1[284]
   PIN dout1[285]
      DIRECTION OUTPUT ;
      PORT
         LAYER metal3 ;
         RECT  493.755 488.16 493.89 488.295 ;
      END
   END dout1[285]
   PIN dout1[286]
      DIRECTION OUTPUT ;
      PORT
         LAYER metal3 ;
         RECT  494.93 488.16 495.065 488.295 ;
      END
   END dout1[286]
   PIN dout1[287]
      DIRECTION OUTPUT ;
      PORT
         LAYER metal3 ;
         RECT  496.105 488.16 496.24 488.295 ;
      END
   END dout1[287]
   PIN dout1[288]
      DIRECTION OUTPUT ;
      PORT
         LAYER metal3 ;
         RECT  497.28 488.16 497.415 488.295 ;
      END
   END dout1[288]
   PIN dout1[289]
      DIRECTION OUTPUT ;
      PORT
         LAYER metal3 ;
         RECT  498.455 488.16 498.59 488.295 ;
      END
   END dout1[289]
   PIN dout1[290]
      DIRECTION OUTPUT ;
      PORT
         LAYER metal3 ;
         RECT  499.63 488.16 499.765 488.295 ;
      END
   END dout1[290]
   PIN dout1[291]
      DIRECTION OUTPUT ;
      PORT
         LAYER metal3 ;
         RECT  500.805 488.16 500.94 488.295 ;
      END
   END dout1[291]
   PIN dout1[292]
      DIRECTION OUTPUT ;
      PORT
         LAYER metal3 ;
         RECT  501.98 488.16 502.115 488.295 ;
      END
   END dout1[292]
   PIN dout1[293]
      DIRECTION OUTPUT ;
      PORT
         LAYER metal3 ;
         RECT  503.155 488.16 503.29 488.295 ;
      END
   END dout1[293]
   PIN dout1[294]
      DIRECTION OUTPUT ;
      PORT
         LAYER metal3 ;
         RECT  504.33 488.16 504.465 488.295 ;
      END
   END dout1[294]
   PIN dout1[295]
      DIRECTION OUTPUT ;
      PORT
         LAYER metal3 ;
         RECT  505.505 488.16 505.64 488.295 ;
      END
   END dout1[295]
   PIN dout1[296]
      DIRECTION OUTPUT ;
      PORT
         LAYER metal3 ;
         RECT  506.68 488.16 506.815 488.295 ;
      END
   END dout1[296]
   PIN dout1[297]
      DIRECTION OUTPUT ;
      PORT
         LAYER metal3 ;
         RECT  507.855 488.16 507.99 488.295 ;
      END
   END dout1[297]
   PIN dout1[298]
      DIRECTION OUTPUT ;
      PORT
         LAYER metal3 ;
         RECT  509.03 488.16 509.165 488.295 ;
      END
   END dout1[298]
   PIN dout1[299]
      DIRECTION OUTPUT ;
      PORT
         LAYER metal3 ;
         RECT  510.205 488.16 510.34 488.295 ;
      END
   END dout1[299]
   PIN dout1[300]
      DIRECTION OUTPUT ;
      PORT
         LAYER metal3 ;
         RECT  511.38 488.16 511.515 488.295 ;
      END
   END dout1[300]
   PIN dout1[301]
      DIRECTION OUTPUT ;
      PORT
         LAYER metal3 ;
         RECT  512.555 488.16 512.69 488.295 ;
      END
   END dout1[301]
   PIN dout1[302]
      DIRECTION OUTPUT ;
      PORT
         LAYER metal3 ;
         RECT  513.73 488.16 513.865 488.295 ;
      END
   END dout1[302]
   PIN dout1[303]
      DIRECTION OUTPUT ;
      PORT
         LAYER metal3 ;
         RECT  514.905 488.16 515.04 488.295 ;
      END
   END dout1[303]
   PIN dout1[304]
      DIRECTION OUTPUT ;
      PORT
         LAYER metal3 ;
         RECT  516.08 488.16 516.215 488.295 ;
      END
   END dout1[304]
   PIN dout1[305]
      DIRECTION OUTPUT ;
      PORT
         LAYER metal3 ;
         RECT  517.255 488.16 517.39 488.295 ;
      END
   END dout1[305]
   PIN dout1[306]
      DIRECTION OUTPUT ;
      PORT
         LAYER metal3 ;
         RECT  518.43 488.16 518.565 488.295 ;
      END
   END dout1[306]
   PIN dout1[307]
      DIRECTION OUTPUT ;
      PORT
         LAYER metal3 ;
         RECT  519.605 488.16 519.74 488.295 ;
      END
   END dout1[307]
   PIN dout1[308]
      DIRECTION OUTPUT ;
      PORT
         LAYER metal3 ;
         RECT  520.78 488.16 520.915 488.295 ;
      END
   END dout1[308]
   PIN dout1[309]
      DIRECTION OUTPUT ;
      PORT
         LAYER metal3 ;
         RECT  521.955 488.16 522.09 488.295 ;
      END
   END dout1[309]
   PIN dout1[310]
      DIRECTION OUTPUT ;
      PORT
         LAYER metal3 ;
         RECT  523.13 488.16 523.265 488.295 ;
      END
   END dout1[310]
   PIN dout1[311]
      DIRECTION OUTPUT ;
      PORT
         LAYER metal3 ;
         RECT  524.305 488.16 524.44 488.295 ;
      END
   END dout1[311]
   PIN dout1[312]
      DIRECTION OUTPUT ;
      PORT
         LAYER metal3 ;
         RECT  525.48 488.16 525.615 488.295 ;
      END
   END dout1[312]
   PIN dout1[313]
      DIRECTION OUTPUT ;
      PORT
         LAYER metal3 ;
         RECT  526.655 488.16 526.79 488.295 ;
      END
   END dout1[313]
   PIN dout1[314]
      DIRECTION OUTPUT ;
      PORT
         LAYER metal3 ;
         RECT  527.83 488.16 527.965 488.295 ;
      END
   END dout1[314]
   PIN dout1[315]
      DIRECTION OUTPUT ;
      PORT
         LAYER metal3 ;
         RECT  529.005 488.16 529.14 488.295 ;
      END
   END dout1[315]
   PIN dout1[316]
      DIRECTION OUTPUT ;
      PORT
         LAYER metal3 ;
         RECT  530.18 488.16 530.315 488.295 ;
      END
   END dout1[316]
   PIN dout1[317]
      DIRECTION OUTPUT ;
      PORT
         LAYER metal3 ;
         RECT  531.355 488.16 531.49 488.295 ;
      END
   END dout1[317]
   PIN dout1[318]
      DIRECTION OUTPUT ;
      PORT
         LAYER metal3 ;
         RECT  532.53 488.16 532.665 488.295 ;
      END
   END dout1[318]
   PIN dout1[319]
      DIRECTION OUTPUT ;
      PORT
         LAYER metal3 ;
         RECT  533.705 488.16 533.84 488.295 ;
      END
   END dout1[319]
   PIN dout1[320]
      DIRECTION OUTPUT ;
      PORT
         LAYER metal3 ;
         RECT  534.88 488.16 535.015 488.295 ;
      END
   END dout1[320]
   PIN dout1[321]
      DIRECTION OUTPUT ;
      PORT
         LAYER metal3 ;
         RECT  536.055 488.16 536.19 488.295 ;
      END
   END dout1[321]
   PIN dout1[322]
      DIRECTION OUTPUT ;
      PORT
         LAYER metal3 ;
         RECT  537.23 488.16 537.365 488.295 ;
      END
   END dout1[322]
   PIN dout1[323]
      DIRECTION OUTPUT ;
      PORT
         LAYER metal3 ;
         RECT  538.405 488.16 538.54 488.295 ;
      END
   END dout1[323]
   PIN dout1[324]
      DIRECTION OUTPUT ;
      PORT
         LAYER metal3 ;
         RECT  539.58 488.16 539.715 488.295 ;
      END
   END dout1[324]
   PIN dout1[325]
      DIRECTION OUTPUT ;
      PORT
         LAYER metal3 ;
         RECT  540.755 488.16 540.89 488.295 ;
      END
   END dout1[325]
   PIN dout1[326]
      DIRECTION OUTPUT ;
      PORT
         LAYER metal3 ;
         RECT  541.93 488.16 542.065 488.295 ;
      END
   END dout1[326]
   PIN dout1[327]
      DIRECTION OUTPUT ;
      PORT
         LAYER metal3 ;
         RECT  543.105 488.16 543.24 488.295 ;
      END
   END dout1[327]
   PIN dout1[328]
      DIRECTION OUTPUT ;
      PORT
         LAYER metal3 ;
         RECT  544.28 488.16 544.415 488.295 ;
      END
   END dout1[328]
   PIN dout1[329]
      DIRECTION OUTPUT ;
      PORT
         LAYER metal3 ;
         RECT  545.455 488.16 545.59 488.295 ;
      END
   END dout1[329]
   PIN dout1[330]
      DIRECTION OUTPUT ;
      PORT
         LAYER metal3 ;
         RECT  546.63 488.16 546.765 488.295 ;
      END
   END dout1[330]
   PIN dout1[331]
      DIRECTION OUTPUT ;
      PORT
         LAYER metal3 ;
         RECT  547.805 488.16 547.94 488.295 ;
      END
   END dout1[331]
   PIN dout1[332]
      DIRECTION OUTPUT ;
      PORT
         LAYER metal3 ;
         RECT  548.98 488.16 549.115 488.295 ;
      END
   END dout1[332]
   PIN dout1[333]
      DIRECTION OUTPUT ;
      PORT
         LAYER metal3 ;
         RECT  550.155 488.16 550.29 488.295 ;
      END
   END dout1[333]
   PIN dout1[334]
      DIRECTION OUTPUT ;
      PORT
         LAYER metal3 ;
         RECT  551.33 488.16 551.465 488.295 ;
      END
   END dout1[334]
   PIN dout1[335]
      DIRECTION OUTPUT ;
      PORT
         LAYER metal3 ;
         RECT  552.505 488.16 552.64 488.295 ;
      END
   END dout1[335]
   PIN dout1[336]
      DIRECTION OUTPUT ;
      PORT
         LAYER metal3 ;
         RECT  553.68 488.16 553.815 488.295 ;
      END
   END dout1[336]
   PIN dout1[337]
      DIRECTION OUTPUT ;
      PORT
         LAYER metal3 ;
         RECT  554.855 488.16 554.99 488.295 ;
      END
   END dout1[337]
   PIN dout1[338]
      DIRECTION OUTPUT ;
      PORT
         LAYER metal3 ;
         RECT  556.03 488.16 556.165 488.295 ;
      END
   END dout1[338]
   PIN dout1[339]
      DIRECTION OUTPUT ;
      PORT
         LAYER metal3 ;
         RECT  557.205 488.16 557.34 488.295 ;
      END
   END dout1[339]
   PIN dout1[340]
      DIRECTION OUTPUT ;
      PORT
         LAYER metal3 ;
         RECT  558.38 488.16 558.515 488.295 ;
      END
   END dout1[340]
   PIN dout1[341]
      DIRECTION OUTPUT ;
      PORT
         LAYER metal3 ;
         RECT  559.555 488.16 559.69 488.295 ;
      END
   END dout1[341]
   PIN dout1[342]
      DIRECTION OUTPUT ;
      PORT
         LAYER metal3 ;
         RECT  560.73 488.16 560.865 488.295 ;
      END
   END dout1[342]
   PIN dout1[343]
      DIRECTION OUTPUT ;
      PORT
         LAYER metal3 ;
         RECT  561.905 488.16 562.04 488.295 ;
      END
   END dout1[343]
   PIN dout1[344]
      DIRECTION OUTPUT ;
      PORT
         LAYER metal3 ;
         RECT  563.08 488.16 563.215 488.295 ;
      END
   END dout1[344]
   PIN dout1[345]
      DIRECTION OUTPUT ;
      PORT
         LAYER metal3 ;
         RECT  564.255 488.16 564.39 488.295 ;
      END
   END dout1[345]
   PIN dout1[346]
      DIRECTION OUTPUT ;
      PORT
         LAYER metal3 ;
         RECT  565.43 488.16 565.565 488.295 ;
      END
   END dout1[346]
   PIN dout1[347]
      DIRECTION OUTPUT ;
      PORT
         LAYER metal3 ;
         RECT  566.605 488.16 566.74 488.295 ;
      END
   END dout1[347]
   PIN dout1[348]
      DIRECTION OUTPUT ;
      PORT
         LAYER metal3 ;
         RECT  567.78 488.16 567.915 488.295 ;
      END
   END dout1[348]
   PIN dout1[349]
      DIRECTION OUTPUT ;
      PORT
         LAYER metal3 ;
         RECT  568.955 488.16 569.09 488.295 ;
      END
   END dout1[349]
   PIN dout1[350]
      DIRECTION OUTPUT ;
      PORT
         LAYER metal3 ;
         RECT  570.13 488.16 570.265 488.295 ;
      END
   END dout1[350]
   PIN dout1[351]
      DIRECTION OUTPUT ;
      PORT
         LAYER metal3 ;
         RECT  571.305 488.16 571.44 488.295 ;
      END
   END dout1[351]
   PIN dout1[352]
      DIRECTION OUTPUT ;
      PORT
         LAYER metal3 ;
         RECT  572.48 488.16 572.615 488.295 ;
      END
   END dout1[352]
   PIN dout1[353]
      DIRECTION OUTPUT ;
      PORT
         LAYER metal3 ;
         RECT  573.655 488.16 573.79 488.295 ;
      END
   END dout1[353]
   PIN dout1[354]
      DIRECTION OUTPUT ;
      PORT
         LAYER metal3 ;
         RECT  574.83 488.16 574.965 488.295 ;
      END
   END dout1[354]
   PIN dout1[355]
      DIRECTION OUTPUT ;
      PORT
         LAYER metal3 ;
         RECT  576.005 488.16 576.14 488.295 ;
      END
   END dout1[355]
   PIN dout1[356]
      DIRECTION OUTPUT ;
      PORT
         LAYER metal3 ;
         RECT  577.18 488.16 577.315 488.295 ;
      END
   END dout1[356]
   PIN dout1[357]
      DIRECTION OUTPUT ;
      PORT
         LAYER metal3 ;
         RECT  578.355 488.16 578.49 488.295 ;
      END
   END dout1[357]
   PIN dout1[358]
      DIRECTION OUTPUT ;
      PORT
         LAYER metal3 ;
         RECT  579.53 488.16 579.665 488.295 ;
      END
   END dout1[358]
   PIN dout1[359]
      DIRECTION OUTPUT ;
      PORT
         LAYER metal3 ;
         RECT  580.705 488.16 580.84 488.295 ;
      END
   END dout1[359]
   PIN dout1[360]
      DIRECTION OUTPUT ;
      PORT
         LAYER metal3 ;
         RECT  581.88 488.16 582.015 488.295 ;
      END
   END dout1[360]
   PIN dout1[361]
      DIRECTION OUTPUT ;
      PORT
         LAYER metal3 ;
         RECT  583.055 488.16 583.19 488.295 ;
      END
   END dout1[361]
   PIN dout1[362]
      DIRECTION OUTPUT ;
      PORT
         LAYER metal3 ;
         RECT  584.23 488.16 584.365 488.295 ;
      END
   END dout1[362]
   PIN dout1[363]
      DIRECTION OUTPUT ;
      PORT
         LAYER metal3 ;
         RECT  585.405 488.16 585.54 488.295 ;
      END
   END dout1[363]
   PIN dout1[364]
      DIRECTION OUTPUT ;
      PORT
         LAYER metal3 ;
         RECT  586.58 488.16 586.715 488.295 ;
      END
   END dout1[364]
   PIN dout1[365]
      DIRECTION OUTPUT ;
      PORT
         LAYER metal3 ;
         RECT  587.755 488.16 587.89 488.295 ;
      END
   END dout1[365]
   PIN dout1[366]
      DIRECTION OUTPUT ;
      PORT
         LAYER metal3 ;
         RECT  588.93 488.16 589.065 488.295 ;
      END
   END dout1[366]
   PIN dout1[367]
      DIRECTION OUTPUT ;
      PORT
         LAYER metal3 ;
         RECT  590.105 488.16 590.24 488.295 ;
      END
   END dout1[367]
   PIN dout1[368]
      DIRECTION OUTPUT ;
      PORT
         LAYER metal3 ;
         RECT  591.28 488.16 591.415 488.295 ;
      END
   END dout1[368]
   PIN dout1[369]
      DIRECTION OUTPUT ;
      PORT
         LAYER metal3 ;
         RECT  592.455 488.16 592.59 488.295 ;
      END
   END dout1[369]
   PIN dout1[370]
      DIRECTION OUTPUT ;
      PORT
         LAYER metal3 ;
         RECT  593.63 488.16 593.765 488.295 ;
      END
   END dout1[370]
   PIN dout1[371]
      DIRECTION OUTPUT ;
      PORT
         LAYER metal3 ;
         RECT  594.805 488.16 594.94 488.295 ;
      END
   END dout1[371]
   PIN dout1[372]
      DIRECTION OUTPUT ;
      PORT
         LAYER metal3 ;
         RECT  595.98 488.16 596.115 488.295 ;
      END
   END dout1[372]
   PIN dout1[373]
      DIRECTION OUTPUT ;
      PORT
         LAYER metal3 ;
         RECT  597.155 488.16 597.29 488.295 ;
      END
   END dout1[373]
   PIN dout1[374]
      DIRECTION OUTPUT ;
      PORT
         LAYER metal3 ;
         RECT  598.33 488.16 598.465 488.295 ;
      END
   END dout1[374]
   PIN dout1[375]
      DIRECTION OUTPUT ;
      PORT
         LAYER metal3 ;
         RECT  599.505 488.16 599.64 488.295 ;
      END
   END dout1[375]
   PIN dout1[376]
      DIRECTION OUTPUT ;
      PORT
         LAYER metal3 ;
         RECT  600.68 488.16 600.815 488.295 ;
      END
   END dout1[376]
   PIN dout1[377]
      DIRECTION OUTPUT ;
      PORT
         LAYER metal3 ;
         RECT  601.855 488.16 601.99 488.295 ;
      END
   END dout1[377]
   PIN dout1[378]
      DIRECTION OUTPUT ;
      PORT
         LAYER metal3 ;
         RECT  603.03 488.16 603.165 488.295 ;
      END
   END dout1[378]
   PIN dout1[379]
      DIRECTION OUTPUT ;
      PORT
         LAYER metal3 ;
         RECT  604.205 488.16 604.34 488.295 ;
      END
   END dout1[379]
   PIN dout1[380]
      DIRECTION OUTPUT ;
      PORT
         LAYER metal3 ;
         RECT  605.38 488.16 605.515 488.295 ;
      END
   END dout1[380]
   PIN dout1[381]
      DIRECTION OUTPUT ;
      PORT
         LAYER metal3 ;
         RECT  606.555 488.16 606.69 488.295 ;
      END
   END dout1[381]
   PIN dout1[382]
      DIRECTION OUTPUT ;
      PORT
         LAYER metal3 ;
         RECT  607.73 488.16 607.865 488.295 ;
      END
   END dout1[382]
   PIN dout1[383]
      DIRECTION OUTPUT ;
      PORT
         LAYER metal3 ;
         RECT  608.905 488.16 609.04 488.295 ;
      END
   END dout1[383]
   PIN dout1[384]
      DIRECTION OUTPUT ;
      PORT
         LAYER metal3 ;
         RECT  610.08 488.16 610.215 488.295 ;
      END
   END dout1[384]
   PIN dout1[385]
      DIRECTION OUTPUT ;
      PORT
         LAYER metal3 ;
         RECT  611.255 488.16 611.39 488.295 ;
      END
   END dout1[385]
   PIN dout1[386]
      DIRECTION OUTPUT ;
      PORT
         LAYER metal3 ;
         RECT  612.43 488.16 612.565 488.295 ;
      END
   END dout1[386]
   PIN dout1[387]
      DIRECTION OUTPUT ;
      PORT
         LAYER metal3 ;
         RECT  613.605 488.16 613.74 488.295 ;
      END
   END dout1[387]
   PIN dout1[388]
      DIRECTION OUTPUT ;
      PORT
         LAYER metal3 ;
         RECT  614.78 488.16 614.915 488.295 ;
      END
   END dout1[388]
   PIN dout1[389]
      DIRECTION OUTPUT ;
      PORT
         LAYER metal3 ;
         RECT  615.955 488.16 616.09 488.295 ;
      END
   END dout1[389]
   PIN dout1[390]
      DIRECTION OUTPUT ;
      PORT
         LAYER metal3 ;
         RECT  617.13 488.16 617.265 488.295 ;
      END
   END dout1[390]
   PIN dout1[391]
      DIRECTION OUTPUT ;
      PORT
         LAYER metal3 ;
         RECT  618.305 488.16 618.44 488.295 ;
      END
   END dout1[391]
   PIN dout1[392]
      DIRECTION OUTPUT ;
      PORT
         LAYER metal3 ;
         RECT  619.48 488.16 619.615 488.295 ;
      END
   END dout1[392]
   PIN dout1[393]
      DIRECTION OUTPUT ;
      PORT
         LAYER metal3 ;
         RECT  620.655 488.16 620.79 488.295 ;
      END
   END dout1[393]
   PIN dout1[394]
      DIRECTION OUTPUT ;
      PORT
         LAYER metal3 ;
         RECT  621.83 488.16 621.965 488.295 ;
      END
   END dout1[394]
   PIN dout1[395]
      DIRECTION OUTPUT ;
      PORT
         LAYER metal3 ;
         RECT  623.005 488.16 623.14 488.295 ;
      END
   END dout1[395]
   PIN dout1[396]
      DIRECTION OUTPUT ;
      PORT
         LAYER metal3 ;
         RECT  624.18 488.16 624.315 488.295 ;
      END
   END dout1[396]
   PIN dout1[397]
      DIRECTION OUTPUT ;
      PORT
         LAYER metal3 ;
         RECT  625.355 488.16 625.49 488.295 ;
      END
   END dout1[397]
   PIN dout1[398]
      DIRECTION OUTPUT ;
      PORT
         LAYER metal3 ;
         RECT  626.53 488.16 626.665 488.295 ;
      END
   END dout1[398]
   PIN dout1[399]
      DIRECTION OUTPUT ;
      PORT
         LAYER metal3 ;
         RECT  627.705 488.16 627.84 488.295 ;
      END
   END dout1[399]
   PIN dout1[400]
      DIRECTION OUTPUT ;
      PORT
         LAYER metal3 ;
         RECT  628.88 488.16 629.015 488.295 ;
      END
   END dout1[400]
   PIN dout1[401]
      DIRECTION OUTPUT ;
      PORT
         LAYER metal3 ;
         RECT  630.055 488.16 630.19 488.295 ;
      END
   END dout1[401]
   PIN dout1[402]
      DIRECTION OUTPUT ;
      PORT
         LAYER metal3 ;
         RECT  631.23 488.16 631.365 488.295 ;
      END
   END dout1[402]
   PIN dout1[403]
      DIRECTION OUTPUT ;
      PORT
         LAYER metal3 ;
         RECT  632.405 488.16 632.54 488.295 ;
      END
   END dout1[403]
   PIN dout1[404]
      DIRECTION OUTPUT ;
      PORT
         LAYER metal3 ;
         RECT  633.58 488.16 633.715 488.295 ;
      END
   END dout1[404]
   PIN dout1[405]
      DIRECTION OUTPUT ;
      PORT
         LAYER metal3 ;
         RECT  634.755 488.16 634.89 488.295 ;
      END
   END dout1[405]
   PIN dout1[406]
      DIRECTION OUTPUT ;
      PORT
         LAYER metal3 ;
         RECT  635.93 488.16 636.065 488.295 ;
      END
   END dout1[406]
   PIN dout1[407]
      DIRECTION OUTPUT ;
      PORT
         LAYER metal3 ;
         RECT  637.105 488.16 637.24 488.295 ;
      END
   END dout1[407]
   PIN dout1[408]
      DIRECTION OUTPUT ;
      PORT
         LAYER metal3 ;
         RECT  638.28 488.16 638.415 488.295 ;
      END
   END dout1[408]
   PIN dout1[409]
      DIRECTION OUTPUT ;
      PORT
         LAYER metal3 ;
         RECT  639.455 488.16 639.59 488.295 ;
      END
   END dout1[409]
   PIN dout1[410]
      DIRECTION OUTPUT ;
      PORT
         LAYER metal3 ;
         RECT  640.63 488.16 640.765 488.295 ;
      END
   END dout1[410]
   PIN dout1[411]
      DIRECTION OUTPUT ;
      PORT
         LAYER metal3 ;
         RECT  641.805 488.16 641.94 488.295 ;
      END
   END dout1[411]
   PIN dout1[412]
      DIRECTION OUTPUT ;
      PORT
         LAYER metal3 ;
         RECT  642.98 488.16 643.115 488.295 ;
      END
   END dout1[412]
   PIN dout1[413]
      DIRECTION OUTPUT ;
      PORT
         LAYER metal3 ;
         RECT  644.155 488.16 644.29 488.295 ;
      END
   END dout1[413]
   PIN dout1[414]
      DIRECTION OUTPUT ;
      PORT
         LAYER metal3 ;
         RECT  645.33 488.16 645.465 488.295 ;
      END
   END dout1[414]
   PIN dout1[415]
      DIRECTION OUTPUT ;
      PORT
         LAYER metal3 ;
         RECT  646.505 488.16 646.64 488.295 ;
      END
   END dout1[415]
   PIN dout1[416]
      DIRECTION OUTPUT ;
      PORT
         LAYER metal3 ;
         RECT  647.68 488.16 647.815 488.295 ;
      END
   END dout1[416]
   PIN dout1[417]
      DIRECTION OUTPUT ;
      PORT
         LAYER metal3 ;
         RECT  648.855 488.16 648.99 488.295 ;
      END
   END dout1[417]
   PIN dout1[418]
      DIRECTION OUTPUT ;
      PORT
         LAYER metal3 ;
         RECT  650.03 488.16 650.165 488.295 ;
      END
   END dout1[418]
   PIN dout1[419]
      DIRECTION OUTPUT ;
      PORT
         LAYER metal3 ;
         RECT  651.205 488.16 651.34 488.295 ;
      END
   END dout1[419]
   PIN dout1[420]
      DIRECTION OUTPUT ;
      PORT
         LAYER metal3 ;
         RECT  652.38 488.16 652.515 488.295 ;
      END
   END dout1[420]
   PIN dout1[421]
      DIRECTION OUTPUT ;
      PORT
         LAYER metal3 ;
         RECT  653.555 488.16 653.69 488.295 ;
      END
   END dout1[421]
   PIN dout1[422]
      DIRECTION OUTPUT ;
      PORT
         LAYER metal3 ;
         RECT  654.73 488.16 654.865 488.295 ;
      END
   END dout1[422]
   PIN dout1[423]
      DIRECTION OUTPUT ;
      PORT
         LAYER metal3 ;
         RECT  655.905 488.16 656.04 488.295 ;
      END
   END dout1[423]
   PIN dout1[424]
      DIRECTION OUTPUT ;
      PORT
         LAYER metal3 ;
         RECT  657.08 488.16 657.215 488.295 ;
      END
   END dout1[424]
   PIN dout1[425]
      DIRECTION OUTPUT ;
      PORT
         LAYER metal3 ;
         RECT  658.255 488.16 658.39 488.295 ;
      END
   END dout1[425]
   PIN dout1[426]
      DIRECTION OUTPUT ;
      PORT
         LAYER metal3 ;
         RECT  659.43 488.16 659.565 488.295 ;
      END
   END dout1[426]
   PIN dout1[427]
      DIRECTION OUTPUT ;
      PORT
         LAYER metal3 ;
         RECT  660.605 488.16 660.74 488.295 ;
      END
   END dout1[427]
   PIN dout1[428]
      DIRECTION OUTPUT ;
      PORT
         LAYER metal3 ;
         RECT  661.78 488.16 661.915 488.295 ;
      END
   END dout1[428]
   PIN dout1[429]
      DIRECTION OUTPUT ;
      PORT
         LAYER metal3 ;
         RECT  662.955 488.16 663.09 488.295 ;
      END
   END dout1[429]
   PIN dout1[430]
      DIRECTION OUTPUT ;
      PORT
         LAYER metal3 ;
         RECT  664.13 488.16 664.265 488.295 ;
      END
   END dout1[430]
   PIN dout1[431]
      DIRECTION OUTPUT ;
      PORT
         LAYER metal3 ;
         RECT  665.305 488.16 665.44 488.295 ;
      END
   END dout1[431]
   PIN dout1[432]
      DIRECTION OUTPUT ;
      PORT
         LAYER metal3 ;
         RECT  666.48 488.16 666.615 488.295 ;
      END
   END dout1[432]
   PIN dout1[433]
      DIRECTION OUTPUT ;
      PORT
         LAYER metal3 ;
         RECT  667.655 488.16 667.79 488.295 ;
      END
   END dout1[433]
   PIN dout1[434]
      DIRECTION OUTPUT ;
      PORT
         LAYER metal3 ;
         RECT  668.83 488.16 668.965 488.295 ;
      END
   END dout1[434]
   PIN dout1[435]
      DIRECTION OUTPUT ;
      PORT
         LAYER metal3 ;
         RECT  670.005 488.16 670.14 488.295 ;
      END
   END dout1[435]
   PIN dout1[436]
      DIRECTION OUTPUT ;
      PORT
         LAYER metal3 ;
         RECT  671.18 488.16 671.315 488.295 ;
      END
   END dout1[436]
   PIN dout1[437]
      DIRECTION OUTPUT ;
      PORT
         LAYER metal3 ;
         RECT  672.355 488.16 672.49 488.295 ;
      END
   END dout1[437]
   PIN dout1[438]
      DIRECTION OUTPUT ;
      PORT
         LAYER metal3 ;
         RECT  673.53 488.16 673.665 488.295 ;
      END
   END dout1[438]
   PIN dout1[439]
      DIRECTION OUTPUT ;
      PORT
         LAYER metal3 ;
         RECT  674.705 488.16 674.84 488.295 ;
      END
   END dout1[439]
   PIN dout1[440]
      DIRECTION OUTPUT ;
      PORT
         LAYER metal3 ;
         RECT  675.88 488.16 676.015 488.295 ;
      END
   END dout1[440]
   PIN dout1[441]
      DIRECTION OUTPUT ;
      PORT
         LAYER metal3 ;
         RECT  677.055 488.16 677.19 488.295 ;
      END
   END dout1[441]
   PIN dout1[442]
      DIRECTION OUTPUT ;
      PORT
         LAYER metal3 ;
         RECT  678.23 488.16 678.365 488.295 ;
      END
   END dout1[442]
   PIN dout1[443]
      DIRECTION OUTPUT ;
      PORT
         LAYER metal3 ;
         RECT  679.405 488.16 679.54 488.295 ;
      END
   END dout1[443]
   PIN dout1[444]
      DIRECTION OUTPUT ;
      PORT
         LAYER metal3 ;
         RECT  680.58 488.16 680.715 488.295 ;
      END
   END dout1[444]
   PIN dout1[445]
      DIRECTION OUTPUT ;
      PORT
         LAYER metal3 ;
         RECT  681.755 488.16 681.89 488.295 ;
      END
   END dout1[445]
   PIN dout1[446]
      DIRECTION OUTPUT ;
      PORT
         LAYER metal3 ;
         RECT  682.93 488.16 683.065 488.295 ;
      END
   END dout1[446]
   PIN dout1[447]
      DIRECTION OUTPUT ;
      PORT
         LAYER metal3 ;
         RECT  684.105 488.16 684.24 488.295 ;
      END
   END dout1[447]
   PIN dout1[448]
      DIRECTION OUTPUT ;
      PORT
         LAYER metal3 ;
         RECT  685.28 488.16 685.415 488.295 ;
      END
   END dout1[448]
   PIN dout1[449]
      DIRECTION OUTPUT ;
      PORT
         LAYER metal3 ;
         RECT  686.455 488.16 686.59 488.295 ;
      END
   END dout1[449]
   PIN dout1[450]
      DIRECTION OUTPUT ;
      PORT
         LAYER metal3 ;
         RECT  687.63 488.16 687.765 488.295 ;
      END
   END dout1[450]
   PIN dout1[451]
      DIRECTION OUTPUT ;
      PORT
         LAYER metal3 ;
         RECT  688.805 488.16 688.94 488.295 ;
      END
   END dout1[451]
   PIN dout1[452]
      DIRECTION OUTPUT ;
      PORT
         LAYER metal3 ;
         RECT  689.98 488.16 690.115 488.295 ;
      END
   END dout1[452]
   PIN dout1[453]
      DIRECTION OUTPUT ;
      PORT
         LAYER metal3 ;
         RECT  691.155 488.16 691.29 488.295 ;
      END
   END dout1[453]
   PIN dout1[454]
      DIRECTION OUTPUT ;
      PORT
         LAYER metal3 ;
         RECT  692.33 488.16 692.465 488.295 ;
      END
   END dout1[454]
   PIN dout1[455]
      DIRECTION OUTPUT ;
      PORT
         LAYER metal3 ;
         RECT  693.505 488.16 693.64 488.295 ;
      END
   END dout1[455]
   PIN dout1[456]
      DIRECTION OUTPUT ;
      PORT
         LAYER metal3 ;
         RECT  694.68 488.16 694.815 488.295 ;
      END
   END dout1[456]
   PIN dout1[457]
      DIRECTION OUTPUT ;
      PORT
         LAYER metal3 ;
         RECT  695.855 488.16 695.99 488.295 ;
      END
   END dout1[457]
   PIN dout1[458]
      DIRECTION OUTPUT ;
      PORT
         LAYER metal3 ;
         RECT  697.03 488.16 697.165 488.295 ;
      END
   END dout1[458]
   PIN dout1[459]
      DIRECTION OUTPUT ;
      PORT
         LAYER metal3 ;
         RECT  698.205 488.16 698.34 488.295 ;
      END
   END dout1[459]
   PIN dout1[460]
      DIRECTION OUTPUT ;
      PORT
         LAYER metal3 ;
         RECT  699.38 488.16 699.515 488.295 ;
      END
   END dout1[460]
   PIN dout1[461]
      DIRECTION OUTPUT ;
      PORT
         LAYER metal3 ;
         RECT  700.555 488.16 700.69 488.295 ;
      END
   END dout1[461]
   PIN dout1[462]
      DIRECTION OUTPUT ;
      PORT
         LAYER metal3 ;
         RECT  701.73 488.16 701.865 488.295 ;
      END
   END dout1[462]
   PIN dout1[463]
      DIRECTION OUTPUT ;
      PORT
         LAYER metal3 ;
         RECT  702.905 488.16 703.04 488.295 ;
      END
   END dout1[463]
   PIN dout1[464]
      DIRECTION OUTPUT ;
      PORT
         LAYER metal3 ;
         RECT  704.08 488.16 704.215 488.295 ;
      END
   END dout1[464]
   PIN dout1[465]
      DIRECTION OUTPUT ;
      PORT
         LAYER metal3 ;
         RECT  705.255 488.16 705.39 488.295 ;
      END
   END dout1[465]
   PIN dout1[466]
      DIRECTION OUTPUT ;
      PORT
         LAYER metal3 ;
         RECT  706.43 488.16 706.565 488.295 ;
      END
   END dout1[466]
   PIN dout1[467]
      DIRECTION OUTPUT ;
      PORT
         LAYER metal3 ;
         RECT  707.605 488.16 707.74 488.295 ;
      END
   END dout1[467]
   PIN dout1[468]
      DIRECTION OUTPUT ;
      PORT
         LAYER metal3 ;
         RECT  708.78 488.16 708.915 488.295 ;
      END
   END dout1[468]
   PIN dout1[469]
      DIRECTION OUTPUT ;
      PORT
         LAYER metal3 ;
         RECT  709.955 488.16 710.09 488.295 ;
      END
   END dout1[469]
   PIN dout1[470]
      DIRECTION OUTPUT ;
      PORT
         LAYER metal3 ;
         RECT  711.13 488.16 711.265 488.295 ;
      END
   END dout1[470]
   PIN dout1[471]
      DIRECTION OUTPUT ;
      PORT
         LAYER metal3 ;
         RECT  712.305 488.16 712.44 488.295 ;
      END
   END dout1[471]
   PIN dout1[472]
      DIRECTION OUTPUT ;
      PORT
         LAYER metal3 ;
         RECT  713.48 488.16 713.615 488.295 ;
      END
   END dout1[472]
   PIN dout1[473]
      DIRECTION OUTPUT ;
      PORT
         LAYER metal3 ;
         RECT  714.655 488.16 714.79 488.295 ;
      END
   END dout1[473]
   PIN dout1[474]
      DIRECTION OUTPUT ;
      PORT
         LAYER metal3 ;
         RECT  715.83 488.16 715.965 488.295 ;
      END
   END dout1[474]
   PIN dout1[475]
      DIRECTION OUTPUT ;
      PORT
         LAYER metal3 ;
         RECT  717.005 488.16 717.14 488.295 ;
      END
   END dout1[475]
   PIN dout1[476]
      DIRECTION OUTPUT ;
      PORT
         LAYER metal3 ;
         RECT  718.18 488.16 718.315 488.295 ;
      END
   END dout1[476]
   PIN dout1[477]
      DIRECTION OUTPUT ;
      PORT
         LAYER metal3 ;
         RECT  719.355 488.16 719.49 488.295 ;
      END
   END dout1[477]
   PIN dout1[478]
      DIRECTION OUTPUT ;
      PORT
         LAYER metal3 ;
         RECT  720.53 488.16 720.665 488.295 ;
      END
   END dout1[478]
   PIN dout1[479]
      DIRECTION OUTPUT ;
      PORT
         LAYER metal3 ;
         RECT  721.705 488.16 721.84 488.295 ;
      END
   END dout1[479]
   PIN dout1[480]
      DIRECTION OUTPUT ;
      PORT
         LAYER metal3 ;
         RECT  722.88 488.16 723.015 488.295 ;
      END
   END dout1[480]
   PIN dout1[481]
      DIRECTION OUTPUT ;
      PORT
         LAYER metal3 ;
         RECT  724.055 488.16 724.19 488.295 ;
      END
   END dout1[481]
   PIN dout1[482]
      DIRECTION OUTPUT ;
      PORT
         LAYER metal3 ;
         RECT  725.23 488.16 725.365 488.295 ;
      END
   END dout1[482]
   PIN dout1[483]
      DIRECTION OUTPUT ;
      PORT
         LAYER metal3 ;
         RECT  726.405 488.16 726.54 488.295 ;
      END
   END dout1[483]
   PIN dout1[484]
      DIRECTION OUTPUT ;
      PORT
         LAYER metal3 ;
         RECT  727.58 488.16 727.715 488.295 ;
      END
   END dout1[484]
   PIN dout1[485]
      DIRECTION OUTPUT ;
      PORT
         LAYER metal3 ;
         RECT  728.755 488.16 728.89 488.295 ;
      END
   END dout1[485]
   PIN dout1[486]
      DIRECTION OUTPUT ;
      PORT
         LAYER metal3 ;
         RECT  729.93 488.16 730.065 488.295 ;
      END
   END dout1[486]
   PIN dout1[487]
      DIRECTION OUTPUT ;
      PORT
         LAYER metal3 ;
         RECT  731.105 488.16 731.24 488.295 ;
      END
   END dout1[487]
   PIN dout1[488]
      DIRECTION OUTPUT ;
      PORT
         LAYER metal3 ;
         RECT  732.28 488.16 732.415 488.295 ;
      END
   END dout1[488]
   PIN dout1[489]
      DIRECTION OUTPUT ;
      PORT
         LAYER metal3 ;
         RECT  733.455 488.16 733.59 488.295 ;
      END
   END dout1[489]
   PIN dout1[490]
      DIRECTION OUTPUT ;
      PORT
         LAYER metal3 ;
         RECT  734.63 488.16 734.765 488.295 ;
      END
   END dout1[490]
   PIN dout1[491]
      DIRECTION OUTPUT ;
      PORT
         LAYER metal3 ;
         RECT  735.805 488.16 735.94 488.295 ;
      END
   END dout1[491]
   PIN dout1[492]
      DIRECTION OUTPUT ;
      PORT
         LAYER metal3 ;
         RECT  736.98 488.16 737.115 488.295 ;
      END
   END dout1[492]
   PIN dout1[493]
      DIRECTION OUTPUT ;
      PORT
         LAYER metal3 ;
         RECT  738.155 488.16 738.29 488.295 ;
      END
   END dout1[493]
   PIN dout1[494]
      DIRECTION OUTPUT ;
      PORT
         LAYER metal3 ;
         RECT  739.33 488.16 739.465 488.295 ;
      END
   END dout1[494]
   PIN dout1[495]
      DIRECTION OUTPUT ;
      PORT
         LAYER metal3 ;
         RECT  740.505 488.16 740.64 488.295 ;
      END
   END dout1[495]
   PIN dout1[496]
      DIRECTION OUTPUT ;
      PORT
         LAYER metal3 ;
         RECT  741.68 488.16 741.815 488.295 ;
      END
   END dout1[496]
   PIN dout1[497]
      DIRECTION OUTPUT ;
      PORT
         LAYER metal3 ;
         RECT  742.855 488.16 742.99 488.295 ;
      END
   END dout1[497]
   PIN dout1[498]
      DIRECTION OUTPUT ;
      PORT
         LAYER metal3 ;
         RECT  744.03 488.16 744.165 488.295 ;
      END
   END dout1[498]
   PIN dout1[499]
      DIRECTION OUTPUT ;
      PORT
         LAYER metal3 ;
         RECT  745.205 488.16 745.34 488.295 ;
      END
   END dout1[499]
   PIN dout1[500]
      DIRECTION OUTPUT ;
      PORT
         LAYER metal3 ;
         RECT  746.38 488.16 746.515 488.295 ;
      END
   END dout1[500]
   PIN dout1[501]
      DIRECTION OUTPUT ;
      PORT
         LAYER metal3 ;
         RECT  747.555 488.16 747.69 488.295 ;
      END
   END dout1[501]
   PIN dout1[502]
      DIRECTION OUTPUT ;
      PORT
         LAYER metal3 ;
         RECT  748.73 488.16 748.865 488.295 ;
      END
   END dout1[502]
   PIN dout1[503]
      DIRECTION OUTPUT ;
      PORT
         LAYER metal3 ;
         RECT  749.905 488.16 750.04 488.295 ;
      END
   END dout1[503]
   PIN dout1[504]
      DIRECTION OUTPUT ;
      PORT
         LAYER metal3 ;
         RECT  751.08 488.16 751.215 488.295 ;
      END
   END dout1[504]
   PIN dout1[505]
      DIRECTION OUTPUT ;
      PORT
         LAYER metal3 ;
         RECT  752.255 488.16 752.39 488.295 ;
      END
   END dout1[505]
   PIN dout1[506]
      DIRECTION OUTPUT ;
      PORT
         LAYER metal3 ;
         RECT  753.43 488.16 753.565 488.295 ;
      END
   END dout1[506]
   PIN dout1[507]
      DIRECTION OUTPUT ;
      PORT
         LAYER metal3 ;
         RECT  754.605 488.16 754.74 488.295 ;
      END
   END dout1[507]
   PIN dout1[508]
      DIRECTION OUTPUT ;
      PORT
         LAYER metal3 ;
         RECT  755.78 488.16 755.915 488.295 ;
      END
   END dout1[508]
   PIN dout1[509]
      DIRECTION OUTPUT ;
      PORT
         LAYER metal3 ;
         RECT  756.955 488.16 757.09 488.295 ;
      END
   END dout1[509]
   PIN dout1[510]
      DIRECTION OUTPUT ;
      PORT
         LAYER metal3 ;
         RECT  758.13 488.16 758.265 488.295 ;
      END
   END dout1[510]
   PIN dout1[511]
      DIRECTION OUTPUT ;
      PORT
         LAYER metal3 ;
         RECT  759.305 488.16 759.44 488.295 ;
      END
   END dout1[511]
   PIN vdd
      DIRECTION INOUT ;
      USE POWER ; 
      SHAPE ABUTMENT ; 
      PORT
      END
   END vdd
   PIN gnd
      DIRECTION INOUT ;
      USE GROUND ; 
      SHAPE ABUTMENT ; 
      PORT
      END
   END gnd
   OBS
   LAYER  metal1 ;
      RECT  0.14 0.14 1587.205 495.395 ;
   LAYER  metal2 ;
      RECT  0.14 0.14 1587.205 495.395 ;
   LAYER  metal3 ;
      RECT  0.14 0.14 123.1 0.8975 ;
      RECT  0.14 0.8975 123.1 1.3125 ;
      RECT  123.1 0.14 123.515 0.8975 ;
      RECT  123.1 1.3125 123.515 495.395 ;
      RECT  123.515 0.14 1587.205 0.8975 ;
      RECT  123.515 0.8975 125.96 1.3125 ;
      RECT  126.375 0.8975 128.82 1.3125 ;
      RECT  129.235 0.8975 131.68 1.3125 ;
      RECT  132.095 0.8975 134.54 1.3125 ;
      RECT  134.955 0.8975 137.4 1.3125 ;
      RECT  137.815 0.8975 140.26 1.3125 ;
      RECT  140.675 0.8975 143.12 1.3125 ;
      RECT  143.535 0.8975 145.98 1.3125 ;
      RECT  146.395 0.8975 148.84 1.3125 ;
      RECT  149.255 0.8975 151.7 1.3125 ;
      RECT  152.115 0.8975 154.56 1.3125 ;
      RECT  154.975 0.8975 157.42 1.3125 ;
      RECT  157.835 0.8975 160.28 1.3125 ;
      RECT  160.695 0.8975 163.14 1.3125 ;
      RECT  163.555 0.8975 166.0 1.3125 ;
      RECT  166.415 0.8975 168.86 1.3125 ;
      RECT  169.275 0.8975 171.72 1.3125 ;
      RECT  172.135 0.8975 174.58 1.3125 ;
      RECT  174.995 0.8975 177.44 1.3125 ;
      RECT  177.855 0.8975 180.3 1.3125 ;
      RECT  180.715 0.8975 183.16 1.3125 ;
      RECT  183.575 0.8975 186.02 1.3125 ;
      RECT  186.435 0.8975 188.88 1.3125 ;
      RECT  189.295 0.8975 191.74 1.3125 ;
      RECT  192.155 0.8975 194.6 1.3125 ;
      RECT  195.015 0.8975 197.46 1.3125 ;
      RECT  197.875 0.8975 200.32 1.3125 ;
      RECT  200.735 0.8975 203.18 1.3125 ;
      RECT  203.595 0.8975 206.04 1.3125 ;
      RECT  206.455 0.8975 208.9 1.3125 ;
      RECT  209.315 0.8975 211.76 1.3125 ;
      RECT  212.175 0.8975 214.62 1.3125 ;
      RECT  215.035 0.8975 217.48 1.3125 ;
      RECT  217.895 0.8975 220.34 1.3125 ;
      RECT  220.755 0.8975 223.2 1.3125 ;
      RECT  223.615 0.8975 226.06 1.3125 ;
      RECT  226.475 0.8975 228.92 1.3125 ;
      RECT  229.335 0.8975 231.78 1.3125 ;
      RECT  232.195 0.8975 234.64 1.3125 ;
      RECT  235.055 0.8975 237.5 1.3125 ;
      RECT  237.915 0.8975 240.36 1.3125 ;
      RECT  240.775 0.8975 243.22 1.3125 ;
      RECT  243.635 0.8975 246.08 1.3125 ;
      RECT  246.495 0.8975 248.94 1.3125 ;
      RECT  249.355 0.8975 251.8 1.3125 ;
      RECT  252.215 0.8975 254.66 1.3125 ;
      RECT  255.075 0.8975 257.52 1.3125 ;
      RECT  257.935 0.8975 260.38 1.3125 ;
      RECT  260.795 0.8975 263.24 1.3125 ;
      RECT  263.655 0.8975 266.1 1.3125 ;
      RECT  266.515 0.8975 268.96 1.3125 ;
      RECT  269.375 0.8975 271.82 1.3125 ;
      RECT  272.235 0.8975 274.68 1.3125 ;
      RECT  275.095 0.8975 277.54 1.3125 ;
      RECT  277.955 0.8975 280.4 1.3125 ;
      RECT  280.815 0.8975 283.26 1.3125 ;
      RECT  283.675 0.8975 286.12 1.3125 ;
      RECT  286.535 0.8975 288.98 1.3125 ;
      RECT  289.395 0.8975 291.84 1.3125 ;
      RECT  292.255 0.8975 294.7 1.3125 ;
      RECT  295.115 0.8975 297.56 1.3125 ;
      RECT  297.975 0.8975 300.42 1.3125 ;
      RECT  300.835 0.8975 303.28 1.3125 ;
      RECT  303.695 0.8975 306.14 1.3125 ;
      RECT  306.555 0.8975 309.0 1.3125 ;
      RECT  309.415 0.8975 311.86 1.3125 ;
      RECT  312.275 0.8975 314.72 1.3125 ;
      RECT  315.135 0.8975 317.58 1.3125 ;
      RECT  317.995 0.8975 320.44 1.3125 ;
      RECT  320.855 0.8975 323.3 1.3125 ;
      RECT  323.715 0.8975 326.16 1.3125 ;
      RECT  326.575 0.8975 329.02 1.3125 ;
      RECT  329.435 0.8975 331.88 1.3125 ;
      RECT  332.295 0.8975 334.74 1.3125 ;
      RECT  335.155 0.8975 337.6 1.3125 ;
      RECT  338.015 0.8975 340.46 1.3125 ;
      RECT  340.875 0.8975 343.32 1.3125 ;
      RECT  343.735 0.8975 346.18 1.3125 ;
      RECT  346.595 0.8975 349.04 1.3125 ;
      RECT  349.455 0.8975 351.9 1.3125 ;
      RECT  352.315 0.8975 354.76 1.3125 ;
      RECT  355.175 0.8975 357.62 1.3125 ;
      RECT  358.035 0.8975 360.48 1.3125 ;
      RECT  360.895 0.8975 363.34 1.3125 ;
      RECT  363.755 0.8975 366.2 1.3125 ;
      RECT  366.615 0.8975 369.06 1.3125 ;
      RECT  369.475 0.8975 371.92 1.3125 ;
      RECT  372.335 0.8975 374.78 1.3125 ;
      RECT  375.195 0.8975 377.64 1.3125 ;
      RECT  378.055 0.8975 380.5 1.3125 ;
      RECT  380.915 0.8975 383.36 1.3125 ;
      RECT  383.775 0.8975 386.22 1.3125 ;
      RECT  386.635 0.8975 389.08 1.3125 ;
      RECT  389.495 0.8975 391.94 1.3125 ;
      RECT  392.355 0.8975 394.8 1.3125 ;
      RECT  395.215 0.8975 397.66 1.3125 ;
      RECT  398.075 0.8975 400.52 1.3125 ;
      RECT  400.935 0.8975 403.38 1.3125 ;
      RECT  403.795 0.8975 406.24 1.3125 ;
      RECT  406.655 0.8975 409.1 1.3125 ;
      RECT  409.515 0.8975 411.96 1.3125 ;
      RECT  412.375 0.8975 414.82 1.3125 ;
      RECT  415.235 0.8975 417.68 1.3125 ;
      RECT  418.095 0.8975 420.54 1.3125 ;
      RECT  420.955 0.8975 423.4 1.3125 ;
      RECT  423.815 0.8975 426.26 1.3125 ;
      RECT  426.675 0.8975 429.12 1.3125 ;
      RECT  429.535 0.8975 431.98 1.3125 ;
      RECT  432.395 0.8975 434.84 1.3125 ;
      RECT  435.255 0.8975 437.7 1.3125 ;
      RECT  438.115 0.8975 440.56 1.3125 ;
      RECT  440.975 0.8975 443.42 1.3125 ;
      RECT  443.835 0.8975 446.28 1.3125 ;
      RECT  446.695 0.8975 449.14 1.3125 ;
      RECT  449.555 0.8975 452.0 1.3125 ;
      RECT  452.415 0.8975 454.86 1.3125 ;
      RECT  455.275 0.8975 457.72 1.3125 ;
      RECT  458.135 0.8975 460.58 1.3125 ;
      RECT  460.995 0.8975 463.44 1.3125 ;
      RECT  463.855 0.8975 466.3 1.3125 ;
      RECT  466.715 0.8975 469.16 1.3125 ;
      RECT  469.575 0.8975 472.02 1.3125 ;
      RECT  472.435 0.8975 474.88 1.3125 ;
      RECT  475.295 0.8975 477.74 1.3125 ;
      RECT  478.155 0.8975 480.6 1.3125 ;
      RECT  481.015 0.8975 483.46 1.3125 ;
      RECT  483.875 0.8975 486.32 1.3125 ;
      RECT  486.735 0.8975 489.18 1.3125 ;
      RECT  489.595 0.8975 492.04 1.3125 ;
      RECT  492.455 0.8975 494.9 1.3125 ;
      RECT  495.315 0.8975 497.76 1.3125 ;
      RECT  498.175 0.8975 500.62 1.3125 ;
      RECT  501.035 0.8975 503.48 1.3125 ;
      RECT  503.895 0.8975 506.34 1.3125 ;
      RECT  506.755 0.8975 509.2 1.3125 ;
      RECT  509.615 0.8975 512.06 1.3125 ;
      RECT  512.475 0.8975 514.92 1.3125 ;
      RECT  515.335 0.8975 517.78 1.3125 ;
      RECT  518.195 0.8975 520.64 1.3125 ;
      RECT  521.055 0.8975 523.5 1.3125 ;
      RECT  523.915 0.8975 526.36 1.3125 ;
      RECT  526.775 0.8975 529.22 1.3125 ;
      RECT  529.635 0.8975 532.08 1.3125 ;
      RECT  532.495 0.8975 534.94 1.3125 ;
      RECT  535.355 0.8975 537.8 1.3125 ;
      RECT  538.215 0.8975 540.66 1.3125 ;
      RECT  541.075 0.8975 543.52 1.3125 ;
      RECT  543.935 0.8975 546.38 1.3125 ;
      RECT  546.795 0.8975 549.24 1.3125 ;
      RECT  549.655 0.8975 552.1 1.3125 ;
      RECT  552.515 0.8975 554.96 1.3125 ;
      RECT  555.375 0.8975 557.82 1.3125 ;
      RECT  558.235 0.8975 560.68 1.3125 ;
      RECT  561.095 0.8975 563.54 1.3125 ;
      RECT  563.955 0.8975 566.4 1.3125 ;
      RECT  566.815 0.8975 569.26 1.3125 ;
      RECT  569.675 0.8975 572.12 1.3125 ;
      RECT  572.535 0.8975 574.98 1.3125 ;
      RECT  575.395 0.8975 577.84 1.3125 ;
      RECT  578.255 0.8975 580.7 1.3125 ;
      RECT  581.115 0.8975 583.56 1.3125 ;
      RECT  583.975 0.8975 586.42 1.3125 ;
      RECT  586.835 0.8975 589.28 1.3125 ;
      RECT  589.695 0.8975 592.14 1.3125 ;
      RECT  592.555 0.8975 595.0 1.3125 ;
      RECT  595.415 0.8975 597.86 1.3125 ;
      RECT  598.275 0.8975 600.72 1.3125 ;
      RECT  601.135 0.8975 603.58 1.3125 ;
      RECT  603.995 0.8975 606.44 1.3125 ;
      RECT  606.855 0.8975 609.3 1.3125 ;
      RECT  609.715 0.8975 612.16 1.3125 ;
      RECT  612.575 0.8975 615.02 1.3125 ;
      RECT  615.435 0.8975 617.88 1.3125 ;
      RECT  618.295 0.8975 620.74 1.3125 ;
      RECT  621.155 0.8975 623.6 1.3125 ;
      RECT  624.015 0.8975 626.46 1.3125 ;
      RECT  626.875 0.8975 629.32 1.3125 ;
      RECT  629.735 0.8975 632.18 1.3125 ;
      RECT  632.595 0.8975 635.04 1.3125 ;
      RECT  635.455 0.8975 637.9 1.3125 ;
      RECT  638.315 0.8975 640.76 1.3125 ;
      RECT  641.175 0.8975 643.62 1.3125 ;
      RECT  644.035 0.8975 646.48 1.3125 ;
      RECT  646.895 0.8975 649.34 1.3125 ;
      RECT  649.755 0.8975 652.2 1.3125 ;
      RECT  652.615 0.8975 655.06 1.3125 ;
      RECT  655.475 0.8975 657.92 1.3125 ;
      RECT  658.335 0.8975 660.78 1.3125 ;
      RECT  661.195 0.8975 663.64 1.3125 ;
      RECT  664.055 0.8975 666.5 1.3125 ;
      RECT  666.915 0.8975 669.36 1.3125 ;
      RECT  669.775 0.8975 672.22 1.3125 ;
      RECT  672.635 0.8975 675.08 1.3125 ;
      RECT  675.495 0.8975 677.94 1.3125 ;
      RECT  678.355 0.8975 680.8 1.3125 ;
      RECT  681.215 0.8975 683.66 1.3125 ;
      RECT  684.075 0.8975 686.52 1.3125 ;
      RECT  686.935 0.8975 689.38 1.3125 ;
      RECT  689.795 0.8975 692.24 1.3125 ;
      RECT  692.655 0.8975 695.1 1.3125 ;
      RECT  695.515 0.8975 697.96 1.3125 ;
      RECT  698.375 0.8975 700.82 1.3125 ;
      RECT  701.235 0.8975 703.68 1.3125 ;
      RECT  704.095 0.8975 706.54 1.3125 ;
      RECT  706.955 0.8975 709.4 1.3125 ;
      RECT  709.815 0.8975 712.26 1.3125 ;
      RECT  712.675 0.8975 715.12 1.3125 ;
      RECT  715.535 0.8975 717.98 1.3125 ;
      RECT  718.395 0.8975 720.84 1.3125 ;
      RECT  721.255 0.8975 723.7 1.3125 ;
      RECT  724.115 0.8975 726.56 1.3125 ;
      RECT  726.975 0.8975 729.42 1.3125 ;
      RECT  729.835 0.8975 732.28 1.3125 ;
      RECT  732.695 0.8975 735.14 1.3125 ;
      RECT  735.555 0.8975 738.0 1.3125 ;
      RECT  738.415 0.8975 740.86 1.3125 ;
      RECT  741.275 0.8975 743.72 1.3125 ;
      RECT  744.135 0.8975 746.58 1.3125 ;
      RECT  746.995 0.8975 749.44 1.3125 ;
      RECT  749.855 0.8975 752.3 1.3125 ;
      RECT  752.715 0.8975 755.16 1.3125 ;
      RECT  755.575 0.8975 758.02 1.3125 ;
      RECT  758.435 0.8975 760.88 1.3125 ;
      RECT  761.295 0.8975 763.74 1.3125 ;
      RECT  764.155 0.8975 766.6 1.3125 ;
      RECT  767.015 0.8975 769.46 1.3125 ;
      RECT  769.875 0.8975 772.32 1.3125 ;
      RECT  772.735 0.8975 775.18 1.3125 ;
      RECT  775.595 0.8975 778.04 1.3125 ;
      RECT  778.455 0.8975 780.9 1.3125 ;
      RECT  781.315 0.8975 783.76 1.3125 ;
      RECT  784.175 0.8975 786.62 1.3125 ;
      RECT  787.035 0.8975 789.48 1.3125 ;
      RECT  789.895 0.8975 792.34 1.3125 ;
      RECT  792.755 0.8975 795.2 1.3125 ;
      RECT  795.615 0.8975 798.06 1.3125 ;
      RECT  798.475 0.8975 800.92 1.3125 ;
      RECT  801.335 0.8975 803.78 1.3125 ;
      RECT  804.195 0.8975 806.64 1.3125 ;
      RECT  807.055 0.8975 809.5 1.3125 ;
      RECT  809.915 0.8975 812.36 1.3125 ;
      RECT  812.775 0.8975 815.22 1.3125 ;
      RECT  815.635 0.8975 818.08 1.3125 ;
      RECT  818.495 0.8975 820.94 1.3125 ;
      RECT  821.355 0.8975 823.8 1.3125 ;
      RECT  824.215 0.8975 826.66 1.3125 ;
      RECT  827.075 0.8975 829.52 1.3125 ;
      RECT  829.935 0.8975 832.38 1.3125 ;
      RECT  832.795 0.8975 835.24 1.3125 ;
      RECT  835.655 0.8975 838.1 1.3125 ;
      RECT  838.515 0.8975 840.96 1.3125 ;
      RECT  841.375 0.8975 843.82 1.3125 ;
      RECT  844.235 0.8975 846.68 1.3125 ;
      RECT  847.095 0.8975 849.54 1.3125 ;
      RECT  849.955 0.8975 852.4 1.3125 ;
      RECT  852.815 0.8975 855.26 1.3125 ;
      RECT  855.675 0.8975 858.12 1.3125 ;
      RECT  858.535 0.8975 860.98 1.3125 ;
      RECT  861.395 0.8975 863.84 1.3125 ;
      RECT  864.255 0.8975 866.7 1.3125 ;
      RECT  867.115 0.8975 869.56 1.3125 ;
      RECT  869.975 0.8975 872.42 1.3125 ;
      RECT  872.835 0.8975 875.28 1.3125 ;
      RECT  875.695 0.8975 878.14 1.3125 ;
      RECT  878.555 0.8975 881.0 1.3125 ;
      RECT  881.415 0.8975 883.86 1.3125 ;
      RECT  884.275 0.8975 886.72 1.3125 ;
      RECT  887.135 0.8975 889.58 1.3125 ;
      RECT  889.995 0.8975 892.44 1.3125 ;
      RECT  892.855 0.8975 895.3 1.3125 ;
      RECT  895.715 0.8975 898.16 1.3125 ;
      RECT  898.575 0.8975 901.02 1.3125 ;
      RECT  901.435 0.8975 903.88 1.3125 ;
      RECT  904.295 0.8975 906.74 1.3125 ;
      RECT  907.155 0.8975 909.6 1.3125 ;
      RECT  910.015 0.8975 912.46 1.3125 ;
      RECT  912.875 0.8975 915.32 1.3125 ;
      RECT  915.735 0.8975 918.18 1.3125 ;
      RECT  918.595 0.8975 921.04 1.3125 ;
      RECT  921.455 0.8975 923.9 1.3125 ;
      RECT  924.315 0.8975 926.76 1.3125 ;
      RECT  927.175 0.8975 929.62 1.3125 ;
      RECT  930.035 0.8975 932.48 1.3125 ;
      RECT  932.895 0.8975 935.34 1.3125 ;
      RECT  935.755 0.8975 938.2 1.3125 ;
      RECT  938.615 0.8975 941.06 1.3125 ;
      RECT  941.475 0.8975 943.92 1.3125 ;
      RECT  944.335 0.8975 946.78 1.3125 ;
      RECT  947.195 0.8975 949.64 1.3125 ;
      RECT  950.055 0.8975 952.5 1.3125 ;
      RECT  952.915 0.8975 955.36 1.3125 ;
      RECT  955.775 0.8975 958.22 1.3125 ;
      RECT  958.635 0.8975 961.08 1.3125 ;
      RECT  961.495 0.8975 963.94 1.3125 ;
      RECT  964.355 0.8975 966.8 1.3125 ;
      RECT  967.215 0.8975 969.66 1.3125 ;
      RECT  970.075 0.8975 972.52 1.3125 ;
      RECT  972.935 0.8975 975.38 1.3125 ;
      RECT  975.795 0.8975 978.24 1.3125 ;
      RECT  978.655 0.8975 981.1 1.3125 ;
      RECT  981.515 0.8975 983.96 1.3125 ;
      RECT  984.375 0.8975 986.82 1.3125 ;
      RECT  987.235 0.8975 989.68 1.3125 ;
      RECT  990.095 0.8975 992.54 1.3125 ;
      RECT  992.955 0.8975 995.4 1.3125 ;
      RECT  995.815 0.8975 998.26 1.3125 ;
      RECT  998.675 0.8975 1001.12 1.3125 ;
      RECT  1001.535 0.8975 1003.98 1.3125 ;
      RECT  1004.395 0.8975 1006.84 1.3125 ;
      RECT  1007.255 0.8975 1009.7 1.3125 ;
      RECT  1010.115 0.8975 1012.56 1.3125 ;
      RECT  1012.975 0.8975 1015.42 1.3125 ;
      RECT  1015.835 0.8975 1018.28 1.3125 ;
      RECT  1018.695 0.8975 1021.14 1.3125 ;
      RECT  1021.555 0.8975 1024.0 1.3125 ;
      RECT  1024.415 0.8975 1026.86 1.3125 ;
      RECT  1027.275 0.8975 1029.72 1.3125 ;
      RECT  1030.135 0.8975 1032.58 1.3125 ;
      RECT  1032.995 0.8975 1035.44 1.3125 ;
      RECT  1035.855 0.8975 1038.3 1.3125 ;
      RECT  1038.715 0.8975 1041.16 1.3125 ;
      RECT  1041.575 0.8975 1044.02 1.3125 ;
      RECT  1044.435 0.8975 1046.88 1.3125 ;
      RECT  1047.295 0.8975 1049.74 1.3125 ;
      RECT  1050.155 0.8975 1052.6 1.3125 ;
      RECT  1053.015 0.8975 1055.46 1.3125 ;
      RECT  1055.875 0.8975 1058.32 1.3125 ;
      RECT  1058.735 0.8975 1061.18 1.3125 ;
      RECT  1061.595 0.8975 1064.04 1.3125 ;
      RECT  1064.455 0.8975 1066.9 1.3125 ;
      RECT  1067.315 0.8975 1069.76 1.3125 ;
      RECT  1070.175 0.8975 1072.62 1.3125 ;
      RECT  1073.035 0.8975 1075.48 1.3125 ;
      RECT  1075.895 0.8975 1078.34 1.3125 ;
      RECT  1078.755 0.8975 1081.2 1.3125 ;
      RECT  1081.615 0.8975 1084.06 1.3125 ;
      RECT  1084.475 0.8975 1086.92 1.3125 ;
      RECT  1087.335 0.8975 1089.78 1.3125 ;
      RECT  1090.195 0.8975 1092.64 1.3125 ;
      RECT  1093.055 0.8975 1095.5 1.3125 ;
      RECT  1095.915 0.8975 1098.36 1.3125 ;
      RECT  1098.775 0.8975 1101.22 1.3125 ;
      RECT  1101.635 0.8975 1104.08 1.3125 ;
      RECT  1104.495 0.8975 1106.94 1.3125 ;
      RECT  1107.355 0.8975 1109.8 1.3125 ;
      RECT  1110.215 0.8975 1112.66 1.3125 ;
      RECT  1113.075 0.8975 1115.52 1.3125 ;
      RECT  1115.935 0.8975 1118.38 1.3125 ;
      RECT  1118.795 0.8975 1121.24 1.3125 ;
      RECT  1121.655 0.8975 1124.1 1.3125 ;
      RECT  1124.515 0.8975 1126.96 1.3125 ;
      RECT  1127.375 0.8975 1129.82 1.3125 ;
      RECT  1130.235 0.8975 1132.68 1.3125 ;
      RECT  1133.095 0.8975 1135.54 1.3125 ;
      RECT  1135.955 0.8975 1138.4 1.3125 ;
      RECT  1138.815 0.8975 1141.26 1.3125 ;
      RECT  1141.675 0.8975 1144.12 1.3125 ;
      RECT  1144.535 0.8975 1146.98 1.3125 ;
      RECT  1147.395 0.8975 1149.84 1.3125 ;
      RECT  1150.255 0.8975 1152.7 1.3125 ;
      RECT  1153.115 0.8975 1155.56 1.3125 ;
      RECT  1155.975 0.8975 1158.42 1.3125 ;
      RECT  1158.835 0.8975 1161.28 1.3125 ;
      RECT  1161.695 0.8975 1164.14 1.3125 ;
      RECT  1164.555 0.8975 1167.0 1.3125 ;
      RECT  1167.415 0.8975 1169.86 1.3125 ;
      RECT  1170.275 0.8975 1172.72 1.3125 ;
      RECT  1173.135 0.8975 1175.58 1.3125 ;
      RECT  1175.995 0.8975 1178.44 1.3125 ;
      RECT  1178.855 0.8975 1181.3 1.3125 ;
      RECT  1181.715 0.8975 1184.16 1.3125 ;
      RECT  1184.575 0.8975 1187.02 1.3125 ;
      RECT  1187.435 0.8975 1189.88 1.3125 ;
      RECT  1190.295 0.8975 1192.74 1.3125 ;
      RECT  1193.155 0.8975 1195.6 1.3125 ;
      RECT  1196.015 0.8975 1198.46 1.3125 ;
      RECT  1198.875 0.8975 1201.32 1.3125 ;
      RECT  1201.735 0.8975 1204.18 1.3125 ;
      RECT  1204.595 0.8975 1207.04 1.3125 ;
      RECT  1207.455 0.8975 1209.9 1.3125 ;
      RECT  1210.315 0.8975 1212.76 1.3125 ;
      RECT  1213.175 0.8975 1215.62 1.3125 ;
      RECT  1216.035 0.8975 1218.48 1.3125 ;
      RECT  1218.895 0.8975 1221.34 1.3125 ;
      RECT  1221.755 0.8975 1224.2 1.3125 ;
      RECT  1224.615 0.8975 1227.06 1.3125 ;
      RECT  1227.475 0.8975 1229.92 1.3125 ;
      RECT  1230.335 0.8975 1232.78 1.3125 ;
      RECT  1233.195 0.8975 1235.64 1.3125 ;
      RECT  1236.055 0.8975 1238.5 1.3125 ;
      RECT  1238.915 0.8975 1241.36 1.3125 ;
      RECT  1241.775 0.8975 1244.22 1.3125 ;
      RECT  1244.635 0.8975 1247.08 1.3125 ;
      RECT  1247.495 0.8975 1249.94 1.3125 ;
      RECT  1250.355 0.8975 1252.8 1.3125 ;
      RECT  1253.215 0.8975 1255.66 1.3125 ;
      RECT  1256.075 0.8975 1258.52 1.3125 ;
      RECT  1258.935 0.8975 1261.38 1.3125 ;
      RECT  1261.795 0.8975 1264.24 1.3125 ;
      RECT  1264.655 0.8975 1267.1 1.3125 ;
      RECT  1267.515 0.8975 1269.96 1.3125 ;
      RECT  1270.375 0.8975 1272.82 1.3125 ;
      RECT  1273.235 0.8975 1275.68 1.3125 ;
      RECT  1276.095 0.8975 1278.54 1.3125 ;
      RECT  1278.955 0.8975 1281.4 1.3125 ;
      RECT  1281.815 0.8975 1284.26 1.3125 ;
      RECT  1284.675 0.8975 1287.12 1.3125 ;
      RECT  1287.535 0.8975 1289.98 1.3125 ;
      RECT  1290.395 0.8975 1292.84 1.3125 ;
      RECT  1293.255 0.8975 1295.7 1.3125 ;
      RECT  1296.115 0.8975 1298.56 1.3125 ;
      RECT  1298.975 0.8975 1301.42 1.3125 ;
      RECT  1301.835 0.8975 1304.28 1.3125 ;
      RECT  1304.695 0.8975 1307.14 1.3125 ;
      RECT  1307.555 0.8975 1310.0 1.3125 ;
      RECT  1310.415 0.8975 1312.86 1.3125 ;
      RECT  1313.275 0.8975 1315.72 1.3125 ;
      RECT  1316.135 0.8975 1318.58 1.3125 ;
      RECT  1318.995 0.8975 1321.44 1.3125 ;
      RECT  1321.855 0.8975 1324.3 1.3125 ;
      RECT  1324.715 0.8975 1327.16 1.3125 ;
      RECT  1327.575 0.8975 1330.02 1.3125 ;
      RECT  1330.435 0.8975 1332.88 1.3125 ;
      RECT  1333.295 0.8975 1335.74 1.3125 ;
      RECT  1336.155 0.8975 1338.6 1.3125 ;
      RECT  1339.015 0.8975 1341.46 1.3125 ;
      RECT  1341.875 0.8975 1344.32 1.3125 ;
      RECT  1344.735 0.8975 1347.18 1.3125 ;
      RECT  1347.595 0.8975 1350.04 1.3125 ;
      RECT  1350.455 0.8975 1352.9 1.3125 ;
      RECT  1353.315 0.8975 1355.76 1.3125 ;
      RECT  1356.175 0.8975 1358.62 1.3125 ;
      RECT  1359.035 0.8975 1361.48 1.3125 ;
      RECT  1361.895 0.8975 1364.34 1.3125 ;
      RECT  1364.755 0.8975 1367.2 1.3125 ;
      RECT  1367.615 0.8975 1370.06 1.3125 ;
      RECT  1370.475 0.8975 1372.92 1.3125 ;
      RECT  1373.335 0.8975 1375.78 1.3125 ;
      RECT  1376.195 0.8975 1378.64 1.3125 ;
      RECT  1379.055 0.8975 1381.5 1.3125 ;
      RECT  1381.915 0.8975 1384.36 1.3125 ;
      RECT  1384.775 0.8975 1387.22 1.3125 ;
      RECT  1387.635 0.8975 1390.08 1.3125 ;
      RECT  1390.495 0.8975 1392.94 1.3125 ;
      RECT  1393.355 0.8975 1395.8 1.3125 ;
      RECT  1396.215 0.8975 1398.66 1.3125 ;
      RECT  1399.075 0.8975 1401.52 1.3125 ;
      RECT  1401.935 0.8975 1404.38 1.3125 ;
      RECT  1404.795 0.8975 1407.24 1.3125 ;
      RECT  1407.655 0.8975 1410.1 1.3125 ;
      RECT  1410.515 0.8975 1412.96 1.3125 ;
      RECT  1413.375 0.8975 1415.82 1.3125 ;
      RECT  1416.235 0.8975 1418.68 1.3125 ;
      RECT  1419.095 0.8975 1421.54 1.3125 ;
      RECT  1421.955 0.8975 1424.4 1.3125 ;
      RECT  1424.815 0.8975 1427.26 1.3125 ;
      RECT  1427.675 0.8975 1430.12 1.3125 ;
      RECT  1430.535 0.8975 1432.98 1.3125 ;
      RECT  1433.395 0.8975 1435.84 1.3125 ;
      RECT  1436.255 0.8975 1438.7 1.3125 ;
      RECT  1439.115 0.8975 1441.56 1.3125 ;
      RECT  1441.975 0.8975 1444.42 1.3125 ;
      RECT  1444.835 0.8975 1447.28 1.3125 ;
      RECT  1447.695 0.8975 1450.14 1.3125 ;
      RECT  1450.555 0.8975 1453.0 1.3125 ;
      RECT  1453.415 0.8975 1455.86 1.3125 ;
      RECT  1456.275 0.8975 1458.72 1.3125 ;
      RECT  1459.135 0.8975 1461.58 1.3125 ;
      RECT  1461.995 0.8975 1464.44 1.3125 ;
      RECT  1464.855 0.8975 1467.3 1.3125 ;
      RECT  1467.715 0.8975 1470.16 1.3125 ;
      RECT  1470.575 0.8975 1473.02 1.3125 ;
      RECT  1473.435 0.8975 1475.88 1.3125 ;
      RECT  1476.295 0.8975 1478.74 1.3125 ;
      RECT  1479.155 0.8975 1481.6 1.3125 ;
      RECT  1482.015 0.8975 1484.46 1.3125 ;
      RECT  1484.875 0.8975 1487.32 1.3125 ;
      RECT  1487.735 0.8975 1490.18 1.3125 ;
      RECT  1490.595 0.8975 1493.04 1.3125 ;
      RECT  1493.455 0.8975 1495.9 1.3125 ;
      RECT  1496.315 0.8975 1498.76 1.3125 ;
      RECT  1499.175 0.8975 1501.62 1.3125 ;
      RECT  1502.035 0.8975 1504.48 1.3125 ;
      RECT  1504.895 0.8975 1507.34 1.3125 ;
      RECT  1507.755 0.8975 1510.2 1.3125 ;
      RECT  1510.615 0.8975 1513.06 1.3125 ;
      RECT  1513.475 0.8975 1515.92 1.3125 ;
      RECT  1516.335 0.8975 1518.78 1.3125 ;
      RECT  1519.195 0.8975 1521.64 1.3125 ;
      RECT  1522.055 0.8975 1524.5 1.3125 ;
      RECT  1524.915 0.8975 1527.36 1.3125 ;
      RECT  1527.775 0.8975 1530.22 1.3125 ;
      RECT  1530.635 0.8975 1533.08 1.3125 ;
      RECT  1533.495 0.8975 1535.94 1.3125 ;
      RECT  1536.355 0.8975 1538.8 1.3125 ;
      RECT  1539.215 0.8975 1541.66 1.3125 ;
      RECT  1542.075 0.8975 1544.52 1.3125 ;
      RECT  1544.935 0.8975 1547.38 1.3125 ;
      RECT  1547.795 0.8975 1550.24 1.3125 ;
      RECT  1550.655 0.8975 1553.1 1.3125 ;
      RECT  1553.515 0.8975 1555.96 1.3125 ;
      RECT  1556.375 0.8975 1558.82 1.3125 ;
      RECT  1559.235 0.8975 1561.68 1.3125 ;
      RECT  1562.095 0.8975 1564.54 1.3125 ;
      RECT  1564.955 0.8975 1567.4 1.3125 ;
      RECT  1567.815 0.8975 1570.26 1.3125 ;
      RECT  1570.675 0.8975 1573.12 1.3125 ;
      RECT  1573.535 0.8975 1575.98 1.3125 ;
      RECT  1576.395 0.8975 1578.84 1.3125 ;
      RECT  1579.255 0.8975 1581.7 1.3125 ;
      RECT  1582.115 0.8975 1584.56 1.3125 ;
      RECT  1584.975 0.8975 1587.205 1.3125 ;
      RECT  0.14 131.0825 117.38 131.4975 ;
      RECT  0.14 131.4975 117.38 495.395 ;
      RECT  117.38 1.3125 117.795 131.0825 ;
      RECT  117.795 1.3125 123.1 131.0825 ;
      RECT  117.795 131.0825 123.1 131.4975 ;
      RECT  117.795 131.4975 123.1 495.395 ;
      RECT  117.38 131.4975 117.795 133.8125 ;
      RECT  117.38 134.2275 117.795 136.0225 ;
      RECT  117.38 136.4375 117.795 138.7525 ;
      RECT  117.38 139.1675 117.795 140.9625 ;
      RECT  117.38 141.3775 117.795 143.6925 ;
      RECT  117.38 144.1075 117.795 145.9025 ;
      RECT  117.38 146.3175 117.795 148.6325 ;
      RECT  117.38 149.0475 117.795 495.395 ;
      RECT  123.515 1.3125 801.84 92.9925 ;
      RECT  123.515 92.9925 801.84 93.4075 ;
      RECT  801.84 93.4075 802.255 495.395 ;
      RECT  802.255 1.3125 1587.205 92.9925 ;
      RECT  802.255 92.9925 1587.205 93.4075 ;
      RECT  801.84 90.6775 802.255 92.9925 ;
      RECT  801.84 88.4675 802.255 90.2625 ;
      RECT  801.84 85.7375 802.255 88.0525 ;
      RECT  801.84 83.5275 802.255 85.3225 ;
      RECT  801.84 80.7975 802.255 83.1125 ;
      RECT  801.84 78.5875 802.255 80.3825 ;
      RECT  801.84 1.3125 802.255 75.4425 ;
      RECT  801.84 75.8575 802.255 78.1725 ;
      RECT  0.14 1.3125 0.145 74.2225 ;
      RECT  0.14 74.2225 0.145 74.6375 ;
      RECT  0.14 74.6375 0.145 131.0825 ;
      RECT  0.145 1.3125 0.56 74.2225 ;
      RECT  0.145 74.6375 0.56 131.0825 ;
      RECT  0.56 1.3125 117.38 74.2225 ;
      RECT  802.255 494.6375 919.075 495.395 ;
      RECT  919.075 93.4075 919.49 494.2225 ;
      RECT  919.075 494.6375 919.49 495.395 ;
      RECT  919.49 93.4075 1587.205 494.2225 ;
      RECT  919.49 494.2225 1587.205 494.6375 ;
      RECT  919.49 494.6375 1587.205 495.395 ;
      RECT  0.56 74.2225 6.1075 74.3075 ;
      RECT  0.56 74.3075 6.1075 74.6375 ;
      RECT  6.1075 74.2225 6.5225 74.3075 ;
      RECT  6.5225 74.2225 117.38 74.3075 ;
      RECT  6.5225 74.3075 117.38 74.6375 ;
      RECT  0.56 74.6375 6.1075 74.7225 ;
      RECT  0.56 74.7225 6.1075 131.0825 ;
      RECT  6.1075 74.7225 6.5225 131.0825 ;
      RECT  6.5225 74.6375 117.38 74.7225 ;
      RECT  6.5225 74.7225 117.38 131.0825 ;
      RECT  802.255 93.4075 913.1125 494.1375 ;
      RECT  802.255 494.1375 913.1125 494.2225 ;
      RECT  913.1125 93.4075 913.5275 494.1375 ;
      RECT  913.5275 93.4075 919.075 494.1375 ;
      RECT  913.5275 494.1375 919.075 494.2225 ;
      RECT  802.255 494.2225 913.1125 494.5525 ;
      RECT  802.255 494.5525 913.1125 494.6375 ;
      RECT  913.1125 494.5525 913.5275 494.6375 ;
      RECT  913.5275 494.2225 919.075 494.5525 ;
      RECT  913.5275 494.5525 919.075 494.6375 ;
      RECT  123.515 93.4075 158.74 488.02 ;
      RECT  123.515 488.02 158.74 488.435 ;
      RECT  123.515 488.435 158.74 495.395 ;
      RECT  158.74 93.4075 159.155 488.02 ;
      RECT  158.74 488.435 159.155 495.395 ;
      RECT  159.155 93.4075 801.84 488.02 ;
      RECT  159.155 488.435 801.84 495.395 ;
      RECT  159.155 488.02 159.915 488.435 ;
      RECT  160.33 488.02 161.09 488.435 ;
      RECT  161.505 488.02 162.265 488.435 ;
      RECT  162.68 488.02 163.44 488.435 ;
      RECT  163.855 488.02 164.615 488.435 ;
      RECT  165.03 488.02 165.79 488.435 ;
      RECT  166.205 488.02 166.965 488.435 ;
      RECT  167.38 488.02 168.14 488.435 ;
      RECT  168.555 488.02 169.315 488.435 ;
      RECT  169.73 488.02 170.49 488.435 ;
      RECT  170.905 488.02 171.665 488.435 ;
      RECT  172.08 488.02 172.84 488.435 ;
      RECT  173.255 488.02 174.015 488.435 ;
      RECT  174.43 488.02 175.19 488.435 ;
      RECT  175.605 488.02 176.365 488.435 ;
      RECT  176.78 488.02 177.54 488.435 ;
      RECT  177.955 488.02 178.715 488.435 ;
      RECT  179.13 488.02 179.89 488.435 ;
      RECT  180.305 488.02 181.065 488.435 ;
      RECT  181.48 488.02 182.24 488.435 ;
      RECT  182.655 488.02 183.415 488.435 ;
      RECT  183.83 488.02 184.59 488.435 ;
      RECT  185.005 488.02 185.765 488.435 ;
      RECT  186.18 488.02 186.94 488.435 ;
      RECT  187.355 488.02 188.115 488.435 ;
      RECT  188.53 488.02 189.29 488.435 ;
      RECT  189.705 488.02 190.465 488.435 ;
      RECT  190.88 488.02 191.64 488.435 ;
      RECT  192.055 488.02 192.815 488.435 ;
      RECT  193.23 488.02 193.99 488.435 ;
      RECT  194.405 488.02 195.165 488.435 ;
      RECT  195.58 488.02 196.34 488.435 ;
      RECT  196.755 488.02 197.515 488.435 ;
      RECT  197.93 488.02 198.69 488.435 ;
      RECT  199.105 488.02 199.865 488.435 ;
      RECT  200.28 488.02 201.04 488.435 ;
      RECT  201.455 488.02 202.215 488.435 ;
      RECT  202.63 488.02 203.39 488.435 ;
      RECT  203.805 488.02 204.565 488.435 ;
      RECT  204.98 488.02 205.74 488.435 ;
      RECT  206.155 488.02 206.915 488.435 ;
      RECT  207.33 488.02 208.09 488.435 ;
      RECT  208.505 488.02 209.265 488.435 ;
      RECT  209.68 488.02 210.44 488.435 ;
      RECT  210.855 488.02 211.615 488.435 ;
      RECT  212.03 488.02 212.79 488.435 ;
      RECT  213.205 488.02 213.965 488.435 ;
      RECT  214.38 488.02 215.14 488.435 ;
      RECT  215.555 488.02 216.315 488.435 ;
      RECT  216.73 488.02 217.49 488.435 ;
      RECT  217.905 488.02 218.665 488.435 ;
      RECT  219.08 488.02 219.84 488.435 ;
      RECT  220.255 488.02 221.015 488.435 ;
      RECT  221.43 488.02 222.19 488.435 ;
      RECT  222.605 488.02 223.365 488.435 ;
      RECT  223.78 488.02 224.54 488.435 ;
      RECT  224.955 488.02 225.715 488.435 ;
      RECT  226.13 488.02 226.89 488.435 ;
      RECT  227.305 488.02 228.065 488.435 ;
      RECT  228.48 488.02 229.24 488.435 ;
      RECT  229.655 488.02 230.415 488.435 ;
      RECT  230.83 488.02 231.59 488.435 ;
      RECT  232.005 488.02 232.765 488.435 ;
      RECT  233.18 488.02 233.94 488.435 ;
      RECT  234.355 488.02 235.115 488.435 ;
      RECT  235.53 488.02 236.29 488.435 ;
      RECT  236.705 488.02 237.465 488.435 ;
      RECT  237.88 488.02 238.64 488.435 ;
      RECT  239.055 488.02 239.815 488.435 ;
      RECT  240.23 488.02 240.99 488.435 ;
      RECT  241.405 488.02 242.165 488.435 ;
      RECT  242.58 488.02 243.34 488.435 ;
      RECT  243.755 488.02 244.515 488.435 ;
      RECT  244.93 488.02 245.69 488.435 ;
      RECT  246.105 488.02 246.865 488.435 ;
      RECT  247.28 488.02 248.04 488.435 ;
      RECT  248.455 488.02 249.215 488.435 ;
      RECT  249.63 488.02 250.39 488.435 ;
      RECT  250.805 488.02 251.565 488.435 ;
      RECT  251.98 488.02 252.74 488.435 ;
      RECT  253.155 488.02 253.915 488.435 ;
      RECT  254.33 488.02 255.09 488.435 ;
      RECT  255.505 488.02 256.265 488.435 ;
      RECT  256.68 488.02 257.44 488.435 ;
      RECT  257.855 488.02 258.615 488.435 ;
      RECT  259.03 488.02 259.79 488.435 ;
      RECT  260.205 488.02 260.965 488.435 ;
      RECT  261.38 488.02 262.14 488.435 ;
      RECT  262.555 488.02 263.315 488.435 ;
      RECT  263.73 488.02 264.49 488.435 ;
      RECT  264.905 488.02 265.665 488.435 ;
      RECT  266.08 488.02 266.84 488.435 ;
      RECT  267.255 488.02 268.015 488.435 ;
      RECT  268.43 488.02 269.19 488.435 ;
      RECT  269.605 488.02 270.365 488.435 ;
      RECT  270.78 488.02 271.54 488.435 ;
      RECT  271.955 488.02 272.715 488.435 ;
      RECT  273.13 488.02 273.89 488.435 ;
      RECT  274.305 488.02 275.065 488.435 ;
      RECT  275.48 488.02 276.24 488.435 ;
      RECT  276.655 488.02 277.415 488.435 ;
      RECT  277.83 488.02 278.59 488.435 ;
      RECT  279.005 488.02 279.765 488.435 ;
      RECT  280.18 488.02 280.94 488.435 ;
      RECT  281.355 488.02 282.115 488.435 ;
      RECT  282.53 488.02 283.29 488.435 ;
      RECT  283.705 488.02 284.465 488.435 ;
      RECT  284.88 488.02 285.64 488.435 ;
      RECT  286.055 488.02 286.815 488.435 ;
      RECT  287.23 488.02 287.99 488.435 ;
      RECT  288.405 488.02 289.165 488.435 ;
      RECT  289.58 488.02 290.34 488.435 ;
      RECT  290.755 488.02 291.515 488.435 ;
      RECT  291.93 488.02 292.69 488.435 ;
      RECT  293.105 488.02 293.865 488.435 ;
      RECT  294.28 488.02 295.04 488.435 ;
      RECT  295.455 488.02 296.215 488.435 ;
      RECT  296.63 488.02 297.39 488.435 ;
      RECT  297.805 488.02 298.565 488.435 ;
      RECT  298.98 488.02 299.74 488.435 ;
      RECT  300.155 488.02 300.915 488.435 ;
      RECT  301.33 488.02 302.09 488.435 ;
      RECT  302.505 488.02 303.265 488.435 ;
      RECT  303.68 488.02 304.44 488.435 ;
      RECT  304.855 488.02 305.615 488.435 ;
      RECT  306.03 488.02 306.79 488.435 ;
      RECT  307.205 488.02 307.965 488.435 ;
      RECT  308.38 488.02 309.14 488.435 ;
      RECT  309.555 488.02 310.315 488.435 ;
      RECT  310.73 488.02 311.49 488.435 ;
      RECT  311.905 488.02 312.665 488.435 ;
      RECT  313.08 488.02 313.84 488.435 ;
      RECT  314.255 488.02 315.015 488.435 ;
      RECT  315.43 488.02 316.19 488.435 ;
      RECT  316.605 488.02 317.365 488.435 ;
      RECT  317.78 488.02 318.54 488.435 ;
      RECT  318.955 488.02 319.715 488.435 ;
      RECT  320.13 488.02 320.89 488.435 ;
      RECT  321.305 488.02 322.065 488.435 ;
      RECT  322.48 488.02 323.24 488.435 ;
      RECT  323.655 488.02 324.415 488.435 ;
      RECT  324.83 488.02 325.59 488.435 ;
      RECT  326.005 488.02 326.765 488.435 ;
      RECT  327.18 488.02 327.94 488.435 ;
      RECT  328.355 488.02 329.115 488.435 ;
      RECT  329.53 488.02 330.29 488.435 ;
      RECT  330.705 488.02 331.465 488.435 ;
      RECT  331.88 488.02 332.64 488.435 ;
      RECT  333.055 488.02 333.815 488.435 ;
      RECT  334.23 488.02 334.99 488.435 ;
      RECT  335.405 488.02 336.165 488.435 ;
      RECT  336.58 488.02 337.34 488.435 ;
      RECT  337.755 488.02 338.515 488.435 ;
      RECT  338.93 488.02 339.69 488.435 ;
      RECT  340.105 488.02 340.865 488.435 ;
      RECT  341.28 488.02 342.04 488.435 ;
      RECT  342.455 488.02 343.215 488.435 ;
      RECT  343.63 488.02 344.39 488.435 ;
      RECT  344.805 488.02 345.565 488.435 ;
      RECT  345.98 488.02 346.74 488.435 ;
      RECT  347.155 488.02 347.915 488.435 ;
      RECT  348.33 488.02 349.09 488.435 ;
      RECT  349.505 488.02 350.265 488.435 ;
      RECT  350.68 488.02 351.44 488.435 ;
      RECT  351.855 488.02 352.615 488.435 ;
      RECT  353.03 488.02 353.79 488.435 ;
      RECT  354.205 488.02 354.965 488.435 ;
      RECT  355.38 488.02 356.14 488.435 ;
      RECT  356.555 488.02 357.315 488.435 ;
      RECT  357.73 488.02 358.49 488.435 ;
      RECT  358.905 488.02 359.665 488.435 ;
      RECT  360.08 488.02 360.84 488.435 ;
      RECT  361.255 488.02 362.015 488.435 ;
      RECT  362.43 488.02 363.19 488.435 ;
      RECT  363.605 488.02 364.365 488.435 ;
      RECT  364.78 488.02 365.54 488.435 ;
      RECT  365.955 488.02 366.715 488.435 ;
      RECT  367.13 488.02 367.89 488.435 ;
      RECT  368.305 488.02 369.065 488.435 ;
      RECT  369.48 488.02 370.24 488.435 ;
      RECT  370.655 488.02 371.415 488.435 ;
      RECT  371.83 488.02 372.59 488.435 ;
      RECT  373.005 488.02 373.765 488.435 ;
      RECT  374.18 488.02 374.94 488.435 ;
      RECT  375.355 488.02 376.115 488.435 ;
      RECT  376.53 488.02 377.29 488.435 ;
      RECT  377.705 488.02 378.465 488.435 ;
      RECT  378.88 488.02 379.64 488.435 ;
      RECT  380.055 488.02 380.815 488.435 ;
      RECT  381.23 488.02 381.99 488.435 ;
      RECT  382.405 488.02 383.165 488.435 ;
      RECT  383.58 488.02 384.34 488.435 ;
      RECT  384.755 488.02 385.515 488.435 ;
      RECT  385.93 488.02 386.69 488.435 ;
      RECT  387.105 488.02 387.865 488.435 ;
      RECT  388.28 488.02 389.04 488.435 ;
      RECT  389.455 488.02 390.215 488.435 ;
      RECT  390.63 488.02 391.39 488.435 ;
      RECT  391.805 488.02 392.565 488.435 ;
      RECT  392.98 488.02 393.74 488.435 ;
      RECT  394.155 488.02 394.915 488.435 ;
      RECT  395.33 488.02 396.09 488.435 ;
      RECT  396.505 488.02 397.265 488.435 ;
      RECT  397.68 488.02 398.44 488.435 ;
      RECT  398.855 488.02 399.615 488.435 ;
      RECT  400.03 488.02 400.79 488.435 ;
      RECT  401.205 488.02 401.965 488.435 ;
      RECT  402.38 488.02 403.14 488.435 ;
      RECT  403.555 488.02 404.315 488.435 ;
      RECT  404.73 488.02 405.49 488.435 ;
      RECT  405.905 488.02 406.665 488.435 ;
      RECT  407.08 488.02 407.84 488.435 ;
      RECT  408.255 488.02 409.015 488.435 ;
      RECT  409.43 488.02 410.19 488.435 ;
      RECT  410.605 488.02 411.365 488.435 ;
      RECT  411.78 488.02 412.54 488.435 ;
      RECT  412.955 488.02 413.715 488.435 ;
      RECT  414.13 488.02 414.89 488.435 ;
      RECT  415.305 488.02 416.065 488.435 ;
      RECT  416.48 488.02 417.24 488.435 ;
      RECT  417.655 488.02 418.415 488.435 ;
      RECT  418.83 488.02 419.59 488.435 ;
      RECT  420.005 488.02 420.765 488.435 ;
      RECT  421.18 488.02 421.94 488.435 ;
      RECT  422.355 488.02 423.115 488.435 ;
      RECT  423.53 488.02 424.29 488.435 ;
      RECT  424.705 488.02 425.465 488.435 ;
      RECT  425.88 488.02 426.64 488.435 ;
      RECT  427.055 488.02 427.815 488.435 ;
      RECT  428.23 488.02 428.99 488.435 ;
      RECT  429.405 488.02 430.165 488.435 ;
      RECT  430.58 488.02 431.34 488.435 ;
      RECT  431.755 488.02 432.515 488.435 ;
      RECT  432.93 488.02 433.69 488.435 ;
      RECT  434.105 488.02 434.865 488.435 ;
      RECT  435.28 488.02 436.04 488.435 ;
      RECT  436.455 488.02 437.215 488.435 ;
      RECT  437.63 488.02 438.39 488.435 ;
      RECT  438.805 488.02 439.565 488.435 ;
      RECT  439.98 488.02 440.74 488.435 ;
      RECT  441.155 488.02 441.915 488.435 ;
      RECT  442.33 488.02 443.09 488.435 ;
      RECT  443.505 488.02 444.265 488.435 ;
      RECT  444.68 488.02 445.44 488.435 ;
      RECT  445.855 488.02 446.615 488.435 ;
      RECT  447.03 488.02 447.79 488.435 ;
      RECT  448.205 488.02 448.965 488.435 ;
      RECT  449.38 488.02 450.14 488.435 ;
      RECT  450.555 488.02 451.315 488.435 ;
      RECT  451.73 488.02 452.49 488.435 ;
      RECT  452.905 488.02 453.665 488.435 ;
      RECT  454.08 488.02 454.84 488.435 ;
      RECT  455.255 488.02 456.015 488.435 ;
      RECT  456.43 488.02 457.19 488.435 ;
      RECT  457.605 488.02 458.365 488.435 ;
      RECT  458.78 488.02 459.54 488.435 ;
      RECT  459.955 488.02 460.715 488.435 ;
      RECT  461.13 488.02 461.89 488.435 ;
      RECT  462.305 488.02 463.065 488.435 ;
      RECT  463.48 488.02 464.24 488.435 ;
      RECT  464.655 488.02 465.415 488.435 ;
      RECT  465.83 488.02 466.59 488.435 ;
      RECT  467.005 488.02 467.765 488.435 ;
      RECT  468.18 488.02 468.94 488.435 ;
      RECT  469.355 488.02 470.115 488.435 ;
      RECT  470.53 488.02 471.29 488.435 ;
      RECT  471.705 488.02 472.465 488.435 ;
      RECT  472.88 488.02 473.64 488.435 ;
      RECT  474.055 488.02 474.815 488.435 ;
      RECT  475.23 488.02 475.99 488.435 ;
      RECT  476.405 488.02 477.165 488.435 ;
      RECT  477.58 488.02 478.34 488.435 ;
      RECT  478.755 488.02 479.515 488.435 ;
      RECT  479.93 488.02 480.69 488.435 ;
      RECT  481.105 488.02 481.865 488.435 ;
      RECT  482.28 488.02 483.04 488.435 ;
      RECT  483.455 488.02 484.215 488.435 ;
      RECT  484.63 488.02 485.39 488.435 ;
      RECT  485.805 488.02 486.565 488.435 ;
      RECT  486.98 488.02 487.74 488.435 ;
      RECT  488.155 488.02 488.915 488.435 ;
      RECT  489.33 488.02 490.09 488.435 ;
      RECT  490.505 488.02 491.265 488.435 ;
      RECT  491.68 488.02 492.44 488.435 ;
      RECT  492.855 488.02 493.615 488.435 ;
      RECT  494.03 488.02 494.79 488.435 ;
      RECT  495.205 488.02 495.965 488.435 ;
      RECT  496.38 488.02 497.14 488.435 ;
      RECT  497.555 488.02 498.315 488.435 ;
      RECT  498.73 488.02 499.49 488.435 ;
      RECT  499.905 488.02 500.665 488.435 ;
      RECT  501.08 488.02 501.84 488.435 ;
      RECT  502.255 488.02 503.015 488.435 ;
      RECT  503.43 488.02 504.19 488.435 ;
      RECT  504.605 488.02 505.365 488.435 ;
      RECT  505.78 488.02 506.54 488.435 ;
      RECT  506.955 488.02 507.715 488.435 ;
      RECT  508.13 488.02 508.89 488.435 ;
      RECT  509.305 488.02 510.065 488.435 ;
      RECT  510.48 488.02 511.24 488.435 ;
      RECT  511.655 488.02 512.415 488.435 ;
      RECT  512.83 488.02 513.59 488.435 ;
      RECT  514.005 488.02 514.765 488.435 ;
      RECT  515.18 488.02 515.94 488.435 ;
      RECT  516.355 488.02 517.115 488.435 ;
      RECT  517.53 488.02 518.29 488.435 ;
      RECT  518.705 488.02 519.465 488.435 ;
      RECT  519.88 488.02 520.64 488.435 ;
      RECT  521.055 488.02 521.815 488.435 ;
      RECT  522.23 488.02 522.99 488.435 ;
      RECT  523.405 488.02 524.165 488.435 ;
      RECT  524.58 488.02 525.34 488.435 ;
      RECT  525.755 488.02 526.515 488.435 ;
      RECT  526.93 488.02 527.69 488.435 ;
      RECT  528.105 488.02 528.865 488.435 ;
      RECT  529.28 488.02 530.04 488.435 ;
      RECT  530.455 488.02 531.215 488.435 ;
      RECT  531.63 488.02 532.39 488.435 ;
      RECT  532.805 488.02 533.565 488.435 ;
      RECT  533.98 488.02 534.74 488.435 ;
      RECT  535.155 488.02 535.915 488.435 ;
      RECT  536.33 488.02 537.09 488.435 ;
      RECT  537.505 488.02 538.265 488.435 ;
      RECT  538.68 488.02 539.44 488.435 ;
      RECT  539.855 488.02 540.615 488.435 ;
      RECT  541.03 488.02 541.79 488.435 ;
      RECT  542.205 488.02 542.965 488.435 ;
      RECT  543.38 488.02 544.14 488.435 ;
      RECT  544.555 488.02 545.315 488.435 ;
      RECT  545.73 488.02 546.49 488.435 ;
      RECT  546.905 488.02 547.665 488.435 ;
      RECT  548.08 488.02 548.84 488.435 ;
      RECT  549.255 488.02 550.015 488.435 ;
      RECT  550.43 488.02 551.19 488.435 ;
      RECT  551.605 488.02 552.365 488.435 ;
      RECT  552.78 488.02 553.54 488.435 ;
      RECT  553.955 488.02 554.715 488.435 ;
      RECT  555.13 488.02 555.89 488.435 ;
      RECT  556.305 488.02 557.065 488.435 ;
      RECT  557.48 488.02 558.24 488.435 ;
      RECT  558.655 488.02 559.415 488.435 ;
      RECT  559.83 488.02 560.59 488.435 ;
      RECT  561.005 488.02 561.765 488.435 ;
      RECT  562.18 488.02 562.94 488.435 ;
      RECT  563.355 488.02 564.115 488.435 ;
      RECT  564.53 488.02 565.29 488.435 ;
      RECT  565.705 488.02 566.465 488.435 ;
      RECT  566.88 488.02 567.64 488.435 ;
      RECT  568.055 488.02 568.815 488.435 ;
      RECT  569.23 488.02 569.99 488.435 ;
      RECT  570.405 488.02 571.165 488.435 ;
      RECT  571.58 488.02 572.34 488.435 ;
      RECT  572.755 488.02 573.515 488.435 ;
      RECT  573.93 488.02 574.69 488.435 ;
      RECT  575.105 488.02 575.865 488.435 ;
      RECT  576.28 488.02 577.04 488.435 ;
      RECT  577.455 488.02 578.215 488.435 ;
      RECT  578.63 488.02 579.39 488.435 ;
      RECT  579.805 488.02 580.565 488.435 ;
      RECT  580.98 488.02 581.74 488.435 ;
      RECT  582.155 488.02 582.915 488.435 ;
      RECT  583.33 488.02 584.09 488.435 ;
      RECT  584.505 488.02 585.265 488.435 ;
      RECT  585.68 488.02 586.44 488.435 ;
      RECT  586.855 488.02 587.615 488.435 ;
      RECT  588.03 488.02 588.79 488.435 ;
      RECT  589.205 488.02 589.965 488.435 ;
      RECT  590.38 488.02 591.14 488.435 ;
      RECT  591.555 488.02 592.315 488.435 ;
      RECT  592.73 488.02 593.49 488.435 ;
      RECT  593.905 488.02 594.665 488.435 ;
      RECT  595.08 488.02 595.84 488.435 ;
      RECT  596.255 488.02 597.015 488.435 ;
      RECT  597.43 488.02 598.19 488.435 ;
      RECT  598.605 488.02 599.365 488.435 ;
      RECT  599.78 488.02 600.54 488.435 ;
      RECT  600.955 488.02 601.715 488.435 ;
      RECT  602.13 488.02 602.89 488.435 ;
      RECT  603.305 488.02 604.065 488.435 ;
      RECT  604.48 488.02 605.24 488.435 ;
      RECT  605.655 488.02 606.415 488.435 ;
      RECT  606.83 488.02 607.59 488.435 ;
      RECT  608.005 488.02 608.765 488.435 ;
      RECT  609.18 488.02 609.94 488.435 ;
      RECT  610.355 488.02 611.115 488.435 ;
      RECT  611.53 488.02 612.29 488.435 ;
      RECT  612.705 488.02 613.465 488.435 ;
      RECT  613.88 488.02 614.64 488.435 ;
      RECT  615.055 488.02 615.815 488.435 ;
      RECT  616.23 488.02 616.99 488.435 ;
      RECT  617.405 488.02 618.165 488.435 ;
      RECT  618.58 488.02 619.34 488.435 ;
      RECT  619.755 488.02 620.515 488.435 ;
      RECT  620.93 488.02 621.69 488.435 ;
      RECT  622.105 488.02 622.865 488.435 ;
      RECT  623.28 488.02 624.04 488.435 ;
      RECT  624.455 488.02 625.215 488.435 ;
      RECT  625.63 488.02 626.39 488.435 ;
      RECT  626.805 488.02 627.565 488.435 ;
      RECT  627.98 488.02 628.74 488.435 ;
      RECT  629.155 488.02 629.915 488.435 ;
      RECT  630.33 488.02 631.09 488.435 ;
      RECT  631.505 488.02 632.265 488.435 ;
      RECT  632.68 488.02 633.44 488.435 ;
      RECT  633.855 488.02 634.615 488.435 ;
      RECT  635.03 488.02 635.79 488.435 ;
      RECT  636.205 488.02 636.965 488.435 ;
      RECT  637.38 488.02 638.14 488.435 ;
      RECT  638.555 488.02 639.315 488.435 ;
      RECT  639.73 488.02 640.49 488.435 ;
      RECT  640.905 488.02 641.665 488.435 ;
      RECT  642.08 488.02 642.84 488.435 ;
      RECT  643.255 488.02 644.015 488.435 ;
      RECT  644.43 488.02 645.19 488.435 ;
      RECT  645.605 488.02 646.365 488.435 ;
      RECT  646.78 488.02 647.54 488.435 ;
      RECT  647.955 488.02 648.715 488.435 ;
      RECT  649.13 488.02 649.89 488.435 ;
      RECT  650.305 488.02 651.065 488.435 ;
      RECT  651.48 488.02 652.24 488.435 ;
      RECT  652.655 488.02 653.415 488.435 ;
      RECT  653.83 488.02 654.59 488.435 ;
      RECT  655.005 488.02 655.765 488.435 ;
      RECT  656.18 488.02 656.94 488.435 ;
      RECT  657.355 488.02 658.115 488.435 ;
      RECT  658.53 488.02 659.29 488.435 ;
      RECT  659.705 488.02 660.465 488.435 ;
      RECT  660.88 488.02 661.64 488.435 ;
      RECT  662.055 488.02 662.815 488.435 ;
      RECT  663.23 488.02 663.99 488.435 ;
      RECT  664.405 488.02 665.165 488.435 ;
      RECT  665.58 488.02 666.34 488.435 ;
      RECT  666.755 488.02 667.515 488.435 ;
      RECT  667.93 488.02 668.69 488.435 ;
      RECT  669.105 488.02 669.865 488.435 ;
      RECT  670.28 488.02 671.04 488.435 ;
      RECT  671.455 488.02 672.215 488.435 ;
      RECT  672.63 488.02 673.39 488.435 ;
      RECT  673.805 488.02 674.565 488.435 ;
      RECT  674.98 488.02 675.74 488.435 ;
      RECT  676.155 488.02 676.915 488.435 ;
      RECT  677.33 488.02 678.09 488.435 ;
      RECT  678.505 488.02 679.265 488.435 ;
      RECT  679.68 488.02 680.44 488.435 ;
      RECT  680.855 488.02 681.615 488.435 ;
      RECT  682.03 488.02 682.79 488.435 ;
      RECT  683.205 488.02 683.965 488.435 ;
      RECT  684.38 488.02 685.14 488.435 ;
      RECT  685.555 488.02 686.315 488.435 ;
      RECT  686.73 488.02 687.49 488.435 ;
      RECT  687.905 488.02 688.665 488.435 ;
      RECT  689.08 488.02 689.84 488.435 ;
      RECT  690.255 488.02 691.015 488.435 ;
      RECT  691.43 488.02 692.19 488.435 ;
      RECT  692.605 488.02 693.365 488.435 ;
      RECT  693.78 488.02 694.54 488.435 ;
      RECT  694.955 488.02 695.715 488.435 ;
      RECT  696.13 488.02 696.89 488.435 ;
      RECT  697.305 488.02 698.065 488.435 ;
      RECT  698.48 488.02 699.24 488.435 ;
      RECT  699.655 488.02 700.415 488.435 ;
      RECT  700.83 488.02 701.59 488.435 ;
      RECT  702.005 488.02 702.765 488.435 ;
      RECT  703.18 488.02 703.94 488.435 ;
      RECT  704.355 488.02 705.115 488.435 ;
      RECT  705.53 488.02 706.29 488.435 ;
      RECT  706.705 488.02 707.465 488.435 ;
      RECT  707.88 488.02 708.64 488.435 ;
      RECT  709.055 488.02 709.815 488.435 ;
      RECT  710.23 488.02 710.99 488.435 ;
      RECT  711.405 488.02 712.165 488.435 ;
      RECT  712.58 488.02 713.34 488.435 ;
      RECT  713.755 488.02 714.515 488.435 ;
      RECT  714.93 488.02 715.69 488.435 ;
      RECT  716.105 488.02 716.865 488.435 ;
      RECT  717.28 488.02 718.04 488.435 ;
      RECT  718.455 488.02 719.215 488.435 ;
      RECT  719.63 488.02 720.39 488.435 ;
      RECT  720.805 488.02 721.565 488.435 ;
      RECT  721.98 488.02 722.74 488.435 ;
      RECT  723.155 488.02 723.915 488.435 ;
      RECT  724.33 488.02 725.09 488.435 ;
      RECT  725.505 488.02 726.265 488.435 ;
      RECT  726.68 488.02 727.44 488.435 ;
      RECT  727.855 488.02 728.615 488.435 ;
      RECT  729.03 488.02 729.79 488.435 ;
      RECT  730.205 488.02 730.965 488.435 ;
      RECT  731.38 488.02 732.14 488.435 ;
      RECT  732.555 488.02 733.315 488.435 ;
      RECT  733.73 488.02 734.49 488.435 ;
      RECT  734.905 488.02 735.665 488.435 ;
      RECT  736.08 488.02 736.84 488.435 ;
      RECT  737.255 488.02 738.015 488.435 ;
      RECT  738.43 488.02 739.19 488.435 ;
      RECT  739.605 488.02 740.365 488.435 ;
      RECT  740.78 488.02 741.54 488.435 ;
      RECT  741.955 488.02 742.715 488.435 ;
      RECT  743.13 488.02 743.89 488.435 ;
      RECT  744.305 488.02 745.065 488.435 ;
      RECT  745.48 488.02 746.24 488.435 ;
      RECT  746.655 488.02 747.415 488.435 ;
      RECT  747.83 488.02 748.59 488.435 ;
      RECT  749.005 488.02 749.765 488.435 ;
      RECT  750.18 488.02 750.94 488.435 ;
      RECT  751.355 488.02 752.115 488.435 ;
      RECT  752.53 488.02 753.29 488.435 ;
      RECT  753.705 488.02 754.465 488.435 ;
      RECT  754.88 488.02 755.64 488.435 ;
      RECT  756.055 488.02 756.815 488.435 ;
      RECT  757.23 488.02 757.99 488.435 ;
      RECT  758.405 488.02 759.165 488.435 ;
      RECT  759.58 488.02 801.84 488.435 ;
   LAYER  metal4 ;
      RECT  0.14 0.14 1587.205 495.395 ;
   END
END    openram45_256x512_1r1w
END    LIBRARY
